VERSION 5.8 ;
BUSBITCHARS "[]" ;
DIVIDERCHAR "/" ;
UNITS
    DATABASE MICRONS 1000 ;
END UNITS

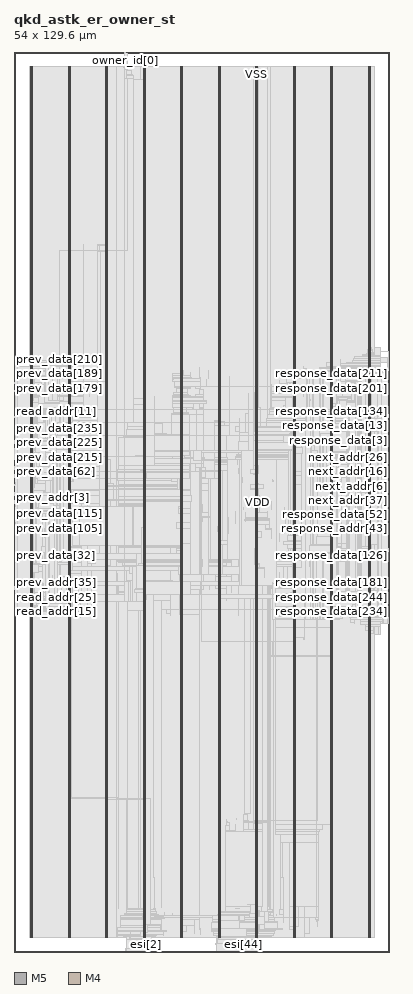
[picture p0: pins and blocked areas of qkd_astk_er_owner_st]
MACRO qkd_astk_er_owner_st
  FOREIGN qkd_astk_er_owner_st 0 0 ;
  CLASS BLOCK ;
  SIZE 54 BY 129.6 ;
  PIN aso[0]
    DIRECTION OUTPUT ;
    USE SIGNAL ;
    PORT
      LAYER M5 ;
        RECT  16.08 0 16.104 0.084 ;
    END
  END aso[0]
  PIN aso[10]
    DIRECTION OUTPUT ;
    USE SIGNAL ;
    PORT
      LAYER M5 ;
        RECT  17.04 0 17.064 0.084 ;
    END
  END aso[10]
  PIN aso[11]
    DIRECTION OUTPUT ;
    USE SIGNAL ;
    PORT
      LAYER M5 ;
        RECT  17.136 0 17.16 0.084 ;
    END
  END aso[11]
  PIN aso[12]
    DIRECTION OUTPUT ;
    USE SIGNAL ;
    PORT
      LAYER M5 ;
        RECT  17.232 0 17.256 0.084 ;
    END
  END aso[12]
  PIN aso[1]
    DIRECTION OUTPUT ;
    USE SIGNAL ;
    PORT
      LAYER M5 ;
        RECT  16.176 0 16.2 0.084 ;
    END
  END aso[1]
  PIN aso[2]
    DIRECTION OUTPUT ;
    USE SIGNAL ;
    PORT
      LAYER M5 ;
        RECT  16.272 0 16.296 0.084 ;
    END
  END aso[2]
  PIN aso[3]
    DIRECTION OUTPUT ;
    USE SIGNAL ;
    PORT
      LAYER M5 ;
        RECT  16.368 0 16.392 0.084 ;
    END
  END aso[3]
  PIN aso[4]
    DIRECTION OUTPUT ;
    USE SIGNAL ;
    PORT
      LAYER M5 ;
        RECT  16.464 0 16.488 0.084 ;
    END
  END aso[4]
  PIN aso[5]
    DIRECTION OUTPUT ;
    USE SIGNAL ;
    PORT
      LAYER M5 ;
        RECT  16.56 0 16.584 0.084 ;
    END
  END aso[5]
  PIN aso[6]
    DIRECTION OUTPUT ;
    USE SIGNAL ;
    PORT
      LAYER M5 ;
        RECT  16.656 0 16.68 0.084 ;
    END
  END aso[6]
  PIN aso[7]
    DIRECTION OUTPUT ;
    USE SIGNAL ;
    PORT
      LAYER M5 ;
        RECT  16.752 0 16.776 0.084 ;
    END
  END aso[7]
  PIN aso[8]
    DIRECTION OUTPUT ;
    USE SIGNAL ;
    PORT
      LAYER M5 ;
        RECT  16.848 0 16.872 0.084 ;
    END
  END aso[8]
  PIN aso[9]
    DIRECTION OUTPUT ;
    USE SIGNAL ;
    PORT
      LAYER M5 ;
        RECT  16.944 0 16.968 0.084 ;
    END
  END aso[9]
  PIN ck
    DIRECTION INPUT ;
    USE SIGNAL ;
    PORT
      LAYER M5 ;
        RECT  15.888 129.516 15.912 129.6 ;
    END
  END ck
  PIN com[0]
    DIRECTION INPUT ;
    USE SIGNAL ;
    PORT
      LAYER M5 ;
        RECT  17.328 0 17.352 0.084 ;
    END
  END com[0]
  PIN com[10]
    DIRECTION INPUT ;
    USE SIGNAL ;
    PORT
      LAYER M5 ;
        RECT  18.288 0 18.312 0.084 ;
    END
  END com[10]
  PIN com[11]
    DIRECTION INPUT ;
    USE SIGNAL ;
    PORT
      LAYER M5 ;
        RECT  18.384 0 18.408 0.084 ;
    END
  END com[11]
  PIN com[12]
    DIRECTION INPUT ;
    USE SIGNAL ;
    PORT
      LAYER M5 ;
        RECT  18.48 0 18.504 0.084 ;
    END
  END com[12]
  PIN com[13]
    DIRECTION INPUT ;
    USE SIGNAL ;
    PORT
      LAYER M5 ;
        RECT  18.576 0 18.6 0.084 ;
    END
  END com[13]
  PIN com[14]
    DIRECTION INPUT ;
    USE SIGNAL ;
    PORT
      LAYER M5 ;
        RECT  18.672 0 18.696 0.084 ;
    END
  END com[14]
  PIN com[15]
    DIRECTION INPUT ;
    USE SIGNAL ;
    PORT
      LAYER M5 ;
        RECT  18.768 0 18.792 0.084 ;
    END
  END com[15]
  PIN com[1]
    DIRECTION INPUT ;
    USE SIGNAL ;
    PORT
      LAYER M5 ;
        RECT  17.424 0 17.448 0.084 ;
    END
  END com[1]
  PIN com[2]
    DIRECTION INPUT ;
    USE SIGNAL ;
    PORT
      LAYER M5 ;
        RECT  17.52 0 17.544 0.084 ;
    END
  END com[2]
  PIN com[3]
    DIRECTION INPUT ;
    USE SIGNAL ;
    PORT
      LAYER M5 ;
        RECT  17.616 0 17.64 0.084 ;
    END
  END com[3]
  PIN com[4]
    DIRECTION INPUT ;
    USE SIGNAL ;
    PORT
      LAYER M5 ;
        RECT  17.712 0 17.736 0.084 ;
    END
  END com[4]
  PIN com[5]
    DIRECTION INPUT ;
    USE SIGNAL ;
    PORT
      LAYER M5 ;
        RECT  17.808 0 17.832 0.084 ;
    END
  END com[5]
  PIN com[6]
    DIRECTION INPUT ;
    USE SIGNAL ;
    PORT
      LAYER M5 ;
        RECT  17.904 0 17.928 0.084 ;
    END
  END com[6]
  PIN com[7]
    DIRECTION INPUT ;
    USE SIGNAL ;
    PORT
      LAYER M5 ;
        RECT  18 0 18.024 0.084 ;
    END
  END com[7]
  PIN com[8]
    DIRECTION INPUT ;
    USE SIGNAL ;
    PORT
      LAYER M5 ;
        RECT  18.096 0 18.12 0.084 ;
    END
  END com[8]
  PIN com[9]
    DIRECTION INPUT ;
    USE SIGNAL ;
    PORT
      LAYER M5 ;
        RECT  18.192 0 18.216 0.084 ;
    END
  END com[9]
  PIN esi[0]
    DIRECTION INPUT ;
    USE SIGNAL ;
    PORT
      LAYER M5 ;
        RECT  18.864 0 18.888 0.084 ;
    END
  END esi[0]
  PIN esi[10]
    DIRECTION INPUT ;
    USE SIGNAL ;
    PORT
      LAYER M5 ;
        RECT  29.808 0 29.832 0.084 ;
    END
  END esi[10]
  PIN esi[11]
    DIRECTION INPUT ;
    USE SIGNAL ;
    PORT
      LAYER M5 ;
        RECT  29.904 0 29.928 0.084 ;
    END
  END esi[11]
  PIN esi[12]
    DIRECTION INPUT ;
    USE SIGNAL ;
    PORT
      LAYER M5 ;
        RECT  30 0 30.024 0.084 ;
    END
  END esi[12]
  PIN esi[13]
    DIRECTION INPUT ;
    USE SIGNAL ;
    PORT
      LAYER M5 ;
        RECT  30.096 0 30.12 0.084 ;
    END
  END esi[13]
  PIN esi[14]
    DIRECTION INPUT ;
    USE SIGNAL ;
    PORT
      LAYER M5 ;
        RECT  30.192 0 30.216 0.084 ;
    END
  END esi[14]
  PIN esi[15]
    DIRECTION INPUT ;
    USE SIGNAL ;
    PORT
      LAYER M5 ;
        RECT  30.288 0 30.312 0.084 ;
    END
  END esi[15]
  PIN esi[16]
    DIRECTION INPUT ;
    USE SIGNAL ;
    PORT
      LAYER M5 ;
        RECT  30.384 0 30.408 0.084 ;
    END
  END esi[16]
  PIN esi[17]
    DIRECTION INPUT ;
    USE SIGNAL ;
    PORT
      LAYER M5 ;
        RECT  30.48 0 30.504 0.084 ;
    END
  END esi[17]
  PIN esi[18]
    DIRECTION INPUT ;
    USE SIGNAL ;
    PORT
      LAYER M5 ;
        RECT  30.576 0 30.6 0.084 ;
    END
  END esi[18]
  PIN esi[19]
    DIRECTION INPUT ;
    USE SIGNAL ;
    PORT
      LAYER M5 ;
        RECT  30.672 0 30.696 0.084 ;
    END
  END esi[19]
  PIN esi[1]
    DIRECTION INPUT ;
    USE SIGNAL ;
    PORT
      LAYER M5 ;
        RECT  18.96 0 18.984 0.084 ;
    END
  END esi[1]
  PIN esi[20]
    DIRECTION INPUT ;
    USE SIGNAL ;
    PORT
      LAYER M5 ;
        RECT  30.768 0 30.792 0.084 ;
    END
  END esi[20]
  PIN esi[21]
    DIRECTION INPUT ;
    USE SIGNAL ;
    PORT
      LAYER M5 ;
        RECT  30.864 0 30.888 0.084 ;
    END
  END esi[21]
  PIN esi[22]
    DIRECTION INPUT ;
    USE SIGNAL ;
    PORT
      LAYER M5 ;
        RECT  30.96 0 30.984 0.084 ;
    END
  END esi[22]
  PIN esi[23]
    DIRECTION INPUT ;
    USE SIGNAL ;
    PORT
      LAYER M5 ;
        RECT  31.056 0 31.08 0.084 ;
    END
  END esi[23]
  PIN esi[24]
    DIRECTION INPUT ;
    USE SIGNAL ;
    PORT
      LAYER M5 ;
        RECT  31.152 0 31.176 0.084 ;
    END
  END esi[24]
  PIN esi[25]
    DIRECTION INPUT ;
    USE SIGNAL ;
    PORT
      LAYER M5 ;
        RECT  31.248 0 31.272 0.084 ;
    END
  END esi[25]
  PIN esi[26]
    DIRECTION INPUT ;
    USE SIGNAL ;
    PORT
      LAYER M5 ;
        RECT  31.344 0 31.368 0.084 ;
    END
  END esi[26]
  PIN esi[27]
    DIRECTION INPUT ;
    USE SIGNAL ;
    PORT
      LAYER M5 ;
        RECT  31.44 0 31.464 0.084 ;
    END
  END esi[27]
  PIN esi[28]
    DIRECTION INPUT ;
    USE SIGNAL ;
    PORT
      LAYER M5 ;
        RECT  31.536 0 31.56 0.084 ;
    END
  END esi[28]
  PIN esi[29]
    DIRECTION INPUT ;
    USE SIGNAL ;
    PORT
      LAYER M5 ;
        RECT  31.632 0 31.656 0.084 ;
    END
  END esi[29]
  PIN esi[2]
    DIRECTION INPUT ;
    USE SIGNAL ;
    PORT
      LAYER M5 ;
        RECT  19.056 0 19.08 0.084 ;
    END
  END esi[2]
  PIN esi[30]
    DIRECTION INPUT ;
    USE SIGNAL ;
    PORT
      LAYER M5 ;
        RECT  31.728 0 31.752 0.084 ;
    END
  END esi[30]
  PIN esi[31]
    DIRECTION INPUT ;
    USE SIGNAL ;
    PORT
      LAYER M5 ;
        RECT  31.824 0 31.848 0.084 ;
    END
  END esi[31]
  PIN esi[32]
    DIRECTION INPUT ;
    USE SIGNAL ;
    PORT
      LAYER M5 ;
        RECT  31.92 0 31.944 0.084 ;
    END
  END esi[32]
  PIN esi[33]
    DIRECTION INPUT ;
    USE SIGNAL ;
    PORT
      LAYER M5 ;
        RECT  32.016 0 32.04 0.084 ;
    END
  END esi[33]
  PIN esi[34]
    DIRECTION INPUT ;
    USE SIGNAL ;
    PORT
      LAYER M5 ;
        RECT  32.112 0 32.136 0.084 ;
    END
  END esi[34]
  PIN esi[35]
    DIRECTION INPUT ;
    USE SIGNAL ;
    PORT
      LAYER M5 ;
        RECT  32.208 0 32.232 0.084 ;
    END
  END esi[35]
  PIN esi[36]
    DIRECTION INPUT ;
    USE SIGNAL ;
    PORT
      LAYER M5 ;
        RECT  32.304 0 32.328 0.084 ;
    END
  END esi[36]
  PIN esi[37]
    DIRECTION INPUT ;
    USE SIGNAL ;
    PORT
      LAYER M5 ;
        RECT  32.4 0 32.424 0.084 ;
    END
  END esi[37]
  PIN esi[38]
    DIRECTION INPUT ;
    USE SIGNAL ;
    PORT
      LAYER M5 ;
        RECT  32.496 0 32.52 0.084 ;
    END
  END esi[38]
  PIN esi[39]
    DIRECTION INPUT ;
    USE SIGNAL ;
    PORT
      LAYER M5 ;
        RECT  32.592 0 32.616 0.084 ;
    END
  END esi[39]
  PIN esi[3]
    DIRECTION INPUT ;
    USE SIGNAL ;
    PORT
      LAYER M5 ;
        RECT  29.136 0 29.16 0.084 ;
    END
  END esi[3]
  PIN esi[40]
    DIRECTION INPUT ;
    USE SIGNAL ;
    PORT
      LAYER M5 ;
        RECT  32.688 0 32.712 0.084 ;
    END
  END esi[40]
  PIN esi[41]
    DIRECTION INPUT ;
    USE SIGNAL ;
    PORT
      LAYER M5 ;
        RECT  32.784 0 32.808 0.084 ;
    END
  END esi[41]
  PIN esi[42]
    DIRECTION INPUT ;
    USE SIGNAL ;
    PORT
      LAYER M5 ;
        RECT  32.88 0 32.904 0.084 ;
    END
  END esi[42]
  PIN esi[43]
    DIRECTION INPUT ;
    USE SIGNAL ;
    PORT
      LAYER M5 ;
        RECT  32.976 0 33 0.084 ;
    END
  END esi[43]
  PIN esi[44]
    DIRECTION INPUT ;
    USE SIGNAL ;
    PORT
      LAYER M5 ;
        RECT  33.072 0 33.096 0.084 ;
    END
  END esi[44]
  PIN esi[45]
    DIRECTION INPUT ;
    USE SIGNAL ;
    PORT
      LAYER M5 ;
        RECT  33.168 0 33.192 0.084 ;
    END
  END esi[45]
  PIN esi[46]
    DIRECTION INPUT ;
    USE SIGNAL ;
    PORT
      LAYER M5 ;
        RECT  33.264 0 33.288 0.084 ;
    END
  END esi[46]
  PIN esi[47]
    DIRECTION INPUT ;
    USE SIGNAL ;
    PORT
      LAYER M5 ;
        RECT  33.36 0 33.384 0.084 ;
    END
  END esi[47]
  PIN esi[48]
    DIRECTION INPUT ;
    USE SIGNAL ;
    PORT
      LAYER M5 ;
        RECT  33.456 0 33.48 0.084 ;
    END
  END esi[48]
  PIN esi[49]
    DIRECTION INPUT ;
    USE SIGNAL ;
    PORT
      LAYER M5 ;
        RECT  33.552 0 33.576 0.084 ;
    END
  END esi[49]
  PIN esi[4]
    DIRECTION INPUT ;
    USE SIGNAL ;
    PORT
      LAYER M5 ;
        RECT  29.232 0 29.256 0.084 ;
    END
  END esi[4]
  PIN esi[50]
    DIRECTION INPUT ;
    USE SIGNAL ;
    PORT
      LAYER M5 ;
        RECT  33.648 0 33.672 0.084 ;
    END
  END esi[50]
  PIN esi[51]
    DIRECTION INPUT ;
    USE SIGNAL ;
    PORT
      LAYER M5 ;
        RECT  33.744 0 33.768 0.084 ;
    END
  END esi[51]
  PIN esi[52]
    DIRECTION INPUT ;
    USE SIGNAL ;
    PORT
      LAYER M5 ;
        RECT  33.84 0 33.864 0.084 ;
    END
  END esi[52]
  PIN esi[53]
    DIRECTION INPUT ;
    USE SIGNAL ;
    PORT
      LAYER M5 ;
        RECT  33.936 0 33.96 0.084 ;
    END
  END esi[53]
  PIN esi[54]
    DIRECTION INPUT ;
    USE SIGNAL ;
    PORT
      LAYER M5 ;
        RECT  34.032 0 34.056 0.084 ;
    END
  END esi[54]
  PIN esi[55]
    DIRECTION INPUT ;
    USE SIGNAL ;
    PORT
      LAYER M5 ;
        RECT  34.128 0 34.152 0.084 ;
    END
  END esi[55]
  PIN esi[56]
    DIRECTION INPUT ;
    USE SIGNAL ;
    PORT
      LAYER M5 ;
        RECT  34.224 0 34.248 0.084 ;
    END
  END esi[56]
  PIN esi[57]
    DIRECTION INPUT ;
    USE SIGNAL ;
    PORT
      LAYER M5 ;
        RECT  34.32 0 34.344 0.084 ;
    END
  END esi[57]
  PIN esi[58]
    DIRECTION INPUT ;
    USE SIGNAL ;
    PORT
      LAYER M5 ;
        RECT  34.416 0 34.44 0.084 ;
    END
  END esi[58]
  PIN esi[59]
    DIRECTION INPUT ;
    USE SIGNAL ;
    PORT
      LAYER M5 ;
        RECT  34.512 0 34.536 0.084 ;
    END
  END esi[59]
  PIN esi[5]
    DIRECTION INPUT ;
    USE SIGNAL ;
    PORT
      LAYER M5 ;
        RECT  29.328 0 29.352 0.084 ;
    END
  END esi[5]
  PIN esi[60]
    DIRECTION INPUT ;
    USE SIGNAL ;
    PORT
      LAYER M5 ;
        RECT  34.608 0 34.632 0.084 ;
    END
  END esi[60]
  PIN esi[61]
    DIRECTION INPUT ;
    USE SIGNAL ;
    PORT
      LAYER M5 ;
        RECT  34.704 0 34.728 0.084 ;
    END
  END esi[61]
  PIN esi[62]
    DIRECTION INPUT ;
    USE SIGNAL ;
    PORT
      LAYER M5 ;
        RECT  34.8 0 34.824 0.084 ;
    END
  END esi[62]
  PIN esi[63]
    DIRECTION INPUT ;
    USE SIGNAL ;
    PORT
      LAYER M5 ;
        RECT  34.896 0 34.92 0.084 ;
    END
  END esi[63]
  PIN esi[6]
    DIRECTION INPUT ;
    USE SIGNAL ;
    PORT
      LAYER M5 ;
        RECT  29.424 0 29.448 0.084 ;
    END
  END esi[6]
  PIN esi[7]
    DIRECTION INPUT ;
    USE SIGNAL ;
    PORT
      LAYER M5 ;
        RECT  29.52 0 29.544 0.084 ;
    END
  END esi[7]
  PIN esi[8]
    DIRECTION INPUT ;
    USE SIGNAL ;
    PORT
      LAYER M5 ;
        RECT  29.616 0 29.64 0.084 ;
    END
  END esi[8]
  PIN esi[9]
    DIRECTION INPUT ;
    USE SIGNAL ;
    PORT
      LAYER M5 ;
        RECT  29.712 0 29.736 0.084 ;
    END
  END esi[9]
  PIN eso_v
    DIRECTION INPUT ;
    USE SIGNAL ;
    PORT
      LAYER M5 ;
        RECT  34.992 0 35.016 0.084 ;
    END
  END eso_v
  PIN fault
    DIRECTION OUTPUT ;
    USE SIGNAL ;
    PORT
      LAYER M4 ;
        RECT  53.916 67.536 54 67.56 ;
    END
  END fault
  PIN next_addr[0]
    DIRECTION OUTPUT ;
    USE SIGNAL ;
    PORT
      LAYER M4 ;
        RECT  53.916 67.632 54 67.656 ;
    END
  END next_addr[0]
  PIN next_addr[10]
    DIRECTION OUTPUT ;
    USE SIGNAL ;
    PORT
      LAYER M4 ;
        RECT  53.916 68.592 54 68.616 ;
    END
  END next_addr[10]
  PIN next_addr[11]
    DIRECTION OUTPUT ;
    USE SIGNAL ;
    PORT
      LAYER M4 ;
        RECT  53.916 68.688 54 68.712 ;
    END
  END next_addr[11]
  PIN next_addr[12]
    DIRECTION OUTPUT ;
    USE SIGNAL ;
    PORT
      LAYER M4 ;
        RECT  53.916 68.784 54 68.808 ;
    END
  END next_addr[12]
  PIN next_addr[13]
    DIRECTION OUTPUT ;
    USE SIGNAL ;
    PORT
      LAYER M4 ;
        RECT  53.916 68.88 54 68.904 ;
    END
  END next_addr[13]
  PIN next_addr[14]
    DIRECTION OUTPUT ;
    USE SIGNAL ;
    PORT
      LAYER M4 ;
        RECT  53.916 68.976 54 69 ;
    END
  END next_addr[14]
  PIN next_addr[15]
    DIRECTION OUTPUT ;
    USE SIGNAL ;
    PORT
      LAYER M4 ;
        RECT  53.916 69.072 54 69.096 ;
    END
  END next_addr[15]
  PIN next_addr[16]
    DIRECTION OUTPUT ;
    USE SIGNAL ;
    PORT
      LAYER M4 ;
        RECT  53.916 69.168 54 69.192 ;
    END
  END next_addr[16]
  PIN next_addr[17]
    DIRECTION OUTPUT ;
    USE SIGNAL ;
    PORT
      LAYER M4 ;
        RECT  53.916 69.264 54 69.288 ;
    END
  END next_addr[17]
  PIN next_addr[18]
    DIRECTION OUTPUT ;
    USE SIGNAL ;
    PORT
      LAYER M4 ;
        RECT  53.916 69.36 54 69.384 ;
    END
  END next_addr[18]
  PIN next_addr[19]
    DIRECTION OUTPUT ;
    USE SIGNAL ;
    PORT
      LAYER M4 ;
        RECT  53.916 69.456 54 69.48 ;
    END
  END next_addr[19]
  PIN next_addr[1]
    DIRECTION OUTPUT ;
    USE SIGNAL ;
    PORT
      LAYER M4 ;
        RECT  53.916 67.728 54 67.752 ;
    END
  END next_addr[1]
  PIN next_addr[20]
    DIRECTION OUTPUT ;
    USE SIGNAL ;
    PORT
      LAYER M4 ;
        RECT  53.916 69.552 54 69.576 ;
    END
  END next_addr[20]
  PIN next_addr[21]
    DIRECTION OUTPUT ;
    USE SIGNAL ;
    PORT
      LAYER M4 ;
        RECT  53.916 69.648 54 69.672 ;
    END
  END next_addr[21]
  PIN next_addr[22]
    DIRECTION OUTPUT ;
    USE SIGNAL ;
    PORT
      LAYER M4 ;
        RECT  53.916 69.744 54 69.768 ;
    END
  END next_addr[22]
  PIN next_addr[23]
    DIRECTION OUTPUT ;
    USE SIGNAL ;
    PORT
      LAYER M4 ;
        RECT  53.916 69.84 54 69.864 ;
    END
  END next_addr[23]
  PIN next_addr[24]
    DIRECTION OUTPUT ;
    USE SIGNAL ;
    PORT
      LAYER M4 ;
        RECT  53.916 69.936 54 69.96 ;
    END
  END next_addr[24]
  PIN next_addr[25]
    DIRECTION OUTPUT ;
    USE SIGNAL ;
    PORT
      LAYER M4 ;
        RECT  53.916 70.032 54 70.056 ;
    END
  END next_addr[25]
  PIN next_addr[26]
    DIRECTION OUTPUT ;
    USE SIGNAL ;
    PORT
      LAYER M4 ;
        RECT  53.916 70.128 54 70.152 ;
    END
  END next_addr[26]
  PIN next_addr[27]
    DIRECTION OUTPUT ;
    USE SIGNAL ;
    PORT
      LAYER M4 ;
        RECT  53.916 70.224 54 70.248 ;
    END
  END next_addr[27]
  PIN next_addr[28]
    DIRECTION OUTPUT ;
    USE SIGNAL ;
    PORT
      LAYER M4 ;
        RECT  53.916 70.32 54 70.344 ;
    END
  END next_addr[28]
  PIN next_addr[29]
    DIRECTION OUTPUT ;
    USE SIGNAL ;
    PORT
      LAYER M4 ;
        RECT  53.916 70.416 54 70.44 ;
    END
  END next_addr[29]
  PIN next_addr[2]
    DIRECTION OUTPUT ;
    USE SIGNAL ;
    PORT
      LAYER M4 ;
        RECT  53.916 67.824 54 67.848 ;
    END
  END next_addr[2]
  PIN next_addr[30]
    DIRECTION OUTPUT ;
    USE SIGNAL ;
    PORT
      LAYER M4 ;
        RECT  53.916 70.512 54 70.536 ;
    END
  END next_addr[30]
  PIN next_addr[31]
    DIRECTION OUTPUT ;
    USE SIGNAL ;
    PORT
      LAYER M4 ;
        RECT  53.916 64.464 54 64.488 ;
    END
  END next_addr[31]
  PIN next_addr[32]
    DIRECTION OUTPUT ;
    USE SIGNAL ;
    PORT
      LAYER M4 ;
        RECT  53.916 64.56 54 64.584 ;
    END
  END next_addr[32]
  PIN next_addr[33]
    DIRECTION OUTPUT ;
    USE SIGNAL ;
    PORT
      LAYER M4 ;
        RECT  53.916 64.656 54 64.68 ;
    END
  END next_addr[33]
  PIN next_addr[34]
    DIRECTION OUTPUT ;
    USE SIGNAL ;
    PORT
      LAYER M4 ;
        RECT  53.916 64.752 54 64.776 ;
    END
  END next_addr[34]
  PIN next_addr[35]
    DIRECTION OUTPUT ;
    USE SIGNAL ;
    PORT
      LAYER M4 ;
        RECT  53.916 64.848 54 64.872 ;
    END
  END next_addr[35]
  PIN next_addr[36]
    DIRECTION OUTPUT ;
    USE SIGNAL ;
    PORT
      LAYER M4 ;
        RECT  53.916 64.944 54 64.968 ;
    END
  END next_addr[36]
  PIN next_addr[37]
    DIRECTION OUTPUT ;
    USE SIGNAL ;
    PORT
      LAYER M4 ;
        RECT  53.916 65.04 54 65.064 ;
    END
  END next_addr[37]
  PIN next_addr[38]
    DIRECTION OUTPUT ;
    USE SIGNAL ;
    PORT
      LAYER M4 ;
        RECT  53.916 65.136 54 65.16 ;
    END
  END next_addr[38]
  PIN next_addr[39]
    DIRECTION OUTPUT ;
    USE SIGNAL ;
    PORT
      LAYER M4 ;
        RECT  53.916 65.232 54 65.256 ;
    END
  END next_addr[39]
  PIN next_addr[3]
    DIRECTION OUTPUT ;
    USE SIGNAL ;
    PORT
      LAYER M4 ;
        RECT  53.916 67.92 54 67.944 ;
    END
  END next_addr[3]
  PIN next_addr[40]
    DIRECTION OUTPUT ;
    USE SIGNAL ;
    PORT
      LAYER M4 ;
        RECT  53.916 65.328 54 65.352 ;
    END
  END next_addr[40]
  PIN next_addr[41]
    DIRECTION OUTPUT ;
    USE SIGNAL ;
    PORT
      LAYER M4 ;
        RECT  53.916 65.424 54 65.448 ;
    END
  END next_addr[41]
  PIN next_addr[42]
    DIRECTION OUTPUT ;
    USE SIGNAL ;
    PORT
      LAYER M4 ;
        RECT  53.916 65.52 54 65.544 ;
    END
  END next_addr[42]
  PIN next_addr[43]
    DIRECTION OUTPUT ;
    USE SIGNAL ;
    PORT
      LAYER M4 ;
        RECT  53.916 65.616 54 65.64 ;
    END
  END next_addr[43]
  PIN next_addr[4]
    DIRECTION OUTPUT ;
    USE SIGNAL ;
    PORT
      LAYER M4 ;
        RECT  53.916 68.016 54 68.04 ;
    END
  END next_addr[4]
  PIN next_addr[5]
    DIRECTION OUTPUT ;
    USE SIGNAL ;
    PORT
      LAYER M4 ;
        RECT  53.916 68.112 54 68.136 ;
    END
  END next_addr[5]
  PIN next_addr[6]
    DIRECTION OUTPUT ;
    USE SIGNAL ;
    PORT
      LAYER M4 ;
        RECT  53.916 68.208 54 68.232 ;
    END
  END next_addr[6]
  PIN next_addr[7]
    DIRECTION OUTPUT ;
    USE SIGNAL ;
    PORT
      LAYER M4 ;
        RECT  53.916 68.304 54 68.328 ;
    END
  END next_addr[7]
  PIN next_addr[8]
    DIRECTION OUTPUT ;
    USE SIGNAL ;
    PORT
      LAYER M4 ;
        RECT  53.916 68.4 54 68.424 ;
    END
  END next_addr[8]
  PIN next_addr[9]
    DIRECTION OUTPUT ;
    USE SIGNAL ;
    PORT
      LAYER M4 ;
        RECT  53.916 68.496 54 68.52 ;
    END
  END next_addr[9]
  PIN next_v[0]
    DIRECTION OUTPUT ;
    USE SIGNAL ;
    PORT
      LAYER M4 ;
        RECT  53.916 65.712 54 65.736 ;
    END
  END next_v[0]
  PIN next_v[1]
    DIRECTION OUTPUT ;
    USE SIGNAL ;
    PORT
      LAYER M4 ;
        RECT  53.916 65.808 54 65.832 ;
    END
  END next_v[1]
  PIN next_v[2]
    DIRECTION OUTPUT ;
    USE SIGNAL ;
    PORT
      LAYER M4 ;
        RECT  53.916 65.904 54 65.928 ;
    END
  END next_v[2]
  PIN next_v[3]
    DIRECTION OUTPUT ;
    USE SIGNAL ;
    PORT
      LAYER M4 ;
        RECT  53.916 66 54 66.024 ;
    END
  END next_v[3]
  PIN owner_id[0]
    DIRECTION INPUT ;
    USE SIGNAL ;
    PORT
      LAYER M5 ;
        RECT  15.984 129.516 16.008 129.6 ;
    END
  END owner_id[0]
  PIN owner_id[1]
    DIRECTION INPUT ;
    USE SIGNAL ;
    PORT
      LAYER M5 ;
        RECT  16.08 129.516 16.104 129.6 ;
    END
  END owner_id[1]
  PIN owner_id[2]
    DIRECTION INPUT ;
    USE SIGNAL ;
    PORT
      LAYER M5 ;
        RECT  16.176 129.516 16.2 129.6 ;
    END
  END owner_id[2]
  PIN prev_addr[0]
    DIRECTION INPUT ;
    USE SIGNAL ;
    PORT
      LAYER M4 ;
        RECT  0 65.136 0.084 65.16 ;
    END
  END prev_addr[0]
  PIN prev_addr[10]
    DIRECTION INPUT ;
    USE SIGNAL ;
    PORT
      LAYER M4 ;
        RECT  0 66.096 0.084 66.12 ;
    END
  END prev_addr[10]
  PIN prev_addr[11]
    DIRECTION INPUT ;
    USE SIGNAL ;
    PORT
      LAYER M4 ;
        RECT  0 66.192 0.084 66.216 ;
    END
  END prev_addr[11]
  PIN prev_addr[12]
    DIRECTION INPUT ;
    USE SIGNAL ;
    PORT
      LAYER M4 ;
        RECT  0 66.288 0.084 66.312 ;
    END
  END prev_addr[12]
  PIN prev_addr[13]
    DIRECTION INPUT ;
    USE SIGNAL ;
    PORT
      LAYER M4 ;
        RECT  0 66.384 0.084 66.408 ;
    END
  END prev_addr[13]
  PIN prev_addr[14]
    DIRECTION INPUT ;
    USE SIGNAL ;
    PORT
      LAYER M4 ;
        RECT  0 66.48 0.084 66.504 ;
    END
  END prev_addr[14]
  PIN prev_addr[15]
    DIRECTION INPUT ;
    USE SIGNAL ;
    PORT
      LAYER M4 ;
        RECT  0 66.576 0.084 66.6 ;
    END
  END prev_addr[15]
  PIN prev_addr[16]
    DIRECTION INPUT ;
    USE SIGNAL ;
    PORT
      LAYER M4 ;
        RECT  0 66.672 0.084 66.696 ;
    END
  END prev_addr[16]
  PIN prev_addr[17]
    DIRECTION INPUT ;
    USE SIGNAL ;
    PORT
      LAYER M4 ;
        RECT  0 66.768 0.084 66.792 ;
    END
  END prev_addr[17]
  PIN prev_addr[18]
    DIRECTION INPUT ;
    USE SIGNAL ;
    PORT
      LAYER M4 ;
        RECT  0 66.864 0.084 66.888 ;
    END
  END prev_addr[18]
  PIN prev_addr[19]
    DIRECTION INPUT ;
    USE SIGNAL ;
    PORT
      LAYER M4 ;
        RECT  0 66.96 0.084 66.984 ;
    END
  END prev_addr[19]
  PIN prev_addr[1]
    DIRECTION INPUT ;
    USE SIGNAL ;
    PORT
      LAYER M4 ;
        RECT  0 65.232 0.084 65.256 ;
    END
  END prev_addr[1]
  PIN prev_addr[20]
    DIRECTION INPUT ;
    USE SIGNAL ;
    PORT
      LAYER M4 ;
        RECT  0 67.056 0.084 67.08 ;
    END
  END prev_addr[20]
  PIN prev_addr[21]
    DIRECTION INPUT ;
    USE SIGNAL ;
    PORT
      LAYER M4 ;
        RECT  0 67.152 0.084 67.176 ;
    END
  END prev_addr[21]
  PIN prev_addr[22]
    DIRECTION INPUT ;
    USE SIGNAL ;
    PORT
      LAYER M4 ;
        RECT  0 67.248 0.084 67.272 ;
    END
  END prev_addr[22]
  PIN prev_addr[23]
    DIRECTION INPUT ;
    USE SIGNAL ;
    PORT
      LAYER M4 ;
        RECT  0 67.344 0.084 67.368 ;
    END
  END prev_addr[23]
  PIN prev_addr[24]
    DIRECTION INPUT ;
    USE SIGNAL ;
    PORT
      LAYER M4 ;
        RECT  0 67.44 0.084 67.464 ;
    END
  END prev_addr[24]
  PIN prev_addr[25]
    DIRECTION INPUT ;
    USE SIGNAL ;
    PORT
      LAYER M4 ;
        RECT  0 67.536 0.084 67.56 ;
    END
  END prev_addr[25]
  PIN prev_addr[26]
    DIRECTION INPUT ;
    USE SIGNAL ;
    PORT
      LAYER M4 ;
        RECT  0 67.632 0.084 67.656 ;
    END
  END prev_addr[26]
  PIN prev_addr[27]
    DIRECTION INPUT ;
    USE SIGNAL ;
    PORT
      LAYER M4 ;
        RECT  0 67.728 0.084 67.752 ;
    END
  END prev_addr[27]
  PIN prev_addr[28]
    DIRECTION INPUT ;
    USE SIGNAL ;
    PORT
      LAYER M4 ;
        RECT  0 67.824 0.084 67.848 ;
    END
  END prev_addr[28]
  PIN prev_addr[29]
    DIRECTION INPUT ;
    USE SIGNAL ;
    PORT
      LAYER M4 ;
        RECT  0 67.92 0.084 67.944 ;
    END
  END prev_addr[29]
  PIN prev_addr[2]
    DIRECTION INPUT ;
    USE SIGNAL ;
    PORT
      LAYER M4 ;
        RECT  0 65.328 0.084 65.352 ;
    END
  END prev_addr[2]
  PIN prev_addr[30]
    DIRECTION INPUT ;
    USE SIGNAL ;
    PORT
      LAYER M4 ;
        RECT  0 68.016 0.084 68.04 ;
    END
  END prev_addr[30]
  PIN prev_addr[31]
    DIRECTION INPUT ;
    USE SIGNAL ;
    PORT
      LAYER M4 ;
        RECT  0 68.112 0.084 68.136 ;
    END
  END prev_addr[31]
  PIN prev_addr[32]
    DIRECTION INPUT ;
    USE SIGNAL ;
    PORT
      LAYER M4 ;
        RECT  0 52.848 0.084 52.872 ;
    END
  END prev_addr[32]
  PIN prev_addr[33]
    DIRECTION INPUT ;
    USE SIGNAL ;
    PORT
      LAYER M4 ;
        RECT  0 52.944 0.084 52.968 ;
    END
  END prev_addr[33]
  PIN prev_addr[34]
    DIRECTION INPUT ;
    USE SIGNAL ;
    PORT
      LAYER M4 ;
        RECT  0 53.04 0.084 53.064 ;
    END
  END prev_addr[34]
  PIN prev_addr[35]
    DIRECTION INPUT ;
    USE SIGNAL ;
    PORT
      LAYER M4 ;
        RECT  0 53.136 0.084 53.16 ;
    END
  END prev_addr[35]
  PIN prev_addr[36]
    DIRECTION INPUT ;
    USE SIGNAL ;
    PORT
      LAYER M4 ;
        RECT  0 53.232 0.084 53.256 ;
    END
  END prev_addr[36]
  PIN prev_addr[37]
    DIRECTION INPUT ;
    USE SIGNAL ;
    PORT
      LAYER M4 ;
        RECT  0 53.328 0.084 53.352 ;
    END
  END prev_addr[37]
  PIN prev_addr[38]
    DIRECTION INPUT ;
    USE SIGNAL ;
    PORT
      LAYER M4 ;
        RECT  0 53.424 0.084 53.448 ;
    END
  END prev_addr[38]
  PIN prev_addr[39]
    DIRECTION INPUT ;
    USE SIGNAL ;
    PORT
      LAYER M4 ;
        RECT  0 53.52 0.084 53.544 ;
    END
  END prev_addr[39]
  PIN prev_addr[3]
    DIRECTION INPUT ;
    USE SIGNAL ;
    PORT
      LAYER M4 ;
        RECT  0 65.424 0.084 65.448 ;
    END
  END prev_addr[3]
  PIN prev_addr[40]
    DIRECTION INPUT ;
    USE SIGNAL ;
    PORT
      LAYER M4 ;
        RECT  0 53.616 0.084 53.64 ;
    END
  END prev_addr[40]
  PIN prev_addr[41]
    DIRECTION INPUT ;
    USE SIGNAL ;
    PORT
      LAYER M4 ;
        RECT  0 53.712 0.084 53.736 ;
    END
  END prev_addr[41]
  PIN prev_addr[42]
    DIRECTION INPUT ;
    USE SIGNAL ;
    PORT
      LAYER M4 ;
        RECT  0 53.808 0.084 53.832 ;
    END
  END prev_addr[42]
  PIN prev_addr[43]
    DIRECTION INPUT ;
    USE SIGNAL ;
    PORT
      LAYER M4 ;
        RECT  0 53.904 0.084 53.928 ;
    END
  END prev_addr[43]
  PIN prev_addr[4]
    DIRECTION INPUT ;
    USE SIGNAL ;
    PORT
      LAYER M4 ;
        RECT  0 65.52 0.084 65.544 ;
    END
  END prev_addr[4]
  PIN prev_addr[5]
    DIRECTION INPUT ;
    USE SIGNAL ;
    PORT
      LAYER M4 ;
        RECT  0 65.616 0.084 65.64 ;
    END
  END prev_addr[5]
  PIN prev_addr[6]
    DIRECTION INPUT ;
    USE SIGNAL ;
    PORT
      LAYER M4 ;
        RECT  0 65.712 0.084 65.736 ;
    END
  END prev_addr[6]
  PIN prev_addr[7]
    DIRECTION INPUT ;
    USE SIGNAL ;
    PORT
      LAYER M4 ;
        RECT  0 65.808 0.084 65.832 ;
    END
  END prev_addr[7]
  PIN prev_addr[8]
    DIRECTION INPUT ;
    USE SIGNAL ;
    PORT
      LAYER M4 ;
        RECT  0 65.904 0.084 65.928 ;
    END
  END prev_addr[8]
  PIN prev_addr[9]
    DIRECTION INPUT ;
    USE SIGNAL ;
    PORT
      LAYER M4 ;
        RECT  0 66 0.084 66.024 ;
    END
  END prev_addr[9]
  PIN prev_data[0]
    DIRECTION INPUT ;
    USE SIGNAL ;
    PORT
      LAYER M4 ;
        RECT  0 54 0.084 54.024 ;
    END
  END prev_data[0]
  PIN prev_data[100]
    DIRECTION INPUT ;
    USE SIGNAL ;
    PORT
      LAYER M4 ;
        RECT  0 60.528 0.084 60.552 ;
    END
  END prev_data[100]
  PIN prev_data[101]
    DIRECTION INPUT ;
    USE SIGNAL ;
    PORT
      LAYER M4 ;
        RECT  0 60.624 0.084 60.648 ;
    END
  END prev_data[101]
  PIN prev_data[102]
    DIRECTION INPUT ;
    USE SIGNAL ;
    PORT
      LAYER M4 ;
        RECT  0 60.72 0.084 60.744 ;
    END
  END prev_data[102]
  PIN prev_data[103]
    DIRECTION INPUT ;
    USE SIGNAL ;
    PORT
      LAYER M4 ;
        RECT  0 60.816 0.084 60.84 ;
    END
  END prev_data[103]
  PIN prev_data[104]
    DIRECTION INPUT ;
    USE SIGNAL ;
    PORT
      LAYER M4 ;
        RECT  0 60.912 0.084 60.936 ;
    END
  END prev_data[104]
  PIN prev_data[105]
    DIRECTION INPUT ;
    USE SIGNAL ;
    PORT
      LAYER M4 ;
        RECT  0 61.008 0.084 61.032 ;
    END
  END prev_data[105]
  PIN prev_data[106]
    DIRECTION INPUT ;
    USE SIGNAL ;
    PORT
      LAYER M4 ;
        RECT  0 61.104 0.084 61.128 ;
    END
  END prev_data[106]
  PIN prev_data[107]
    DIRECTION INPUT ;
    USE SIGNAL ;
    PORT
      LAYER M4 ;
        RECT  0 61.2 0.084 61.224 ;
    END
  END prev_data[107]
  PIN prev_data[108]
    DIRECTION INPUT ;
    USE SIGNAL ;
    PORT
      LAYER M4 ;
        RECT  0 61.296 0.084 61.32 ;
    END
  END prev_data[108]
  PIN prev_data[109]
    DIRECTION INPUT ;
    USE SIGNAL ;
    PORT
      LAYER M4 ;
        RECT  0 61.392 0.084 61.416 ;
    END
  END prev_data[109]
  PIN prev_data[10]
    DIRECTION INPUT ;
    USE SIGNAL ;
    PORT
      LAYER M4 ;
        RECT  0 54.96 0.084 54.984 ;
    END
  END prev_data[10]
  PIN prev_data[110]
    DIRECTION INPUT ;
    USE SIGNAL ;
    PORT
      LAYER M4 ;
        RECT  0 61.488 0.084 61.512 ;
    END
  END prev_data[110]
  PIN prev_data[111]
    DIRECTION INPUT ;
    USE SIGNAL ;
    PORT
      LAYER M4 ;
        RECT  0 61.584 0.084 61.608 ;
    END
  END prev_data[111]
  PIN prev_data[112]
    DIRECTION INPUT ;
    USE SIGNAL ;
    PORT
      LAYER M4 ;
        RECT  0 61.68 0.084 61.704 ;
    END
  END prev_data[112]
  PIN prev_data[113]
    DIRECTION INPUT ;
    USE SIGNAL ;
    PORT
      LAYER M4 ;
        RECT  0 61.776 0.084 61.8 ;
    END
  END prev_data[113]
  PIN prev_data[114]
    DIRECTION INPUT ;
    USE SIGNAL ;
    PORT
      LAYER M4 ;
        RECT  0 61.872 0.084 61.896 ;
    END
  END prev_data[114]
  PIN prev_data[115]
    DIRECTION INPUT ;
    USE SIGNAL ;
    PORT
      LAYER M4 ;
        RECT  0 61.968 0.084 61.992 ;
    END
  END prev_data[115]
  PIN prev_data[116]
    DIRECTION INPUT ;
    USE SIGNAL ;
    PORT
      LAYER M4 ;
        RECT  0 62.064 0.084 62.088 ;
    END
  END prev_data[116]
  PIN prev_data[117]
    DIRECTION INPUT ;
    USE SIGNAL ;
    PORT
      LAYER M4 ;
        RECT  0 62.16 0.084 62.184 ;
    END
  END prev_data[117]
  PIN prev_data[118]
    DIRECTION INPUT ;
    USE SIGNAL ;
    PORT
      LAYER M4 ;
        RECT  0 62.256 0.084 62.28 ;
    END
  END prev_data[118]
  PIN prev_data[119]
    DIRECTION INPUT ;
    USE SIGNAL ;
    PORT
      LAYER M4 ;
        RECT  0 62.352 0.084 62.376 ;
    END
  END prev_data[119]
  PIN prev_data[11]
    DIRECTION INPUT ;
    USE SIGNAL ;
    PORT
      LAYER M4 ;
        RECT  0 55.056 0.084 55.08 ;
    END
  END prev_data[11]
  PIN prev_data[120]
    DIRECTION INPUT ;
    USE SIGNAL ;
    PORT
      LAYER M4 ;
        RECT  0 62.448 0.084 62.472 ;
    END
  END prev_data[120]
  PIN prev_data[121]
    DIRECTION INPUT ;
    USE SIGNAL ;
    PORT
      LAYER M4 ;
        RECT  0 62.544 0.084 62.568 ;
    END
  END prev_data[121]
  PIN prev_data[122]
    DIRECTION INPUT ;
    USE SIGNAL ;
    PORT
      LAYER M4 ;
        RECT  0 62.64 0.084 62.664 ;
    END
  END prev_data[122]
  PIN prev_data[123]
    DIRECTION INPUT ;
    USE SIGNAL ;
    PORT
      LAYER M4 ;
        RECT  0 62.736 0.084 62.76 ;
    END
  END prev_data[123]
  PIN prev_data[124]
    DIRECTION INPUT ;
    USE SIGNAL ;
    PORT
      LAYER M4 ;
        RECT  0 62.832 0.084 62.856 ;
    END
  END prev_data[124]
  PIN prev_data[125]
    DIRECTION INPUT ;
    USE SIGNAL ;
    PORT
      LAYER M4 ;
        RECT  0 62.928 0.084 62.952 ;
    END
  END prev_data[125]
  PIN prev_data[126]
    DIRECTION INPUT ;
    USE SIGNAL ;
    PORT
      LAYER M4 ;
        RECT  0 63.024 0.084 63.048 ;
    END
  END prev_data[126]
  PIN prev_data[127]
    DIRECTION INPUT ;
    USE SIGNAL ;
    PORT
      LAYER M4 ;
        RECT  0 63.12 0.084 63.144 ;
    END
  END prev_data[127]
  PIN prev_data[128]
    DIRECTION INPUT ;
    USE SIGNAL ;
    PORT
      LAYER M4 ;
        RECT  0 63.216 0.084 63.24 ;
    END
  END prev_data[128]
  PIN prev_data[129]
    DIRECTION INPUT ;
    USE SIGNAL ;
    PORT
      LAYER M4 ;
        RECT  0 63.312 0.084 63.336 ;
    END
  END prev_data[129]
  PIN prev_data[12]
    DIRECTION INPUT ;
    USE SIGNAL ;
    PORT
      LAYER M4 ;
        RECT  0 55.152 0.084 55.176 ;
    END
  END prev_data[12]
  PIN prev_data[130]
    DIRECTION INPUT ;
    USE SIGNAL ;
    PORT
      LAYER M4 ;
        RECT  0 63.408 0.084 63.432 ;
    END
  END prev_data[130]
  PIN prev_data[131]
    DIRECTION INPUT ;
    USE SIGNAL ;
    PORT
      LAYER M4 ;
        RECT  0 63.504 0.084 63.528 ;
    END
  END prev_data[131]
  PIN prev_data[132]
    DIRECTION INPUT ;
    USE SIGNAL ;
    PORT
      LAYER M4 ;
        RECT  0 63.6 0.084 63.624 ;
    END
  END prev_data[132]
  PIN prev_data[133]
    DIRECTION INPUT ;
    USE SIGNAL ;
    PORT
      LAYER M4 ;
        RECT  0 63.696 0.084 63.72 ;
    END
  END prev_data[133]
  PIN prev_data[134]
    DIRECTION INPUT ;
    USE SIGNAL ;
    PORT
      LAYER M4 ;
        RECT  0 63.792 0.084 63.816 ;
    END
  END prev_data[134]
  PIN prev_data[135]
    DIRECTION INPUT ;
    USE SIGNAL ;
    PORT
      LAYER M4 ;
        RECT  0 63.888 0.084 63.912 ;
    END
  END prev_data[135]
  PIN prev_data[136]
    DIRECTION INPUT ;
    USE SIGNAL ;
    PORT
      LAYER M4 ;
        RECT  0 63.984 0.084 64.008 ;
    END
  END prev_data[136]
  PIN prev_data[137]
    DIRECTION INPUT ;
    USE SIGNAL ;
    PORT
      LAYER M4 ;
        RECT  0 64.08 0.084 64.104 ;
    END
  END prev_data[137]
  PIN prev_data[138]
    DIRECTION INPUT ;
    USE SIGNAL ;
    PORT
      LAYER M4 ;
        RECT  0 64.176 0.084 64.2 ;
    END
  END prev_data[138]
  PIN prev_data[139]
    DIRECTION INPUT ;
    USE SIGNAL ;
    PORT
      LAYER M4 ;
        RECT  0 64.272 0.084 64.296 ;
    END
  END prev_data[139]
  PIN prev_data[13]
    DIRECTION INPUT ;
    USE SIGNAL ;
    PORT
      LAYER M4 ;
        RECT  0 55.248 0.084 55.272 ;
    END
  END prev_data[13]
  PIN prev_data[140]
    DIRECTION INPUT ;
    USE SIGNAL ;
    PORT
      LAYER M4 ;
        RECT  0 64.368 0.084 64.392 ;
    END
  END prev_data[140]
  PIN prev_data[141]
    DIRECTION INPUT ;
    USE SIGNAL ;
    PORT
      LAYER M4 ;
        RECT  0 64.464 0.084 64.488 ;
    END
  END prev_data[141]
  PIN prev_data[142]
    DIRECTION INPUT ;
    USE SIGNAL ;
    PORT
      LAYER M4 ;
        RECT  0 64.56 0.084 64.584 ;
    END
  END prev_data[142]
  PIN prev_data[143]
    DIRECTION INPUT ;
    USE SIGNAL ;
    PORT
      LAYER M4 ;
        RECT  0 64.656 0.084 64.68 ;
    END
  END prev_data[143]
  PIN prev_data[144]
    DIRECTION INPUT ;
    USE SIGNAL ;
    PORT
      LAYER M4 ;
        RECT  0 64.752 0.084 64.776 ;
    END
  END prev_data[144]
  PIN prev_data[145]
    DIRECTION INPUT ;
    USE SIGNAL ;
    PORT
      LAYER M4 ;
        RECT  0 64.848 0.084 64.872 ;
    END
  END prev_data[145]
  PIN prev_data[146]
    DIRECTION INPUT ;
    USE SIGNAL ;
    PORT
      LAYER M4 ;
        RECT  0 64.944 0.084 64.968 ;
    END
  END prev_data[146]
  PIN prev_data[147]
    DIRECTION INPUT ;
    USE SIGNAL ;
    PORT
      LAYER M4 ;
        RECT  0 65.04 0.084 65.064 ;
    END
  END prev_data[147]
  PIN prev_data[148]
    DIRECTION INPUT ;
    USE SIGNAL ;
    PORT
      LAYER M4 ;
        RECT  0 78.192 0.084 78.216 ;
    END
  END prev_data[148]
  PIN prev_data[149]
    DIRECTION INPUT ;
    USE SIGNAL ;
    PORT
      LAYER M4 ;
        RECT  0 78.288 0.084 78.312 ;
    END
  END prev_data[149]
  PIN prev_data[14]
    DIRECTION INPUT ;
    USE SIGNAL ;
    PORT
      LAYER M4 ;
        RECT  0 55.344 0.084 55.368 ;
    END
  END prev_data[14]
  PIN prev_data[150]
    DIRECTION INPUT ;
    USE SIGNAL ;
    PORT
      LAYER M4 ;
        RECT  0 78.384 0.084 78.408 ;
    END
  END prev_data[150]
  PIN prev_data[151]
    DIRECTION INPUT ;
    USE SIGNAL ;
    PORT
      LAYER M4 ;
        RECT  0 78.48 0.084 78.504 ;
    END
  END prev_data[151]
  PIN prev_data[152]
    DIRECTION INPUT ;
    USE SIGNAL ;
    PORT
      LAYER M4 ;
        RECT  0 78.576 0.084 78.6 ;
    END
  END prev_data[152]
  PIN prev_data[153]
    DIRECTION INPUT ;
    USE SIGNAL ;
    PORT
      LAYER M4 ;
        RECT  0 78.672 0.084 78.696 ;
    END
  END prev_data[153]
  PIN prev_data[154]
    DIRECTION INPUT ;
    USE SIGNAL ;
    PORT
      LAYER M4 ;
        RECT  0 78.768 0.084 78.792 ;
    END
  END prev_data[154]
  PIN prev_data[155]
    DIRECTION INPUT ;
    USE SIGNAL ;
    PORT
      LAYER M4 ;
        RECT  0 78.864 0.084 78.888 ;
    END
  END prev_data[155]
  PIN prev_data[156]
    DIRECTION INPUT ;
    USE SIGNAL ;
    PORT
      LAYER M4 ;
        RECT  0 78.96 0.084 78.984 ;
    END
  END prev_data[156]
  PIN prev_data[157]
    DIRECTION INPUT ;
    USE SIGNAL ;
    PORT
      LAYER M4 ;
        RECT  0 79.056 0.084 79.08 ;
    END
  END prev_data[157]
  PIN prev_data[158]
    DIRECTION INPUT ;
    USE SIGNAL ;
    PORT
      LAYER M4 ;
        RECT  0 79.152 0.084 79.176 ;
    END
  END prev_data[158]
  PIN prev_data[159]
    DIRECTION INPUT ;
    USE SIGNAL ;
    PORT
      LAYER M4 ;
        RECT  0 79.248 0.084 79.272 ;
    END
  END prev_data[159]
  PIN prev_data[15]
    DIRECTION INPUT ;
    USE SIGNAL ;
    PORT
      LAYER M4 ;
        RECT  0 55.44 0.084 55.464 ;
    END
  END prev_data[15]
  PIN prev_data[160]
    DIRECTION INPUT ;
    USE SIGNAL ;
    PORT
      LAYER M4 ;
        RECT  0 79.344 0.084 79.368 ;
    END
  END prev_data[160]
  PIN prev_data[161]
    DIRECTION INPUT ;
    USE SIGNAL ;
    PORT
      LAYER M4 ;
        RECT  0 79.44 0.084 79.464 ;
    END
  END prev_data[161]
  PIN prev_data[162]
    DIRECTION INPUT ;
    USE SIGNAL ;
    PORT
      LAYER M4 ;
        RECT  0 79.536 0.084 79.56 ;
    END
  END prev_data[162]
  PIN prev_data[163]
    DIRECTION INPUT ;
    USE SIGNAL ;
    PORT
      LAYER M4 ;
        RECT  0 79.632 0.084 79.656 ;
    END
  END prev_data[163]
  PIN prev_data[164]
    DIRECTION INPUT ;
    USE SIGNAL ;
    PORT
      LAYER M4 ;
        RECT  0 79.728 0.084 79.752 ;
    END
  END prev_data[164]
  PIN prev_data[165]
    DIRECTION INPUT ;
    USE SIGNAL ;
    PORT
      LAYER M4 ;
        RECT  0 79.824 0.084 79.848 ;
    END
  END prev_data[165]
  PIN prev_data[166]
    DIRECTION INPUT ;
    USE SIGNAL ;
    PORT
      LAYER M4 ;
        RECT  0 79.92 0.084 79.944 ;
    END
  END prev_data[166]
  PIN prev_data[167]
    DIRECTION INPUT ;
    USE SIGNAL ;
    PORT
      LAYER M4 ;
        RECT  0 80.016 0.084 80.04 ;
    END
  END prev_data[167]
  PIN prev_data[168]
    DIRECTION INPUT ;
    USE SIGNAL ;
    PORT
      LAYER M4 ;
        RECT  0 80.112 0.084 80.136 ;
    END
  END prev_data[168]
  PIN prev_data[169]
    DIRECTION INPUT ;
    USE SIGNAL ;
    PORT
      LAYER M4 ;
        RECT  0 80.208 0.084 80.232 ;
    END
  END prev_data[169]
  PIN prev_data[16]
    DIRECTION INPUT ;
    USE SIGNAL ;
    PORT
      LAYER M4 ;
        RECT  0 55.536 0.084 55.56 ;
    END
  END prev_data[16]
  PIN prev_data[170]
    DIRECTION INPUT ;
    USE SIGNAL ;
    PORT
      LAYER M4 ;
        RECT  0 80.304 0.084 80.328 ;
    END
  END prev_data[170]
  PIN prev_data[171]
    DIRECTION INPUT ;
    USE SIGNAL ;
    PORT
      LAYER M4 ;
        RECT  0 80.4 0.084 80.424 ;
    END
  END prev_data[171]
  PIN prev_data[172]
    DIRECTION INPUT ;
    USE SIGNAL ;
    PORT
      LAYER M4 ;
        RECT  0 80.496 0.084 80.52 ;
    END
  END prev_data[172]
  PIN prev_data[173]
    DIRECTION INPUT ;
    USE SIGNAL ;
    PORT
      LAYER M4 ;
        RECT  0 80.592 0.084 80.616 ;
    END
  END prev_data[173]
  PIN prev_data[174]
    DIRECTION INPUT ;
    USE SIGNAL ;
    PORT
      LAYER M4 ;
        RECT  0 80.688 0.084 80.712 ;
    END
  END prev_data[174]
  PIN prev_data[175]
    DIRECTION INPUT ;
    USE SIGNAL ;
    PORT
      LAYER M4 ;
        RECT  0 80.784 0.084 80.808 ;
    END
  END prev_data[175]
  PIN prev_data[176]
    DIRECTION INPUT ;
    USE SIGNAL ;
    PORT
      LAYER M4 ;
        RECT  0 80.88 0.084 80.904 ;
    END
  END prev_data[176]
  PIN prev_data[177]
    DIRECTION INPUT ;
    USE SIGNAL ;
    PORT
      LAYER M4 ;
        RECT  0 80.976 0.084 81 ;
    END
  END prev_data[177]
  PIN prev_data[178]
    DIRECTION INPUT ;
    USE SIGNAL ;
    PORT
      LAYER M4 ;
        RECT  0 81.072 0.084 81.096 ;
    END
  END prev_data[178]
  PIN prev_data[179]
    DIRECTION INPUT ;
    USE SIGNAL ;
    PORT
      LAYER M4 ;
        RECT  0 81.168 0.084 81.192 ;
    END
  END prev_data[179]
  PIN prev_data[17]
    DIRECTION INPUT ;
    USE SIGNAL ;
    PORT
      LAYER M4 ;
        RECT  0 55.632 0.084 55.656 ;
    END
  END prev_data[17]
  PIN prev_data[180]
    DIRECTION INPUT ;
    USE SIGNAL ;
    PORT
      LAYER M4 ;
        RECT  0 81.264 0.084 81.288 ;
    END
  END prev_data[180]
  PIN prev_data[181]
    DIRECTION INPUT ;
    USE SIGNAL ;
    PORT
      LAYER M4 ;
        RECT  0 81.36 0.084 81.384 ;
    END
  END prev_data[181]
  PIN prev_data[182]
    DIRECTION INPUT ;
    USE SIGNAL ;
    PORT
      LAYER M4 ;
        RECT  0 81.456 0.084 81.48 ;
    END
  END prev_data[182]
  PIN prev_data[183]
    DIRECTION INPUT ;
    USE SIGNAL ;
    PORT
      LAYER M4 ;
        RECT  0 81.552 0.084 81.576 ;
    END
  END prev_data[183]
  PIN prev_data[184]
    DIRECTION INPUT ;
    USE SIGNAL ;
    PORT
      LAYER M4 ;
        RECT  0 81.648 0.084 81.672 ;
    END
  END prev_data[184]
  PIN prev_data[185]
    DIRECTION INPUT ;
    USE SIGNAL ;
    PORT
      LAYER M4 ;
        RECT  0 81.744 0.084 81.768 ;
    END
  END prev_data[185]
  PIN prev_data[186]
    DIRECTION INPUT ;
    USE SIGNAL ;
    PORT
      LAYER M4 ;
        RECT  0 81.84 0.084 81.864 ;
    END
  END prev_data[186]
  PIN prev_data[187]
    DIRECTION INPUT ;
    USE SIGNAL ;
    PORT
      LAYER M4 ;
        RECT  0 81.936 0.084 81.96 ;
    END
  END prev_data[187]
  PIN prev_data[188]
    DIRECTION INPUT ;
    USE SIGNAL ;
    PORT
      LAYER M4 ;
        RECT  0 82.032 0.084 82.056 ;
    END
  END prev_data[188]
  PIN prev_data[189]
    DIRECTION INPUT ;
    USE SIGNAL ;
    PORT
      LAYER M4 ;
        RECT  0 82.128 0.084 82.152 ;
    END
  END prev_data[189]
  PIN prev_data[18]
    DIRECTION INPUT ;
    USE SIGNAL ;
    PORT
      LAYER M4 ;
        RECT  0 55.728 0.084 55.752 ;
    END
  END prev_data[18]
  PIN prev_data[190]
    DIRECTION INPUT ;
    USE SIGNAL ;
    PORT
      LAYER M4 ;
        RECT  0 82.224 0.084 82.248 ;
    END
  END prev_data[190]
  PIN prev_data[191]
    DIRECTION INPUT ;
    USE SIGNAL ;
    PORT
      LAYER M4 ;
        RECT  0 82.32 0.084 82.344 ;
    END
  END prev_data[191]
  PIN prev_data[192]
    DIRECTION INPUT ;
    USE SIGNAL ;
    PORT
      LAYER M4 ;
        RECT  0 82.416 0.084 82.44 ;
    END
  END prev_data[192]
  PIN prev_data[193]
    DIRECTION INPUT ;
    USE SIGNAL ;
    PORT
      LAYER M4 ;
        RECT  0 82.512 0.084 82.536 ;
    END
  END prev_data[193]
  PIN prev_data[194]
    DIRECTION INPUT ;
    USE SIGNAL ;
    PORT
      LAYER M4 ;
        RECT  0 82.608 0.084 82.632 ;
    END
  END prev_data[194]
  PIN prev_data[195]
    DIRECTION INPUT ;
    USE SIGNAL ;
    PORT
      LAYER M4 ;
        RECT  0 82.704 0.084 82.728 ;
    END
  END prev_data[195]
  PIN prev_data[196]
    DIRECTION INPUT ;
    USE SIGNAL ;
    PORT
      LAYER M4 ;
        RECT  0 82.8 0.084 82.824 ;
    END
  END prev_data[196]
  PIN prev_data[197]
    DIRECTION INPUT ;
    USE SIGNAL ;
    PORT
      LAYER M4 ;
        RECT  0 82.896 0.084 82.92 ;
    END
  END prev_data[197]
  PIN prev_data[198]
    DIRECTION INPUT ;
    USE SIGNAL ;
    PORT
      LAYER M4 ;
        RECT  0 82.992 0.084 83.016 ;
    END
  END prev_data[198]
  PIN prev_data[199]
    DIRECTION INPUT ;
    USE SIGNAL ;
    PORT
      LAYER M4 ;
        RECT  0 83.088 0.084 83.112 ;
    END
  END prev_data[199]
  PIN prev_data[19]
    DIRECTION INPUT ;
    USE SIGNAL ;
    PORT
      LAYER M4 ;
        RECT  0 55.824 0.084 55.848 ;
    END
  END prev_data[19]
  PIN prev_data[1]
    DIRECTION INPUT ;
    USE SIGNAL ;
    PORT
      LAYER M4 ;
        RECT  0 54.096 0.084 54.12 ;
    END
  END prev_data[1]
  PIN prev_data[200]
    DIRECTION INPUT ;
    USE SIGNAL ;
    PORT
      LAYER M4 ;
        RECT  0 83.184 0.084 83.208 ;
    END
  END prev_data[200]
  PIN prev_data[201]
    DIRECTION INPUT ;
    USE SIGNAL ;
    PORT
      LAYER M4 ;
        RECT  0 83.28 0.084 83.304 ;
    END
  END prev_data[201]
  PIN prev_data[202]
    DIRECTION INPUT ;
    USE SIGNAL ;
    PORT
      LAYER M4 ;
        RECT  0 83.376 0.084 83.4 ;
    END
  END prev_data[202]
  PIN prev_data[203]
    DIRECTION INPUT ;
    USE SIGNAL ;
    PORT
      LAYER M4 ;
        RECT  0 83.472 0.084 83.496 ;
    END
  END prev_data[203]
  PIN prev_data[204]
    DIRECTION INPUT ;
    USE SIGNAL ;
    PORT
      LAYER M4 ;
        RECT  0 83.568 0.084 83.592 ;
    END
  END prev_data[204]
  PIN prev_data[205]
    DIRECTION INPUT ;
    USE SIGNAL ;
    PORT
      LAYER M4 ;
        RECT  0 83.664 0.084 83.688 ;
    END
  END prev_data[205]
  PIN prev_data[206]
    DIRECTION INPUT ;
    USE SIGNAL ;
    PORT
      LAYER M4 ;
        RECT  0 83.76 0.084 83.784 ;
    END
  END prev_data[206]
  PIN prev_data[207]
    DIRECTION INPUT ;
    USE SIGNAL ;
    PORT
      LAYER M4 ;
        RECT  0 83.856 0.084 83.88 ;
    END
  END prev_data[207]
  PIN prev_data[208]
    DIRECTION INPUT ;
    USE SIGNAL ;
    PORT
      LAYER M4 ;
        RECT  0 83.952 0.084 83.976 ;
    END
  END prev_data[208]
  PIN prev_data[209]
    DIRECTION INPUT ;
    USE SIGNAL ;
    PORT
      LAYER M4 ;
        RECT  0 84.048 0.084 84.072 ;
    END
  END prev_data[209]
  PIN prev_data[20]
    DIRECTION INPUT ;
    USE SIGNAL ;
    PORT
      LAYER M4 ;
        RECT  0 55.92 0.084 55.944 ;
    END
  END prev_data[20]
  PIN prev_data[210]
    DIRECTION INPUT ;
    USE SIGNAL ;
    PORT
      LAYER M4 ;
        RECT  0 84.144 0.084 84.168 ;
    END
  END prev_data[210]
  PIN prev_data[211]
    DIRECTION INPUT ;
    USE SIGNAL ;
    PORT
      LAYER M4 ;
        RECT  0 84.24 0.084 84.264 ;
    END
  END prev_data[211]
  PIN prev_data[212]
    DIRECTION INPUT ;
    USE SIGNAL ;
    PORT
      LAYER M4 ;
        RECT  0 72.048 0.084 72.072 ;
    END
  END prev_data[212]
  PIN prev_data[213]
    DIRECTION INPUT ;
    USE SIGNAL ;
    PORT
      LAYER M4 ;
        RECT  0 72.144 0.084 72.168 ;
    END
  END prev_data[213]
  PIN prev_data[214]
    DIRECTION INPUT ;
    USE SIGNAL ;
    PORT
      LAYER M4 ;
        RECT  0 72.24 0.084 72.264 ;
    END
  END prev_data[214]
  PIN prev_data[215]
    DIRECTION INPUT ;
    USE SIGNAL ;
    PORT
      LAYER M4 ;
        RECT  0 72.336 0.084 72.36 ;
    END
  END prev_data[215]
  PIN prev_data[216]
    DIRECTION INPUT ;
    USE SIGNAL ;
    PORT
      LAYER M4 ;
        RECT  0 72.432 0.084 72.456 ;
    END
  END prev_data[216]
  PIN prev_data[217]
    DIRECTION INPUT ;
    USE SIGNAL ;
    PORT
      LAYER M4 ;
        RECT  0 72.528 0.084 72.552 ;
    END
  END prev_data[217]
  PIN prev_data[218]
    DIRECTION INPUT ;
    USE SIGNAL ;
    PORT
      LAYER M4 ;
        RECT  0 72.624 0.084 72.648 ;
    END
  END prev_data[218]
  PIN prev_data[219]
    DIRECTION INPUT ;
    USE SIGNAL ;
    PORT
      LAYER M4 ;
        RECT  0 72.72 0.084 72.744 ;
    END
  END prev_data[219]
  PIN prev_data[21]
    DIRECTION INPUT ;
    USE SIGNAL ;
    PORT
      LAYER M4 ;
        RECT  0 56.016 0.084 56.04 ;
    END
  END prev_data[21]
  PIN prev_data[220]
    DIRECTION INPUT ;
    USE SIGNAL ;
    PORT
      LAYER M4 ;
        RECT  0 72.816 0.084 72.84 ;
    END
  END prev_data[220]
  PIN prev_data[221]
    DIRECTION INPUT ;
    USE SIGNAL ;
    PORT
      LAYER M4 ;
        RECT  0 72.912 0.084 72.936 ;
    END
  END prev_data[221]
  PIN prev_data[222]
    DIRECTION INPUT ;
    USE SIGNAL ;
    PORT
      LAYER M4 ;
        RECT  0 73.008 0.084 73.032 ;
    END
  END prev_data[222]
  PIN prev_data[223]
    DIRECTION INPUT ;
    USE SIGNAL ;
    PORT
      LAYER M4 ;
        RECT  0 73.104 0.084 73.128 ;
    END
  END prev_data[223]
  PIN prev_data[224]
    DIRECTION INPUT ;
    USE SIGNAL ;
    PORT
      LAYER M4 ;
        RECT  0 73.2 0.084 73.224 ;
    END
  END prev_data[224]
  PIN prev_data[225]
    DIRECTION INPUT ;
    USE SIGNAL ;
    PORT
      LAYER M4 ;
        RECT  0 73.296 0.084 73.32 ;
    END
  END prev_data[225]
  PIN prev_data[226]
    DIRECTION INPUT ;
    USE SIGNAL ;
    PORT
      LAYER M4 ;
        RECT  0 73.392 0.084 73.416 ;
    END
  END prev_data[226]
  PIN prev_data[227]
    DIRECTION INPUT ;
    USE SIGNAL ;
    PORT
      LAYER M4 ;
        RECT  0 73.488 0.084 73.512 ;
    END
  END prev_data[227]
  PIN prev_data[228]
    DIRECTION INPUT ;
    USE SIGNAL ;
    PORT
      LAYER M4 ;
        RECT  0 73.584 0.084 73.608 ;
    END
  END prev_data[228]
  PIN prev_data[229]
    DIRECTION INPUT ;
    USE SIGNAL ;
    PORT
      LAYER M4 ;
        RECT  0 73.68 0.084 73.704 ;
    END
  END prev_data[229]
  PIN prev_data[22]
    DIRECTION INPUT ;
    USE SIGNAL ;
    PORT
      LAYER M4 ;
        RECT  0 56.112 0.084 56.136 ;
    END
  END prev_data[22]
  PIN prev_data[230]
    DIRECTION INPUT ;
    USE SIGNAL ;
    PORT
      LAYER M4 ;
        RECT  0 73.776 0.084 73.8 ;
    END
  END prev_data[230]
  PIN prev_data[231]
    DIRECTION INPUT ;
    USE SIGNAL ;
    PORT
      LAYER M4 ;
        RECT  0 73.872 0.084 73.896 ;
    END
  END prev_data[231]
  PIN prev_data[232]
    DIRECTION INPUT ;
    USE SIGNAL ;
    PORT
      LAYER M4 ;
        RECT  0 73.968 0.084 73.992 ;
    END
  END prev_data[232]
  PIN prev_data[233]
    DIRECTION INPUT ;
    USE SIGNAL ;
    PORT
      LAYER M4 ;
        RECT  0 74.064 0.084 74.088 ;
    END
  END prev_data[233]
  PIN prev_data[234]
    DIRECTION INPUT ;
    USE SIGNAL ;
    PORT
      LAYER M4 ;
        RECT  0 74.16 0.084 74.184 ;
    END
  END prev_data[234]
  PIN prev_data[235]
    DIRECTION INPUT ;
    USE SIGNAL ;
    PORT
      LAYER M4 ;
        RECT  0 74.256 0.084 74.28 ;
    END
  END prev_data[235]
  PIN prev_data[236]
    DIRECTION INPUT ;
    USE SIGNAL ;
    PORT
      LAYER M4 ;
        RECT  0 74.352 0.084 74.376 ;
    END
  END prev_data[236]
  PIN prev_data[237]
    DIRECTION INPUT ;
    USE SIGNAL ;
    PORT
      LAYER M4 ;
        RECT  0 74.448 0.084 74.472 ;
    END
  END prev_data[237]
  PIN prev_data[238]
    DIRECTION INPUT ;
    USE SIGNAL ;
    PORT
      LAYER M4 ;
        RECT  0 74.544 0.084 74.568 ;
    END
  END prev_data[238]
  PIN prev_data[239]
    DIRECTION INPUT ;
    USE SIGNAL ;
    PORT
      LAYER M4 ;
        RECT  0 74.64 0.084 74.664 ;
    END
  END prev_data[239]
  PIN prev_data[23]
    DIRECTION INPUT ;
    USE SIGNAL ;
    PORT
      LAYER M4 ;
        RECT  0 56.208 0.084 56.232 ;
    END
  END prev_data[23]
  PIN prev_data[240]
    DIRECTION INPUT ;
    USE SIGNAL ;
    PORT
      LAYER M4 ;
        RECT  0 74.736 0.084 74.76 ;
    END
  END prev_data[240]
  PIN prev_data[241]
    DIRECTION INPUT ;
    USE SIGNAL ;
    PORT
      LAYER M4 ;
        RECT  0 74.832 0.084 74.856 ;
    END
  END prev_data[241]
  PIN prev_data[242]
    DIRECTION INPUT ;
    USE SIGNAL ;
    PORT
      LAYER M4 ;
        RECT  0 74.928 0.084 74.952 ;
    END
  END prev_data[242]
  PIN prev_data[243]
    DIRECTION INPUT ;
    USE SIGNAL ;
    PORT
      LAYER M4 ;
        RECT  0 75.024 0.084 75.048 ;
    END
  END prev_data[243]
  PIN prev_data[244]
    DIRECTION INPUT ;
    USE SIGNAL ;
    PORT
      LAYER M4 ;
        RECT  0 75.12 0.084 75.144 ;
    END
  END prev_data[244]
  PIN prev_data[245]
    DIRECTION INPUT ;
    USE SIGNAL ;
    PORT
      LAYER M4 ;
        RECT  0 75.216 0.084 75.24 ;
    END
  END prev_data[245]
  PIN prev_data[246]
    DIRECTION INPUT ;
    USE SIGNAL ;
    PORT
      LAYER M4 ;
        RECT  0 75.312 0.084 75.336 ;
    END
  END prev_data[246]
  PIN prev_data[247]
    DIRECTION INPUT ;
    USE SIGNAL ;
    PORT
      LAYER M4 ;
        RECT  0 75.408 0.084 75.432 ;
    END
  END prev_data[247]
  PIN prev_data[248]
    DIRECTION INPUT ;
    USE SIGNAL ;
    PORT
      LAYER M4 ;
        RECT  0 75.504 0.084 75.528 ;
    END
  END prev_data[248]
  PIN prev_data[249]
    DIRECTION INPUT ;
    USE SIGNAL ;
    PORT
      LAYER M4 ;
        RECT  0 75.6 0.084 75.624 ;
    END
  END prev_data[249]
  PIN prev_data[24]
    DIRECTION INPUT ;
    USE SIGNAL ;
    PORT
      LAYER M4 ;
        RECT  0 56.304 0.084 56.328 ;
    END
  END prev_data[24]
  PIN prev_data[250]
    DIRECTION INPUT ;
    USE SIGNAL ;
    PORT
      LAYER M4 ;
        RECT  0 75.696 0.084 75.72 ;
    END
  END prev_data[250]
  PIN prev_data[251]
    DIRECTION INPUT ;
    USE SIGNAL ;
    PORT
      LAYER M4 ;
        RECT  0 75.792 0.084 75.816 ;
    END
  END prev_data[251]
  PIN prev_data[252]
    DIRECTION INPUT ;
    USE SIGNAL ;
    PORT
      LAYER M4 ;
        RECT  0 75.888 0.084 75.912 ;
    END
  END prev_data[252]
  PIN prev_data[253]
    DIRECTION INPUT ;
    USE SIGNAL ;
    PORT
      LAYER M4 ;
        RECT  0 75.984 0.084 76.008 ;
    END
  END prev_data[253]
  PIN prev_data[254]
    DIRECTION INPUT ;
    USE SIGNAL ;
    PORT
      LAYER M4 ;
        RECT  0 76.08 0.084 76.104 ;
    END
  END prev_data[254]
  PIN prev_data[255]
    DIRECTION INPUT ;
    USE SIGNAL ;
    PORT
      LAYER M4 ;
        RECT  0 76.176 0.084 76.2 ;
    END
  END prev_data[255]
  PIN prev_data[25]
    DIRECTION INPUT ;
    USE SIGNAL ;
    PORT
      LAYER M4 ;
        RECT  0 56.4 0.084 56.424 ;
    END
  END prev_data[25]
  PIN prev_data[26]
    DIRECTION INPUT ;
    USE SIGNAL ;
    PORT
      LAYER M4 ;
        RECT  0 56.496 0.084 56.52 ;
    END
  END prev_data[26]
  PIN prev_data[27]
    DIRECTION INPUT ;
    USE SIGNAL ;
    PORT
      LAYER M4 ;
        RECT  0 56.592 0.084 56.616 ;
    END
  END prev_data[27]
  PIN prev_data[28]
    DIRECTION INPUT ;
    USE SIGNAL ;
    PORT
      LAYER M4 ;
        RECT  0 56.688 0.084 56.712 ;
    END
  END prev_data[28]
  PIN prev_data[29]
    DIRECTION INPUT ;
    USE SIGNAL ;
    PORT
      LAYER M4 ;
        RECT  0 56.784 0.084 56.808 ;
    END
  END prev_data[29]
  PIN prev_data[2]
    DIRECTION INPUT ;
    USE SIGNAL ;
    PORT
      LAYER M4 ;
        RECT  0 54.192 0.084 54.216 ;
    END
  END prev_data[2]
  PIN prev_data[30]
    DIRECTION INPUT ;
    USE SIGNAL ;
    PORT
      LAYER M4 ;
        RECT  0 56.88 0.084 56.904 ;
    END
  END prev_data[30]
  PIN prev_data[31]
    DIRECTION INPUT ;
    USE SIGNAL ;
    PORT
      LAYER M4 ;
        RECT  0 56.976 0.084 57 ;
    END
  END prev_data[31]
  PIN prev_data[32]
    DIRECTION INPUT ;
    USE SIGNAL ;
    PORT
      LAYER M4 ;
        RECT  0 57.072 0.084 57.096 ;
    END
  END prev_data[32]
  PIN prev_data[33]
    DIRECTION INPUT ;
    USE SIGNAL ;
    PORT
      LAYER M4 ;
        RECT  0 57.168 0.084 57.192 ;
    END
  END prev_data[33]
  PIN prev_data[34]
    DIRECTION INPUT ;
    USE SIGNAL ;
    PORT
      LAYER M4 ;
        RECT  0 57.264 0.084 57.288 ;
    END
  END prev_data[34]
  PIN prev_data[35]
    DIRECTION INPUT ;
    USE SIGNAL ;
    PORT
      LAYER M4 ;
        RECT  0 57.36 0.084 57.384 ;
    END
  END prev_data[35]
  PIN prev_data[36]
    DIRECTION INPUT ;
    USE SIGNAL ;
    PORT
      LAYER M4 ;
        RECT  0 57.456 0.084 57.48 ;
    END
  END prev_data[36]
  PIN prev_data[37]
    DIRECTION INPUT ;
    USE SIGNAL ;
    PORT
      LAYER M4 ;
        RECT  0 57.552 0.084 57.576 ;
    END
  END prev_data[37]
  PIN prev_data[38]
    DIRECTION INPUT ;
    USE SIGNAL ;
    PORT
      LAYER M4 ;
        RECT  0 57.648 0.084 57.672 ;
    END
  END prev_data[38]
  PIN prev_data[39]
    DIRECTION INPUT ;
    USE SIGNAL ;
    PORT
      LAYER M4 ;
        RECT  0 57.744 0.084 57.768 ;
    END
  END prev_data[39]
  PIN prev_data[3]
    DIRECTION INPUT ;
    USE SIGNAL ;
    PORT
      LAYER M4 ;
        RECT  0 54.288 0.084 54.312 ;
    END
  END prev_data[3]
  PIN prev_data[40]
    DIRECTION INPUT ;
    USE SIGNAL ;
    PORT
      LAYER M4 ;
        RECT  0 57.84 0.084 57.864 ;
    END
  END prev_data[40]
  PIN prev_data[41]
    DIRECTION INPUT ;
    USE SIGNAL ;
    PORT
      LAYER M4 ;
        RECT  0 57.936 0.084 57.96 ;
    END
  END prev_data[41]
  PIN prev_data[42]
    DIRECTION INPUT ;
    USE SIGNAL ;
    PORT
      LAYER M4 ;
        RECT  0 58.032 0.084 58.056 ;
    END
  END prev_data[42]
  PIN prev_data[43]
    DIRECTION INPUT ;
    USE SIGNAL ;
    PORT
      LAYER M4 ;
        RECT  0 58.128 0.084 58.152 ;
    END
  END prev_data[43]
  PIN prev_data[44]
    DIRECTION INPUT ;
    USE SIGNAL ;
    PORT
      LAYER M4 ;
        RECT  0 58.224 0.084 58.248 ;
    END
  END prev_data[44]
  PIN prev_data[45]
    DIRECTION INPUT ;
    USE SIGNAL ;
    PORT
      LAYER M4 ;
        RECT  0 58.32 0.084 58.344 ;
    END
  END prev_data[45]
  PIN prev_data[46]
    DIRECTION INPUT ;
    USE SIGNAL ;
    PORT
      LAYER M4 ;
        RECT  0 58.416 0.084 58.44 ;
    END
  END prev_data[46]
  PIN prev_data[47]
    DIRECTION INPUT ;
    USE SIGNAL ;
    PORT
      LAYER M4 ;
        RECT  0 58.512 0.084 58.536 ;
    END
  END prev_data[47]
  PIN prev_data[48]
    DIRECTION INPUT ;
    USE SIGNAL ;
    PORT
      LAYER M4 ;
        RECT  0 58.608 0.084 58.632 ;
    END
  END prev_data[48]
  PIN prev_data[49]
    DIRECTION INPUT ;
    USE SIGNAL ;
    PORT
      LAYER M4 ;
        RECT  0 58.704 0.084 58.728 ;
    END
  END prev_data[49]
  PIN prev_data[4]
    DIRECTION INPUT ;
    USE SIGNAL ;
    PORT
      LAYER M4 ;
        RECT  0 54.384 0.084 54.408 ;
    END
  END prev_data[4]
  PIN prev_data[50]
    DIRECTION INPUT ;
    USE SIGNAL ;
    PORT
      LAYER M4 ;
        RECT  0 58.8 0.084 58.824 ;
    END
  END prev_data[50]
  PIN prev_data[51]
    DIRECTION INPUT ;
    USE SIGNAL ;
    PORT
      LAYER M4 ;
        RECT  0 58.896 0.084 58.92 ;
    END
  END prev_data[51]
  PIN prev_data[52]
    DIRECTION INPUT ;
    USE SIGNAL ;
    PORT
      LAYER M4 ;
        RECT  0 68.208 0.084 68.232 ;
    END
  END prev_data[52]
  PIN prev_data[53]
    DIRECTION INPUT ;
    USE SIGNAL ;
    PORT
      LAYER M4 ;
        RECT  0 68.304 0.084 68.328 ;
    END
  END prev_data[53]
  PIN prev_data[54]
    DIRECTION INPUT ;
    USE SIGNAL ;
    PORT
      LAYER M4 ;
        RECT  0 68.4 0.084 68.424 ;
    END
  END prev_data[54]
  PIN prev_data[55]
    DIRECTION INPUT ;
    USE SIGNAL ;
    PORT
      LAYER M4 ;
        RECT  0 68.496 0.084 68.52 ;
    END
  END prev_data[55]
  PIN prev_data[56]
    DIRECTION INPUT ;
    USE SIGNAL ;
    PORT
      LAYER M4 ;
        RECT  0 68.592 0.084 68.616 ;
    END
  END prev_data[56]
  PIN prev_data[57]
    DIRECTION INPUT ;
    USE SIGNAL ;
    PORT
      LAYER M4 ;
        RECT  0 68.688 0.084 68.712 ;
    END
  END prev_data[57]
  PIN prev_data[58]
    DIRECTION INPUT ;
    USE SIGNAL ;
    PORT
      LAYER M4 ;
        RECT  0 68.784 0.084 68.808 ;
    END
  END prev_data[58]
  PIN prev_data[59]
    DIRECTION INPUT ;
    USE SIGNAL ;
    PORT
      LAYER M4 ;
        RECT  0 68.88 0.084 68.904 ;
    END
  END prev_data[59]
  PIN prev_data[5]
    DIRECTION INPUT ;
    USE SIGNAL ;
    PORT
      LAYER M4 ;
        RECT  0 54.48 0.084 54.504 ;
    END
  END prev_data[5]
  PIN prev_data[60]
    DIRECTION INPUT ;
    USE SIGNAL ;
    PORT
      LAYER M4 ;
        RECT  0 68.976 0.084 69 ;
    END
  END prev_data[60]
  PIN prev_data[61]
    DIRECTION INPUT ;
    USE SIGNAL ;
    PORT
      LAYER M4 ;
        RECT  0 69.072 0.084 69.096 ;
    END
  END prev_data[61]
  PIN prev_data[62]
    DIRECTION INPUT ;
    USE SIGNAL ;
    PORT
      LAYER M4 ;
        RECT  0 69.168 0.084 69.192 ;
    END
  END prev_data[62]
  PIN prev_data[63]
    DIRECTION INPUT ;
    USE SIGNAL ;
    PORT
      LAYER M4 ;
        RECT  0 69.264 0.084 69.288 ;
    END
  END prev_data[63]
  PIN prev_data[64]
    DIRECTION INPUT ;
    USE SIGNAL ;
    PORT
      LAYER M4 ;
        RECT  0 69.36 0.084 69.384 ;
    END
  END prev_data[64]
  PIN prev_data[65]
    DIRECTION INPUT ;
    USE SIGNAL ;
    PORT
      LAYER M4 ;
        RECT  0 69.456 0.084 69.48 ;
    END
  END prev_data[65]
  PIN prev_data[66]
    DIRECTION INPUT ;
    USE SIGNAL ;
    PORT
      LAYER M4 ;
        RECT  0 69.552 0.084 69.576 ;
    END
  END prev_data[66]
  PIN prev_data[67]
    DIRECTION INPUT ;
    USE SIGNAL ;
    PORT
      LAYER M4 ;
        RECT  0 69.648 0.084 69.672 ;
    END
  END prev_data[67]
  PIN prev_data[68]
    DIRECTION INPUT ;
    USE SIGNAL ;
    PORT
      LAYER M4 ;
        RECT  0 69.744 0.084 69.768 ;
    END
  END prev_data[68]
  PIN prev_data[69]
    DIRECTION INPUT ;
    USE SIGNAL ;
    PORT
      LAYER M4 ;
        RECT  0 69.84 0.084 69.864 ;
    END
  END prev_data[69]
  PIN prev_data[6]
    DIRECTION INPUT ;
    USE SIGNAL ;
    PORT
      LAYER M4 ;
        RECT  0 54.576 0.084 54.6 ;
    END
  END prev_data[6]
  PIN prev_data[70]
    DIRECTION INPUT ;
    USE SIGNAL ;
    PORT
      LAYER M4 ;
        RECT  0 69.936 0.084 69.96 ;
    END
  END prev_data[70]
  PIN prev_data[71]
    DIRECTION INPUT ;
    USE SIGNAL ;
    PORT
      LAYER M4 ;
        RECT  0 70.032 0.084 70.056 ;
    END
  END prev_data[71]
  PIN prev_data[72]
    DIRECTION INPUT ;
    USE SIGNAL ;
    PORT
      LAYER M4 ;
        RECT  0 70.128 0.084 70.152 ;
    END
  END prev_data[72]
  PIN prev_data[73]
    DIRECTION INPUT ;
    USE SIGNAL ;
    PORT
      LAYER M4 ;
        RECT  0 70.224 0.084 70.248 ;
    END
  END prev_data[73]
  PIN prev_data[74]
    DIRECTION INPUT ;
    USE SIGNAL ;
    PORT
      LAYER M4 ;
        RECT  0 70.32 0.084 70.344 ;
    END
  END prev_data[74]
  PIN prev_data[75]
    DIRECTION INPUT ;
    USE SIGNAL ;
    PORT
      LAYER M4 ;
        RECT  0 70.416 0.084 70.44 ;
    END
  END prev_data[75]
  PIN prev_data[76]
    DIRECTION INPUT ;
    USE SIGNAL ;
    PORT
      LAYER M4 ;
        RECT  0 70.512 0.084 70.536 ;
    END
  END prev_data[76]
  PIN prev_data[77]
    DIRECTION INPUT ;
    USE SIGNAL ;
    PORT
      LAYER M4 ;
        RECT  0 70.608 0.084 70.632 ;
    END
  END prev_data[77]
  PIN prev_data[78]
    DIRECTION INPUT ;
    USE SIGNAL ;
    PORT
      LAYER M4 ;
        RECT  0 70.704 0.084 70.728 ;
    END
  END prev_data[78]
  PIN prev_data[79]
    DIRECTION INPUT ;
    USE SIGNAL ;
    PORT
      LAYER M4 ;
        RECT  0 70.8 0.084 70.824 ;
    END
  END prev_data[79]
  PIN prev_data[7]
    DIRECTION INPUT ;
    USE SIGNAL ;
    PORT
      LAYER M4 ;
        RECT  0 54.672 0.084 54.696 ;
    END
  END prev_data[7]
  PIN prev_data[80]
    DIRECTION INPUT ;
    USE SIGNAL ;
    PORT
      LAYER M4 ;
        RECT  0 70.896 0.084 70.92 ;
    END
  END prev_data[80]
  PIN prev_data[81]
    DIRECTION INPUT ;
    USE SIGNAL ;
    PORT
      LAYER M4 ;
        RECT  0 70.992 0.084 71.016 ;
    END
  END prev_data[81]
  PIN prev_data[82]
    DIRECTION INPUT ;
    USE SIGNAL ;
    PORT
      LAYER M4 ;
        RECT  0 71.088 0.084 71.112 ;
    END
  END prev_data[82]
  PIN prev_data[83]
    DIRECTION INPUT ;
    USE SIGNAL ;
    PORT
      LAYER M4 ;
        RECT  0 71.184 0.084 71.208 ;
    END
  END prev_data[83]
  PIN prev_data[84]
    DIRECTION INPUT ;
    USE SIGNAL ;
    PORT
      LAYER M4 ;
        RECT  0 58.992 0.084 59.016 ;
    END
  END prev_data[84]
  PIN prev_data[85]
    DIRECTION INPUT ;
    USE SIGNAL ;
    PORT
      LAYER M4 ;
        RECT  0 59.088 0.084 59.112 ;
    END
  END prev_data[85]
  PIN prev_data[86]
    DIRECTION INPUT ;
    USE SIGNAL ;
    PORT
      LAYER M4 ;
        RECT  0 59.184 0.084 59.208 ;
    END
  END prev_data[86]
  PIN prev_data[87]
    DIRECTION INPUT ;
    USE SIGNAL ;
    PORT
      LAYER M4 ;
        RECT  0 59.28 0.084 59.304 ;
    END
  END prev_data[87]
  PIN prev_data[88]
    DIRECTION INPUT ;
    USE SIGNAL ;
    PORT
      LAYER M4 ;
        RECT  0 59.376 0.084 59.4 ;
    END
  END prev_data[88]
  PIN prev_data[89]
    DIRECTION INPUT ;
    USE SIGNAL ;
    PORT
      LAYER M4 ;
        RECT  0 59.472 0.084 59.496 ;
    END
  END prev_data[89]
  PIN prev_data[8]
    DIRECTION INPUT ;
    USE SIGNAL ;
    PORT
      LAYER M4 ;
        RECT  0 54.768 0.084 54.792 ;
    END
  END prev_data[8]
  PIN prev_data[90]
    DIRECTION INPUT ;
    USE SIGNAL ;
    PORT
      LAYER M4 ;
        RECT  0 59.568 0.084 59.592 ;
    END
  END prev_data[90]
  PIN prev_data[91]
    DIRECTION INPUT ;
    USE SIGNAL ;
    PORT
      LAYER M4 ;
        RECT  0 59.664 0.084 59.688 ;
    END
  END prev_data[91]
  PIN prev_data[92]
    DIRECTION INPUT ;
    USE SIGNAL ;
    PORT
      LAYER M4 ;
        RECT  0 59.76 0.084 59.784 ;
    END
  END prev_data[92]
  PIN prev_data[93]
    DIRECTION INPUT ;
    USE SIGNAL ;
    PORT
      LAYER M4 ;
        RECT  0 59.856 0.084 59.88 ;
    END
  END prev_data[93]
  PIN prev_data[94]
    DIRECTION INPUT ;
    USE SIGNAL ;
    PORT
      LAYER M4 ;
        RECT  0 59.952 0.084 59.976 ;
    END
  END prev_data[94]
  PIN prev_data[95]
    DIRECTION INPUT ;
    USE SIGNAL ;
    PORT
      LAYER M4 ;
        RECT  0 60.048 0.084 60.072 ;
    END
  END prev_data[95]
  PIN prev_data[96]
    DIRECTION INPUT ;
    USE SIGNAL ;
    PORT
      LAYER M4 ;
        RECT  0 60.144 0.084 60.168 ;
    END
  END prev_data[96]
  PIN prev_data[97]
    DIRECTION INPUT ;
    USE SIGNAL ;
    PORT
      LAYER M4 ;
        RECT  0 60.24 0.084 60.264 ;
    END
  END prev_data[97]
  PIN prev_data[98]
    DIRECTION INPUT ;
    USE SIGNAL ;
    PORT
      LAYER M4 ;
        RECT  0 60.336 0.084 60.36 ;
    END
  END prev_data[98]
  PIN prev_data[99]
    DIRECTION INPUT ;
    USE SIGNAL ;
    PORT
      LAYER M4 ;
        RECT  0 60.432 0.084 60.456 ;
    END
  END prev_data[99]
  PIN prev_data[9]
    DIRECTION INPUT ;
    USE SIGNAL ;
    PORT
      LAYER M4 ;
        RECT  0 54.864 0.084 54.888 ;
    END
  END prev_data[9]
  PIN prev_fault
    DIRECTION INPUT ;
    USE SIGNAL ;
    PORT
      LAYER M4 ;
        RECT  0 76.272 0.084 76.296 ;
    END
  END prev_fault
  PIN prev_v[0]
    DIRECTION INPUT ;
    USE SIGNAL ;
    PORT
      LAYER M4 ;
        RECT  0 76.368 0.084 76.392 ;
    END
  END prev_v[0]
  PIN prev_v[1]
    DIRECTION INPUT ;
    USE SIGNAL ;
    PORT
      LAYER M4 ;
        RECT  0 76.464 0.084 76.488 ;
    END
  END prev_v[1]
  PIN prev_v[2]
    DIRECTION INPUT ;
    USE SIGNAL ;
    PORT
      LAYER M4 ;
        RECT  0 76.56 0.084 76.584 ;
    END
  END prev_v[2]
  PIN prev_v[3]
    DIRECTION INPUT ;
    USE SIGNAL ;
    PORT
      LAYER M4 ;
        RECT  0 76.656 0.084 76.68 ;
    END
  END prev_v[3]
  PIN read_addr[0]
    DIRECTION INPUT ;
    USE SIGNAL ;
    PORT
      LAYER M4 ;
        RECT  0 76.752 0.084 76.776 ;
    END
  END read_addr[0]
  PIN read_addr[10]
    DIRECTION INPUT ;
    USE SIGNAL ;
    PORT
      LAYER M4 ;
        RECT  0 77.712 0.084 77.736 ;
    END
  END read_addr[10]
  PIN read_addr[11]
    DIRECTION INPUT ;
    USE SIGNAL ;
    PORT
      LAYER M4 ;
        RECT  0 77.808 0.084 77.832 ;
    END
  END read_addr[11]
  PIN read_addr[12]
    DIRECTION INPUT ;
    USE SIGNAL ;
    PORT
      LAYER M4 ;
        RECT  0 77.904 0.084 77.928 ;
    END
  END read_addr[12]
  PIN read_addr[13]
    DIRECTION INPUT ;
    USE SIGNAL ;
    PORT
      LAYER M4 ;
        RECT  0 78 0.084 78.024 ;
    END
  END read_addr[13]
  PIN read_addr[14]
    DIRECTION INPUT ;
    USE SIGNAL ;
    PORT
      LAYER M4 ;
        RECT  0 78.096 0.084 78.12 ;
    END
  END read_addr[14]
  PIN read_addr[15]
    DIRECTION INPUT ;
    USE SIGNAL ;
    PORT
      LAYER M4 ;
        RECT  0 49.008 0.084 49.032 ;
    END
  END read_addr[15]
  PIN read_addr[16]
    DIRECTION INPUT ;
    USE SIGNAL ;
    PORT
      LAYER M4 ;
        RECT  0 49.104 0.084 49.128 ;
    END
  END read_addr[16]
  PIN read_addr[17]
    DIRECTION INPUT ;
    USE SIGNAL ;
    PORT
      LAYER M4 ;
        RECT  0 49.2 0.084 49.224 ;
    END
  END read_addr[17]
  PIN read_addr[18]
    DIRECTION INPUT ;
    USE SIGNAL ;
    PORT
      LAYER M4 ;
        RECT  0 49.296 0.084 49.32 ;
    END
  END read_addr[18]
  PIN read_addr[19]
    DIRECTION INPUT ;
    USE SIGNAL ;
    PORT
      LAYER M4 ;
        RECT  0 49.392 0.084 49.416 ;
    END
  END read_addr[19]
  PIN read_addr[1]
    DIRECTION INPUT ;
    USE SIGNAL ;
    PORT
      LAYER M4 ;
        RECT  0 76.848 0.084 76.872 ;
    END
  END read_addr[1]
  PIN read_addr[20]
    DIRECTION INPUT ;
    USE SIGNAL ;
    PORT
      LAYER M4 ;
        RECT  0 49.488 0.084 49.512 ;
    END
  END read_addr[20]
  PIN read_addr[21]
    DIRECTION INPUT ;
    USE SIGNAL ;
    PORT
      LAYER M4 ;
        RECT  0 49.584 0.084 49.608 ;
    END
  END read_addr[21]
  PIN read_addr[22]
    DIRECTION INPUT ;
    USE SIGNAL ;
    PORT
      LAYER M4 ;
        RECT  0 49.68 0.084 49.704 ;
    END
  END read_addr[22]
  PIN read_addr[23]
    DIRECTION INPUT ;
    USE SIGNAL ;
    PORT
      LAYER M4 ;
        RECT  0 49.776 0.084 49.8 ;
    END
  END read_addr[23]
  PIN read_addr[24]
    DIRECTION INPUT ;
    USE SIGNAL ;
    PORT
      LAYER M4 ;
        RECT  0 49.872 0.084 49.896 ;
    END
  END read_addr[24]
  PIN read_addr[25]
    DIRECTION INPUT ;
    USE SIGNAL ;
    PORT
      LAYER M4 ;
        RECT  0 49.968 0.084 49.992 ;
    END
  END read_addr[25]
  PIN read_addr[26]
    DIRECTION INPUT ;
    USE SIGNAL ;
    PORT
      LAYER M4 ;
        RECT  0 50.064 0.084 50.088 ;
    END
  END read_addr[26]
  PIN read_addr[27]
    DIRECTION INPUT ;
    USE SIGNAL ;
    PORT
      LAYER M4 ;
        RECT  0 50.16 0.084 50.184 ;
    END
  END read_addr[27]
  PIN read_addr[28]
    DIRECTION INPUT ;
    USE SIGNAL ;
    PORT
      LAYER M4 ;
        RECT  0 50.256 0.084 50.28 ;
    END
  END read_addr[28]
  PIN read_addr[29]
    DIRECTION INPUT ;
    USE SIGNAL ;
    PORT
      LAYER M4 ;
        RECT  0 50.352 0.084 50.376 ;
    END
  END read_addr[29]
  PIN read_addr[2]
    DIRECTION INPUT ;
    USE SIGNAL ;
    PORT
      LAYER M4 ;
        RECT  0 76.944 0.084 76.968 ;
    END
  END read_addr[2]
  PIN read_addr[30]
    DIRECTION INPUT ;
    USE SIGNAL ;
    PORT
      LAYER M4 ;
        RECT  0 50.448 0.084 50.472 ;
    END
  END read_addr[30]
  PIN read_addr[31]
    DIRECTION INPUT ;
    USE SIGNAL ;
    PORT
      LAYER M4 ;
        RECT  0 50.544 0.084 50.568 ;
    END
  END read_addr[31]
  PIN read_addr[32]
    DIRECTION INPUT ;
    USE SIGNAL ;
    PORT
      LAYER M4 ;
        RECT  0 50.64 0.084 50.664 ;
    END
  END read_addr[32]
  PIN read_addr[33]
    DIRECTION INPUT ;
    USE SIGNAL ;
    PORT
      LAYER M4 ;
        RECT  0 50.736 0.084 50.76 ;
    END
  END read_addr[33]
  PIN read_addr[34]
    DIRECTION INPUT ;
    USE SIGNAL ;
    PORT
      LAYER M4 ;
        RECT  0 50.832 0.084 50.856 ;
    END
  END read_addr[34]
  PIN read_addr[35]
    DIRECTION INPUT ;
    USE SIGNAL ;
    PORT
      LAYER M4 ;
        RECT  0 50.928 0.084 50.952 ;
    END
  END read_addr[35]
  PIN read_addr[36]
    DIRECTION INPUT ;
    USE SIGNAL ;
    PORT
      LAYER M4 ;
        RECT  0 51.024 0.084 51.048 ;
    END
  END read_addr[36]
  PIN read_addr[37]
    DIRECTION INPUT ;
    USE SIGNAL ;
    PORT
      LAYER M4 ;
        RECT  0 51.12 0.084 51.144 ;
    END
  END read_addr[37]
  PIN read_addr[38]
    DIRECTION INPUT ;
    USE SIGNAL ;
    PORT
      LAYER M4 ;
        RECT  0 51.216 0.084 51.24 ;
    END
  END read_addr[38]
  PIN read_addr[39]
    DIRECTION INPUT ;
    USE SIGNAL ;
    PORT
      LAYER M4 ;
        RECT  0 51.312 0.084 51.336 ;
    END
  END read_addr[39]
  PIN read_addr[3]
    DIRECTION INPUT ;
    USE SIGNAL ;
    PORT
      LAYER M4 ;
        RECT  0 77.04 0.084 77.064 ;
    END
  END read_addr[3]
  PIN read_addr[40]
    DIRECTION INPUT ;
    USE SIGNAL ;
    PORT
      LAYER M4 ;
        RECT  0 51.408 0.084 51.432 ;
    END
  END read_addr[40]
  PIN read_addr[41]
    DIRECTION INPUT ;
    USE SIGNAL ;
    PORT
      LAYER M4 ;
        RECT  0 51.504 0.084 51.528 ;
    END
  END read_addr[41]
  PIN read_addr[42]
    DIRECTION INPUT ;
    USE SIGNAL ;
    PORT
      LAYER M4 ;
        RECT  0 51.6 0.084 51.624 ;
    END
  END read_addr[42]
  PIN read_addr[43]
    DIRECTION INPUT ;
    USE SIGNAL ;
    PORT
      LAYER M4 ;
        RECT  0 51.696 0.084 51.72 ;
    END
  END read_addr[43]
  PIN read_addr[4]
    DIRECTION INPUT ;
    USE SIGNAL ;
    PORT
      LAYER M4 ;
        RECT  0 77.136 0.084 77.16 ;
    END
  END read_addr[4]
  PIN read_addr[5]
    DIRECTION INPUT ;
    USE SIGNAL ;
    PORT
      LAYER M4 ;
        RECT  0 77.232 0.084 77.256 ;
    END
  END read_addr[5]
  PIN read_addr[6]
    DIRECTION INPUT ;
    USE SIGNAL ;
    PORT
      LAYER M4 ;
        RECT  0 77.328 0.084 77.352 ;
    END
  END read_addr[6]
  PIN read_addr[7]
    DIRECTION INPUT ;
    USE SIGNAL ;
    PORT
      LAYER M4 ;
        RECT  0 77.424 0.084 77.448 ;
    END
  END read_addr[7]
  PIN read_addr[8]
    DIRECTION INPUT ;
    USE SIGNAL ;
    PORT
      LAYER M4 ;
        RECT  0 77.52 0.084 77.544 ;
    END
  END read_addr[8]
  PIN read_addr[9]
    DIRECTION INPUT ;
    USE SIGNAL ;
    PORT
      LAYER M4 ;
        RECT  0 77.616 0.084 77.64 ;
    END
  END read_addr[9]
  PIN read_v[0]
    DIRECTION INPUT ;
    USE SIGNAL ;
    PORT
      LAYER M4 ;
        RECT  0 51.792 0.084 51.816 ;
    END
  END read_v[0]
  PIN read_v[1]
    DIRECTION INPUT ;
    USE SIGNAL ;
    PORT
      LAYER M4 ;
        RECT  0 51.888 0.084 51.912 ;
    END
  END read_v[1]
  PIN read_v[2]
    DIRECTION INPUT ;
    USE SIGNAL ;
    PORT
      LAYER M4 ;
        RECT  0 51.984 0.084 52.008 ;
    END
  END read_v[2]
  PIN read_v[3]
    DIRECTION INPUT ;
    USE SIGNAL ;
    PORT
      LAYER M4 ;
        RECT  0 52.752 0.084 52.776 ;
    END
  END read_v[3]
  PIN response_addr[0]
    DIRECTION OUTPUT ;
    USE SIGNAL ;
    PORT
      LAYER M4 ;
        RECT  53.916 66.096 54 66.12 ;
    END
  END response_addr[0]
  PIN response_addr[10]
    DIRECTION OUTPUT ;
    USE SIGNAL ;
    PORT
      LAYER M4 ;
        RECT  53.916 67.056 54 67.08 ;
    END
  END response_addr[10]
  PIN response_addr[11]
    DIRECTION OUTPUT ;
    USE SIGNAL ;
    PORT
      LAYER M4 ;
        RECT  53.916 67.152 54 67.176 ;
    END
  END response_addr[11]
  PIN response_addr[12]
    DIRECTION OUTPUT ;
    USE SIGNAL ;
    PORT
      LAYER M4 ;
        RECT  53.916 67.248 54 67.272 ;
    END
  END response_addr[12]
  PIN response_addr[13]
    DIRECTION OUTPUT ;
    USE SIGNAL ;
    PORT
      LAYER M4 ;
        RECT  53.916 67.344 54 67.368 ;
    END
  END response_addr[13]
  PIN response_addr[14]
    DIRECTION OUTPUT ;
    USE SIGNAL ;
    PORT
      LAYER M4 ;
        RECT  53.916 67.44 54 67.464 ;
    END
  END response_addr[14]
  PIN response_addr[15]
    DIRECTION OUTPUT ;
    USE SIGNAL ;
    PORT
      LAYER M4 ;
        RECT  53.916 58.32 54 58.344 ;
    END
  END response_addr[15]
  PIN response_addr[16]
    DIRECTION OUTPUT ;
    USE SIGNAL ;
    PORT
      LAYER M4 ;
        RECT  53.916 58.416 54 58.44 ;
    END
  END response_addr[16]
  PIN response_addr[17]
    DIRECTION OUTPUT ;
    USE SIGNAL ;
    PORT
      LAYER M4 ;
        RECT  53.916 58.512 54 58.536 ;
    END
  END response_addr[17]
  PIN response_addr[18]
    DIRECTION OUTPUT ;
    USE SIGNAL ;
    PORT
      LAYER M4 ;
        RECT  53.916 58.608 54 58.632 ;
    END
  END response_addr[18]
  PIN response_addr[19]
    DIRECTION OUTPUT ;
    USE SIGNAL ;
    PORT
      LAYER M4 ;
        RECT  53.916 58.704 54 58.728 ;
    END
  END response_addr[19]
  PIN response_addr[1]
    DIRECTION OUTPUT ;
    USE SIGNAL ;
    PORT
      LAYER M4 ;
        RECT  53.916 66.192 54 66.216 ;
    END
  END response_addr[1]
  PIN response_addr[20]
    DIRECTION OUTPUT ;
    USE SIGNAL ;
    PORT
      LAYER M4 ;
        RECT  53.916 58.8 54 58.824 ;
    END
  END response_addr[20]
  PIN response_addr[21]
    DIRECTION OUTPUT ;
    USE SIGNAL ;
    PORT
      LAYER M4 ;
        RECT  53.916 58.896 54 58.92 ;
    END
  END response_addr[21]
  PIN response_addr[22]
    DIRECTION OUTPUT ;
    USE SIGNAL ;
    PORT
      LAYER M4 ;
        RECT  53.916 58.992 54 59.016 ;
    END
  END response_addr[22]
  PIN response_addr[23]
    DIRECTION OUTPUT ;
    USE SIGNAL ;
    PORT
      LAYER M4 ;
        RECT  53.916 59.088 54 59.112 ;
    END
  END response_addr[23]
  PIN response_addr[24]
    DIRECTION OUTPUT ;
    USE SIGNAL ;
    PORT
      LAYER M4 ;
        RECT  53.916 59.184 54 59.208 ;
    END
  END response_addr[24]
  PIN response_addr[25]
    DIRECTION OUTPUT ;
    USE SIGNAL ;
    PORT
      LAYER M4 ;
        RECT  53.916 59.28 54 59.304 ;
    END
  END response_addr[25]
  PIN response_addr[26]
    DIRECTION OUTPUT ;
    USE SIGNAL ;
    PORT
      LAYER M4 ;
        RECT  53.916 59.376 54 59.4 ;
    END
  END response_addr[26]
  PIN response_addr[27]
    DIRECTION OUTPUT ;
    USE SIGNAL ;
    PORT
      LAYER M4 ;
        RECT  53.916 59.472 54 59.496 ;
    END
  END response_addr[27]
  PIN response_addr[28]
    DIRECTION OUTPUT ;
    USE SIGNAL ;
    PORT
      LAYER M4 ;
        RECT  53.916 59.568 54 59.592 ;
    END
  END response_addr[28]
  PIN response_addr[29]
    DIRECTION OUTPUT ;
    USE SIGNAL ;
    PORT
      LAYER M4 ;
        RECT  53.916 59.664 54 59.688 ;
    END
  END response_addr[29]
  PIN response_addr[2]
    DIRECTION OUTPUT ;
    USE SIGNAL ;
    PORT
      LAYER M4 ;
        RECT  53.916 66.288 54 66.312 ;
    END
  END response_addr[2]
  PIN response_addr[30]
    DIRECTION OUTPUT ;
    USE SIGNAL ;
    PORT
      LAYER M4 ;
        RECT  53.916 59.76 54 59.784 ;
    END
  END response_addr[30]
  PIN response_addr[31]
    DIRECTION OUTPUT ;
    USE SIGNAL ;
    PORT
      LAYER M4 ;
        RECT  53.916 59.856 54 59.88 ;
    END
  END response_addr[31]
  PIN response_addr[32]
    DIRECTION OUTPUT ;
    USE SIGNAL ;
    PORT
      LAYER M4 ;
        RECT  53.916 59.952 54 59.976 ;
    END
  END response_addr[32]
  PIN response_addr[33]
    DIRECTION OUTPUT ;
    USE SIGNAL ;
    PORT
      LAYER M4 ;
        RECT  53.916 60.048 54 60.072 ;
    END
  END response_addr[33]
  PIN response_addr[34]
    DIRECTION OUTPUT ;
    USE SIGNAL ;
    PORT
      LAYER M4 ;
        RECT  53.916 60.144 54 60.168 ;
    END
  END response_addr[34]
  PIN response_addr[35]
    DIRECTION OUTPUT ;
    USE SIGNAL ;
    PORT
      LAYER M4 ;
        RECT  53.916 60.24 54 60.264 ;
    END
  END response_addr[35]
  PIN response_addr[36]
    DIRECTION OUTPUT ;
    USE SIGNAL ;
    PORT
      LAYER M4 ;
        RECT  53.916 60.336 54 60.36 ;
    END
  END response_addr[36]
  PIN response_addr[37]
    DIRECTION OUTPUT ;
    USE SIGNAL ;
    PORT
      LAYER M4 ;
        RECT  53.916 60.432 54 60.456 ;
    END
  END response_addr[37]
  PIN response_addr[38]
    DIRECTION OUTPUT ;
    USE SIGNAL ;
    PORT
      LAYER M4 ;
        RECT  53.916 60.528 54 60.552 ;
    END
  END response_addr[38]
  PIN response_addr[39]
    DIRECTION OUTPUT ;
    USE SIGNAL ;
    PORT
      LAYER M4 ;
        RECT  53.916 60.624 54 60.648 ;
    END
  END response_addr[39]
  PIN response_addr[3]
    DIRECTION OUTPUT ;
    USE SIGNAL ;
    PORT
      LAYER M4 ;
        RECT  53.916 66.384 54 66.408 ;
    END
  END response_addr[3]
  PIN response_addr[40]
    DIRECTION OUTPUT ;
    USE SIGNAL ;
    PORT
      LAYER M4 ;
        RECT  53.916 60.72 54 60.744 ;
    END
  END response_addr[40]
  PIN response_addr[41]
    DIRECTION OUTPUT ;
    USE SIGNAL ;
    PORT
      LAYER M4 ;
        RECT  53.916 60.816 54 60.84 ;
    END
  END response_addr[41]
  PIN response_addr[42]
    DIRECTION OUTPUT ;
    USE SIGNAL ;
    PORT
      LAYER M4 ;
        RECT  53.916 60.912 54 60.936 ;
    END
  END response_addr[42]
  PIN response_addr[43]
    DIRECTION OUTPUT ;
    USE SIGNAL ;
    PORT
      LAYER M4 ;
        RECT  53.916 61.008 54 61.032 ;
    END
  END response_addr[43]
  PIN response_addr[4]
    DIRECTION OUTPUT ;
    USE SIGNAL ;
    PORT
      LAYER M4 ;
        RECT  53.916 66.48 54 66.504 ;
    END
  END response_addr[4]
  PIN response_addr[5]
    DIRECTION OUTPUT ;
    USE SIGNAL ;
    PORT
      LAYER M4 ;
        RECT  53.916 66.576 54 66.6 ;
    END
  END response_addr[5]
  PIN response_addr[6]
    DIRECTION OUTPUT ;
    USE SIGNAL ;
    PORT
      LAYER M4 ;
        RECT  53.916 66.672 54 66.696 ;
    END
  END response_addr[6]
  PIN response_addr[7]
    DIRECTION OUTPUT ;
    USE SIGNAL ;
    PORT
      LAYER M4 ;
        RECT  53.916 66.768 54 66.792 ;
    END
  END response_addr[7]
  PIN response_addr[8]
    DIRECTION OUTPUT ;
    USE SIGNAL ;
    PORT
      LAYER M4 ;
        RECT  53.916 66.864 54 66.888 ;
    END
  END response_addr[8]
  PIN response_addr[9]
    DIRECTION OUTPUT ;
    USE SIGNAL ;
    PORT
      LAYER M4 ;
        RECT  53.916 66.96 54 66.984 ;
    END
  END response_addr[9]
  PIN response_data[0]
    DIRECTION OUTPUT ;
    USE SIGNAL ;
    PORT
      LAYER M4 ;
        RECT  53.916 61.104 54 61.128 ;
    END
  END response_data[0]
  PIN response_data[100]
    DIRECTION OUTPUT ;
    USE SIGNAL ;
    PORT
      LAYER M4 ;
        RECT  53.916 54.576 54 54.6 ;
    END
  END response_data[100]
  PIN response_data[101]
    DIRECTION OUTPUT ;
    USE SIGNAL ;
    PORT
      LAYER M4 ;
        RECT  53.916 54.672 54 54.696 ;
    END
  END response_data[101]
  PIN response_data[102]
    DIRECTION OUTPUT ;
    USE SIGNAL ;
    PORT
      LAYER M4 ;
        RECT  53.916 54.768 54 54.792 ;
    END
  END response_data[102]
  PIN response_data[103]
    DIRECTION OUTPUT ;
    USE SIGNAL ;
    PORT
      LAYER M4 ;
        RECT  53.916 54.864 54 54.888 ;
    END
  END response_data[103]
  PIN response_data[104]
    DIRECTION OUTPUT ;
    USE SIGNAL ;
    PORT
      LAYER M4 ;
        RECT  53.916 54.96 54 54.984 ;
    END
  END response_data[104]
  PIN response_data[105]
    DIRECTION OUTPUT ;
    USE SIGNAL ;
    PORT
      LAYER M4 ;
        RECT  53.916 55.056 54 55.08 ;
    END
  END response_data[105]
  PIN response_data[106]
    DIRECTION OUTPUT ;
    USE SIGNAL ;
    PORT
      LAYER M4 ;
        RECT  53.916 55.152 54 55.176 ;
    END
  END response_data[106]
  PIN response_data[107]
    DIRECTION OUTPUT ;
    USE SIGNAL ;
    PORT
      LAYER M4 ;
        RECT  53.916 55.248 54 55.272 ;
    END
  END response_data[107]
  PIN response_data[108]
    DIRECTION OUTPUT ;
    USE SIGNAL ;
    PORT
      LAYER M4 ;
        RECT  53.916 55.344 54 55.368 ;
    END
  END response_data[108]
  PIN response_data[109]
    DIRECTION OUTPUT ;
    USE SIGNAL ;
    PORT
      LAYER M4 ;
        RECT  53.916 55.44 54 55.464 ;
    END
  END response_data[109]
  PIN response_data[10]
    DIRECTION OUTPUT ;
    USE SIGNAL ;
    PORT
      LAYER M4 ;
        RECT  53.916 74.352 54 74.376 ;
    END
  END response_data[10]
  PIN response_data[110]
    DIRECTION OUTPUT ;
    USE SIGNAL ;
    PORT
      LAYER M4 ;
        RECT  53.916 55.536 54 55.56 ;
    END
  END response_data[110]
  PIN response_data[111]
    DIRECTION OUTPUT ;
    USE SIGNAL ;
    PORT
      LAYER M4 ;
        RECT  53.916 55.632 54 55.656 ;
    END
  END response_data[111]
  PIN response_data[112]
    DIRECTION OUTPUT ;
    USE SIGNAL ;
    PORT
      LAYER M4 ;
        RECT  53.916 55.728 54 55.752 ;
    END
  END response_data[112]
  PIN response_data[113]
    DIRECTION OUTPUT ;
    USE SIGNAL ;
    PORT
      LAYER M4 ;
        RECT  53.916 55.824 54 55.848 ;
    END
  END response_data[113]
  PIN response_data[114]
    DIRECTION OUTPUT ;
    USE SIGNAL ;
    PORT
      LAYER M4 ;
        RECT  53.916 55.92 54 55.944 ;
    END
  END response_data[114]
  PIN response_data[115]
    DIRECTION OUTPUT ;
    USE SIGNAL ;
    PORT
      LAYER M4 ;
        RECT  53.916 56.016 54 56.04 ;
    END
  END response_data[115]
  PIN response_data[116]
    DIRECTION OUTPUT ;
    USE SIGNAL ;
    PORT
      LAYER M4 ;
        RECT  53.916 56.112 54 56.136 ;
    END
  END response_data[116]
  PIN response_data[117]
    DIRECTION OUTPUT ;
    USE SIGNAL ;
    PORT
      LAYER M4 ;
        RECT  53.916 56.208 54 56.232 ;
    END
  END response_data[117]
  PIN response_data[118]
    DIRECTION OUTPUT ;
    USE SIGNAL ;
    PORT
      LAYER M4 ;
        RECT  53.916 56.304 54 56.328 ;
    END
  END response_data[118]
  PIN response_data[119]
    DIRECTION OUTPUT ;
    USE SIGNAL ;
    PORT
      LAYER M4 ;
        RECT  53.916 56.4 54 56.424 ;
    END
  END response_data[119]
  PIN response_data[11]
    DIRECTION OUTPUT ;
    USE SIGNAL ;
    PORT
      LAYER M4 ;
        RECT  53.916 74.448 54 74.472 ;
    END
  END response_data[11]
  PIN response_data[120]
    DIRECTION OUTPUT ;
    USE SIGNAL ;
    PORT
      LAYER M4 ;
        RECT  53.916 56.496 54 56.52 ;
    END
  END response_data[120]
  PIN response_data[121]
    DIRECTION OUTPUT ;
    USE SIGNAL ;
    PORT
      LAYER M4 ;
        RECT  53.916 56.592 54 56.616 ;
    END
  END response_data[121]
  PIN response_data[122]
    DIRECTION OUTPUT ;
    USE SIGNAL ;
    PORT
      LAYER M4 ;
        RECT  53.916 56.688 54 56.712 ;
    END
  END response_data[122]
  PIN response_data[123]
    DIRECTION OUTPUT ;
    USE SIGNAL ;
    PORT
      LAYER M4 ;
        RECT  53.916 56.784 54 56.808 ;
    END
  END response_data[123]
  PIN response_data[124]
    DIRECTION OUTPUT ;
    USE SIGNAL ;
    PORT
      LAYER M4 ;
        RECT  53.916 56.88 54 56.904 ;
    END
  END response_data[124]
  PIN response_data[125]
    DIRECTION OUTPUT ;
    USE SIGNAL ;
    PORT
      LAYER M4 ;
        RECT  53.916 56.976 54 57 ;
    END
  END response_data[125]
  PIN response_data[126]
    DIRECTION OUTPUT ;
    USE SIGNAL ;
    PORT
      LAYER M4 ;
        RECT  53.916 57.072 54 57.096 ;
    END
  END response_data[126]
  PIN response_data[127]
    DIRECTION OUTPUT ;
    USE SIGNAL ;
    PORT
      LAYER M4 ;
        RECT  53.916 57.168 54 57.192 ;
    END
  END response_data[127]
  PIN response_data[128]
    DIRECTION OUTPUT ;
    USE SIGNAL ;
    PORT
      LAYER M4 ;
        RECT  53.916 57.264 54 57.288 ;
    END
  END response_data[128]
  PIN response_data[129]
    DIRECTION OUTPUT ;
    USE SIGNAL ;
    PORT
      LAYER M4 ;
        RECT  53.916 57.36 54 57.384 ;
    END
  END response_data[129]
  PIN response_data[12]
    DIRECTION OUTPUT ;
    USE SIGNAL ;
    PORT
      LAYER M4 ;
        RECT  53.916 74.544 54 74.568 ;
    END
  END response_data[12]
  PIN response_data[130]
    DIRECTION OUTPUT ;
    USE SIGNAL ;
    PORT
      LAYER M4 ;
        RECT  53.916 57.456 54 57.48 ;
    END
  END response_data[130]
  PIN response_data[131]
    DIRECTION OUTPUT ;
    USE SIGNAL ;
    PORT
      LAYER M4 ;
        RECT  53.916 77.52 54 77.544 ;
    END
  END response_data[131]
  PIN response_data[132]
    DIRECTION OUTPUT ;
    USE SIGNAL ;
    PORT
      LAYER M4 ;
        RECT  53.916 77.616 54 77.64 ;
    END
  END response_data[132]
  PIN response_data[133]
    DIRECTION OUTPUT ;
    USE SIGNAL ;
    PORT
      LAYER M4 ;
        RECT  53.916 77.712 54 77.736 ;
    END
  END response_data[133]
  PIN response_data[134]
    DIRECTION OUTPUT ;
    USE SIGNAL ;
    PORT
      LAYER M4 ;
        RECT  53.916 77.808 54 77.832 ;
    END
  END response_data[134]
  PIN response_data[135]
    DIRECTION OUTPUT ;
    USE SIGNAL ;
    PORT
      LAYER M4 ;
        RECT  53.916 77.904 54 77.928 ;
    END
  END response_data[135]
  PIN response_data[136]
    DIRECTION OUTPUT ;
    USE SIGNAL ;
    PORT
      LAYER M4 ;
        RECT  53.916 78 54 78.024 ;
    END
  END response_data[136]
  PIN response_data[137]
    DIRECTION OUTPUT ;
    USE SIGNAL ;
    PORT
      LAYER M4 ;
        RECT  53.916 78.096 54 78.12 ;
    END
  END response_data[137]
  PIN response_data[138]
    DIRECTION OUTPUT ;
    USE SIGNAL ;
    PORT
      LAYER M4 ;
        RECT  53.916 78.192 54 78.216 ;
    END
  END response_data[138]
  PIN response_data[139]
    DIRECTION OUTPUT ;
    USE SIGNAL ;
    PORT
      LAYER M4 ;
        RECT  53.916 78.288 54 78.312 ;
    END
  END response_data[139]
  PIN response_data[13]
    DIRECTION OUTPUT ;
    USE SIGNAL ;
    PORT
      LAYER M4 ;
        RECT  53.916 74.64 54 74.664 ;
    END
  END response_data[13]
  PIN response_data[140]
    DIRECTION OUTPUT ;
    USE SIGNAL ;
    PORT
      LAYER M4 ;
        RECT  53.916 78.384 54 78.408 ;
    END
  END response_data[140]
  PIN response_data[141]
    DIRECTION OUTPUT ;
    USE SIGNAL ;
    PORT
      LAYER M4 ;
        RECT  53.916 78.48 54 78.504 ;
    END
  END response_data[141]
  PIN response_data[142]
    DIRECTION OUTPUT ;
    USE SIGNAL ;
    PORT
      LAYER M4 ;
        RECT  53.916 78.576 54 78.6 ;
    END
  END response_data[142]
  PIN response_data[143]
    DIRECTION OUTPUT ;
    USE SIGNAL ;
    PORT
      LAYER M4 ;
        RECT  53.916 78.672 54 78.696 ;
    END
  END response_data[143]
  PIN response_data[144]
    DIRECTION OUTPUT ;
    USE SIGNAL ;
    PORT
      LAYER M4 ;
        RECT  53.916 78.768 54 78.792 ;
    END
  END response_data[144]
  PIN response_data[145]
    DIRECTION OUTPUT ;
    USE SIGNAL ;
    PORT
      LAYER M4 ;
        RECT  53.916 78.864 54 78.888 ;
    END
  END response_data[145]
  PIN response_data[146]
    DIRECTION OUTPUT ;
    USE SIGNAL ;
    PORT
      LAYER M4 ;
        RECT  53.916 78.96 54 78.984 ;
    END
  END response_data[146]
  PIN response_data[147]
    DIRECTION OUTPUT ;
    USE SIGNAL ;
    PORT
      LAYER M4 ;
        RECT  53.916 79.056 54 79.08 ;
    END
  END response_data[147]
  PIN response_data[148]
    DIRECTION OUTPUT ;
    USE SIGNAL ;
    PORT
      LAYER M4 ;
        RECT  53.916 79.152 54 79.176 ;
    END
  END response_data[148]
  PIN response_data[149]
    DIRECTION OUTPUT ;
    USE SIGNAL ;
    PORT
      LAYER M4 ;
        RECT  53.916 79.248 54 79.272 ;
    END
  END response_data[149]
  PIN response_data[14]
    DIRECTION OUTPUT ;
    USE SIGNAL ;
    PORT
      LAYER M4 ;
        RECT  53.916 74.736 54 74.76 ;
    END
  END response_data[14]
  PIN response_data[150]
    DIRECTION OUTPUT ;
    USE SIGNAL ;
    PORT
      LAYER M4 ;
        RECT  53.916 79.344 54 79.368 ;
    END
  END response_data[150]
  PIN response_data[151]
    DIRECTION OUTPUT ;
    USE SIGNAL ;
    PORT
      LAYER M4 ;
        RECT  53.916 79.44 54 79.464 ;
    END
  END response_data[151]
  PIN response_data[152]
    DIRECTION OUTPUT ;
    USE SIGNAL ;
    PORT
      LAYER M4 ;
        RECT  53.916 79.536 54 79.56 ;
    END
  END response_data[152]
  PIN response_data[153]
    DIRECTION OUTPUT ;
    USE SIGNAL ;
    PORT
      LAYER M4 ;
        RECT  53.916 79.632 54 79.656 ;
    END
  END response_data[153]
  PIN response_data[154]
    DIRECTION OUTPUT ;
    USE SIGNAL ;
    PORT
      LAYER M4 ;
        RECT  53.916 79.728 54 79.752 ;
    END
  END response_data[154]
  PIN response_data[155]
    DIRECTION OUTPUT ;
    USE SIGNAL ;
    PORT
      LAYER M4 ;
        RECT  53.916 79.824 54 79.848 ;
    END
  END response_data[155]
  PIN response_data[156]
    DIRECTION OUTPUT ;
    USE SIGNAL ;
    PORT
      LAYER M4 ;
        RECT  53.916 79.92 54 79.944 ;
    END
  END response_data[156]
  PIN response_data[157]
    DIRECTION OUTPUT ;
    USE SIGNAL ;
    PORT
      LAYER M4 ;
        RECT  53.916 80.016 54 80.04 ;
    END
  END response_data[157]
  PIN response_data[158]
    DIRECTION OUTPUT ;
    USE SIGNAL ;
    PORT
      LAYER M4 ;
        RECT  53.916 80.112 54 80.136 ;
    END
  END response_data[158]
  PIN response_data[159]
    DIRECTION OUTPUT ;
    USE SIGNAL ;
    PORT
      LAYER M4 ;
        RECT  53.916 80.208 54 80.232 ;
    END
  END response_data[159]
  PIN response_data[15]
    DIRECTION OUTPUT ;
    USE SIGNAL ;
    PORT
      LAYER M4 ;
        RECT  53.916 74.832 54 74.856 ;
    END
  END response_data[15]
  PIN response_data[160]
    DIRECTION OUTPUT ;
    USE SIGNAL ;
    PORT
      LAYER M4 ;
        RECT  53.916 80.304 54 80.328 ;
    END
  END response_data[160]
  PIN response_data[161]
    DIRECTION OUTPUT ;
    USE SIGNAL ;
    PORT
      LAYER M4 ;
        RECT  53.916 80.4 54 80.424 ;
    END
  END response_data[161]
  PIN response_data[162]
    DIRECTION OUTPUT ;
    USE SIGNAL ;
    PORT
      LAYER M4 ;
        RECT  53.916 80.496 54 80.52 ;
    END
  END response_data[162]
  PIN response_data[163]
    DIRECTION OUTPUT ;
    USE SIGNAL ;
    PORT
      LAYER M4 ;
        RECT  53.916 51.408 54 51.432 ;
    END
  END response_data[163]
  PIN response_data[164]
    DIRECTION OUTPUT ;
    USE SIGNAL ;
    PORT
      LAYER M4 ;
        RECT  53.916 51.504 54 51.528 ;
    END
  END response_data[164]
  PIN response_data[165]
    DIRECTION OUTPUT ;
    USE SIGNAL ;
    PORT
      LAYER M4 ;
        RECT  53.916 51.6 54 51.624 ;
    END
  END response_data[165]
  PIN response_data[166]
    DIRECTION OUTPUT ;
    USE SIGNAL ;
    PORT
      LAYER M4 ;
        RECT  53.916 51.696 54 51.72 ;
    END
  END response_data[166]
  PIN response_data[167]
    DIRECTION OUTPUT ;
    USE SIGNAL ;
    PORT
      LAYER M4 ;
        RECT  53.916 51.792 54 51.816 ;
    END
  END response_data[167]
  PIN response_data[168]
    DIRECTION OUTPUT ;
    USE SIGNAL ;
    PORT
      LAYER M4 ;
        RECT  53.916 51.888 54 51.912 ;
    END
  END response_data[168]
  PIN response_data[169]
    DIRECTION OUTPUT ;
    USE SIGNAL ;
    PORT
      LAYER M4 ;
        RECT  53.916 51.984 54 52.008 ;
    END
  END response_data[169]
  PIN response_data[16]
    DIRECTION OUTPUT ;
    USE SIGNAL ;
    PORT
      LAYER M4 ;
        RECT  53.916 74.928 54 74.952 ;
    END
  END response_data[16]
  PIN response_data[170]
    DIRECTION OUTPUT ;
    USE SIGNAL ;
    PORT
      LAYER M4 ;
        RECT  53.916 52.08 54 52.104 ;
    END
  END response_data[170]
  PIN response_data[171]
    DIRECTION OUTPUT ;
    USE SIGNAL ;
    PORT
      LAYER M4 ;
        RECT  53.916 52.176 54 52.2 ;
    END
  END response_data[171]
  PIN response_data[172]
    DIRECTION OUTPUT ;
    USE SIGNAL ;
    PORT
      LAYER M4 ;
        RECT  53.916 52.272 54 52.296 ;
    END
  END response_data[172]
  PIN response_data[173]
    DIRECTION OUTPUT ;
    USE SIGNAL ;
    PORT
      LAYER M4 ;
        RECT  53.916 52.368 54 52.392 ;
    END
  END response_data[173]
  PIN response_data[174]
    DIRECTION OUTPUT ;
    USE SIGNAL ;
    PORT
      LAYER M4 ;
        RECT  53.916 52.464 54 52.488 ;
    END
  END response_data[174]
  PIN response_data[175]
    DIRECTION OUTPUT ;
    USE SIGNAL ;
    PORT
      LAYER M4 ;
        RECT  53.916 52.56 54 52.584 ;
    END
  END response_data[175]
  PIN response_data[176]
    DIRECTION OUTPUT ;
    USE SIGNAL ;
    PORT
      LAYER M4 ;
        RECT  53.916 52.656 54 52.68 ;
    END
  END response_data[176]
  PIN response_data[177]
    DIRECTION OUTPUT ;
    USE SIGNAL ;
    PORT
      LAYER M4 ;
        RECT  53.916 52.752 54 52.776 ;
    END
  END response_data[177]
  PIN response_data[178]
    DIRECTION OUTPUT ;
    USE SIGNAL ;
    PORT
      LAYER M4 ;
        RECT  53.916 52.848 54 52.872 ;
    END
  END response_data[178]
  PIN response_data[179]
    DIRECTION OUTPUT ;
    USE SIGNAL ;
    PORT
      LAYER M4 ;
        RECT  53.916 52.944 54 52.968 ;
    END
  END response_data[179]
  PIN response_data[17]
    DIRECTION OUTPUT ;
    USE SIGNAL ;
    PORT
      LAYER M4 ;
        RECT  53.916 75.024 54 75.048 ;
    END
  END response_data[17]
  PIN response_data[180]
    DIRECTION OUTPUT ;
    USE SIGNAL ;
    PORT
      LAYER M4 ;
        RECT  53.916 53.04 54 53.064 ;
    END
  END response_data[180]
  PIN response_data[181]
    DIRECTION OUTPUT ;
    USE SIGNAL ;
    PORT
      LAYER M4 ;
        RECT  53.916 53.136 54 53.16 ;
    END
  END response_data[181]
  PIN response_data[182]
    DIRECTION OUTPUT ;
    USE SIGNAL ;
    PORT
      LAYER M4 ;
        RECT  53.916 53.232 54 53.256 ;
    END
  END response_data[182]
  PIN response_data[183]
    DIRECTION OUTPUT ;
    USE SIGNAL ;
    PORT
      LAYER M4 ;
        RECT  53.916 53.328 54 53.352 ;
    END
  END response_data[183]
  PIN response_data[184]
    DIRECTION OUTPUT ;
    USE SIGNAL ;
    PORT
      LAYER M4 ;
        RECT  53.916 53.424 54 53.448 ;
    END
  END response_data[184]
  PIN response_data[185]
    DIRECTION OUTPUT ;
    USE SIGNAL ;
    PORT
      LAYER M4 ;
        RECT  53.916 53.52 54 53.544 ;
    END
  END response_data[185]
  PIN response_data[186]
    DIRECTION OUTPUT ;
    USE SIGNAL ;
    PORT
      LAYER M4 ;
        RECT  53.916 53.616 54 53.64 ;
    END
  END response_data[186]
  PIN response_data[187]
    DIRECTION OUTPUT ;
    USE SIGNAL ;
    PORT
      LAYER M4 ;
        RECT  53.916 53.712 54 53.736 ;
    END
  END response_data[187]
  PIN response_data[188]
    DIRECTION OUTPUT ;
    USE SIGNAL ;
    PORT
      LAYER M4 ;
        RECT  53.916 53.808 54 53.832 ;
    END
  END response_data[188]
  PIN response_data[189]
    DIRECTION OUTPUT ;
    USE SIGNAL ;
    PORT
      LAYER M4 ;
        RECT  53.916 53.904 54 53.928 ;
    END
  END response_data[189]
  PIN response_data[18]
    DIRECTION OUTPUT ;
    USE SIGNAL ;
    PORT
      LAYER M4 ;
        RECT  53.916 75.12 54 75.144 ;
    END
  END response_data[18]
  PIN response_data[190]
    DIRECTION OUTPUT ;
    USE SIGNAL ;
    PORT
      LAYER M4 ;
        RECT  53.916 54 54 54.024 ;
    END
  END response_data[190]
  PIN response_data[191]
    DIRECTION OUTPUT ;
    USE SIGNAL ;
    PORT
      LAYER M4 ;
        RECT  53.916 54.096 54 54.12 ;
    END
  END response_data[191]
  PIN response_data[192]
    DIRECTION OUTPUT ;
    USE SIGNAL ;
    PORT
      LAYER M4 ;
        RECT  53.916 54.192 54 54.216 ;
    END
  END response_data[192]
  PIN response_data[193]
    DIRECTION OUTPUT ;
    USE SIGNAL ;
    PORT
      LAYER M4 ;
        RECT  53.916 54.288 54 54.312 ;
    END
  END response_data[193]
  PIN response_data[194]
    DIRECTION OUTPUT ;
    USE SIGNAL ;
    PORT
      LAYER M4 ;
        RECT  53.916 54.384 54 54.408 ;
    END
  END response_data[194]
  PIN response_data[195]
    DIRECTION OUTPUT ;
    USE SIGNAL ;
    PORT
      LAYER M4 ;
        RECT  53.916 80.592 54 80.616 ;
    END
  END response_data[195]
  PIN response_data[196]
    DIRECTION OUTPUT ;
    USE SIGNAL ;
    PORT
      LAYER M4 ;
        RECT  53.916 80.688 54 80.712 ;
    END
  END response_data[196]
  PIN response_data[197]
    DIRECTION OUTPUT ;
    USE SIGNAL ;
    PORT
      LAYER M4 ;
        RECT  53.916 80.784 54 80.808 ;
    END
  END response_data[197]
  PIN response_data[198]
    DIRECTION OUTPUT ;
    USE SIGNAL ;
    PORT
      LAYER M4 ;
        RECT  53.916 80.88 54 80.904 ;
    END
  END response_data[198]
  PIN response_data[199]
    DIRECTION OUTPUT ;
    USE SIGNAL ;
    PORT
      LAYER M4 ;
        RECT  53.916 80.976 54 81 ;
    END
  END response_data[199]
  PIN response_data[19]
    DIRECTION OUTPUT ;
    USE SIGNAL ;
    PORT
      LAYER M4 ;
        RECT  53.916 75.216 54 75.24 ;
    END
  END response_data[19]
  PIN response_data[1]
    DIRECTION OUTPUT ;
    USE SIGNAL ;
    PORT
      LAYER M4 ;
        RECT  53.916 61.2 54 61.224 ;
    END
  END response_data[1]
  PIN response_data[200]
    DIRECTION OUTPUT ;
    USE SIGNAL ;
    PORT
      LAYER M4 ;
        RECT  53.916 81.072 54 81.096 ;
    END
  END response_data[200]
  PIN response_data[201]
    DIRECTION OUTPUT ;
    USE SIGNAL ;
    PORT
      LAYER M4 ;
        RECT  53.916 81.168 54 81.192 ;
    END
  END response_data[201]
  PIN response_data[202]
    DIRECTION OUTPUT ;
    USE SIGNAL ;
    PORT
      LAYER M4 ;
        RECT  53.916 81.264 54 81.288 ;
    END
  END response_data[202]
  PIN response_data[203]
    DIRECTION OUTPUT ;
    USE SIGNAL ;
    PORT
      LAYER M4 ;
        RECT  53.916 81.36 54 81.384 ;
    END
  END response_data[203]
  PIN response_data[204]
    DIRECTION OUTPUT ;
    USE SIGNAL ;
    PORT
      LAYER M4 ;
        RECT  53.916 81.456 54 81.48 ;
    END
  END response_data[204]
  PIN response_data[205]
    DIRECTION OUTPUT ;
    USE SIGNAL ;
    PORT
      LAYER M4 ;
        RECT  53.916 81.552 54 81.576 ;
    END
  END response_data[205]
  PIN response_data[206]
    DIRECTION OUTPUT ;
    USE SIGNAL ;
    PORT
      LAYER M4 ;
        RECT  53.916 81.648 54 81.672 ;
    END
  END response_data[206]
  PIN response_data[207]
    DIRECTION OUTPUT ;
    USE SIGNAL ;
    PORT
      LAYER M4 ;
        RECT  53.916 81.744 54 81.768 ;
    END
  END response_data[207]
  PIN response_data[208]
    DIRECTION OUTPUT ;
    USE SIGNAL ;
    PORT
      LAYER M4 ;
        RECT  53.916 81.84 54 81.864 ;
    END
  END response_data[208]
  PIN response_data[209]
    DIRECTION OUTPUT ;
    USE SIGNAL ;
    PORT
      LAYER M4 ;
        RECT  53.916 81.936 54 81.96 ;
    END
  END response_data[209]
  PIN response_data[20]
    DIRECTION OUTPUT ;
    USE SIGNAL ;
    PORT
      LAYER M4 ;
        RECT  53.916 75.312 54 75.336 ;
    END
  END response_data[20]
  PIN response_data[210]
    DIRECTION OUTPUT ;
    USE SIGNAL ;
    PORT
      LAYER M4 ;
        RECT  53.916 82.032 54 82.056 ;
    END
  END response_data[210]
  PIN response_data[211]
    DIRECTION OUTPUT ;
    USE SIGNAL ;
    PORT
      LAYER M4 ;
        RECT  53.916 82.128 54 82.152 ;
    END
  END response_data[211]
  PIN response_data[212]
    DIRECTION OUTPUT ;
    USE SIGNAL ;
    PORT
      LAYER M4 ;
        RECT  53.916 82.224 54 82.248 ;
    END
  END response_data[212]
  PIN response_data[213]
    DIRECTION OUTPUT ;
    USE SIGNAL ;
    PORT
      LAYER M4 ;
        RECT  53.916 82.32 54 82.344 ;
    END
  END response_data[213]
  PIN response_data[214]
    DIRECTION OUTPUT ;
    USE SIGNAL ;
    PORT
      LAYER M4 ;
        RECT  53.916 82.416 54 82.44 ;
    END
  END response_data[214]
  PIN response_data[215]
    DIRECTION OUTPUT ;
    USE SIGNAL ;
    PORT
      LAYER M4 ;
        RECT  53.916 82.512 54 82.536 ;
    END
  END response_data[215]
  PIN response_data[216]
    DIRECTION OUTPUT ;
    USE SIGNAL ;
    PORT
      LAYER M4 ;
        RECT  53.916 82.608 54 82.632 ;
    END
  END response_data[216]
  PIN response_data[217]
    DIRECTION OUTPUT ;
    USE SIGNAL ;
    PORT
      LAYER M4 ;
        RECT  53.916 82.704 54 82.728 ;
    END
  END response_data[217]
  PIN response_data[218]
    DIRECTION OUTPUT ;
    USE SIGNAL ;
    PORT
      LAYER M4 ;
        RECT  53.916 82.8 54 82.824 ;
    END
  END response_data[218]
  PIN response_data[219]
    DIRECTION OUTPUT ;
    USE SIGNAL ;
    PORT
      LAYER M4 ;
        RECT  53.916 82.896 54 82.92 ;
    END
  END response_data[219]
  PIN response_data[21]
    DIRECTION OUTPUT ;
    USE SIGNAL ;
    PORT
      LAYER M4 ;
        RECT  53.916 75.408 54 75.432 ;
    END
  END response_data[21]
  PIN response_data[220]
    DIRECTION OUTPUT ;
    USE SIGNAL ;
    PORT
      LAYER M4 ;
        RECT  53.916 82.992 54 83.016 ;
    END
  END response_data[220]
  PIN response_data[221]
    DIRECTION OUTPUT ;
    USE SIGNAL ;
    PORT
      LAYER M4 ;
        RECT  53.916 83.088 54 83.112 ;
    END
  END response_data[221]
  PIN response_data[222]
    DIRECTION OUTPUT ;
    USE SIGNAL ;
    PORT
      LAYER M4 ;
        RECT  53.916 83.184 54 83.208 ;
    END
  END response_data[222]
  PIN response_data[223]
    DIRECTION OUTPUT ;
    USE SIGNAL ;
    PORT
      LAYER M4 ;
        RECT  53.916 83.28 54 83.304 ;
    END
  END response_data[223]
  PIN response_data[224]
    DIRECTION OUTPUT ;
    USE SIGNAL ;
    PORT
      LAYER M4 ;
        RECT  53.916 83.376 54 83.4 ;
    END
  END response_data[224]
  PIN response_data[225]
    DIRECTION OUTPUT ;
    USE SIGNAL ;
    PORT
      LAYER M4 ;
        RECT  53.916 83.472 54 83.496 ;
    END
  END response_data[225]
  PIN response_data[226]
    DIRECTION OUTPUT ;
    USE SIGNAL ;
    PORT
      LAYER M4 ;
        RECT  53.916 83.568 54 83.592 ;
    END
  END response_data[226]
  PIN response_data[227]
    DIRECTION OUTPUT ;
    USE SIGNAL ;
    PORT
      LAYER M4 ;
        RECT  53.916 48.336 54 48.36 ;
    END
  END response_data[227]
  PIN response_data[228]
    DIRECTION OUTPUT ;
    USE SIGNAL ;
    PORT
      LAYER M4 ;
        RECT  53.916 48.432 54 48.456 ;
    END
  END response_data[228]
  PIN response_data[229]
    DIRECTION OUTPUT ;
    USE SIGNAL ;
    PORT
      LAYER M4 ;
        RECT  53.916 48.528 54 48.552 ;
    END
  END response_data[229]
  PIN response_data[22]
    DIRECTION OUTPUT ;
    USE SIGNAL ;
    PORT
      LAYER M4 ;
        RECT  53.916 75.504 54 75.528 ;
    END
  END response_data[22]
  PIN response_data[230]
    DIRECTION OUTPUT ;
    USE SIGNAL ;
    PORT
      LAYER M4 ;
        RECT  53.916 48.624 54 48.648 ;
    END
  END response_data[230]
  PIN response_data[231]
    DIRECTION OUTPUT ;
    USE SIGNAL ;
    PORT
      LAYER M4 ;
        RECT  53.916 48.72 54 48.744 ;
    END
  END response_data[231]
  PIN response_data[232]
    DIRECTION OUTPUT ;
    USE SIGNAL ;
    PORT
      LAYER M4 ;
        RECT  53.916 48.816 54 48.84 ;
    END
  END response_data[232]
  PIN response_data[233]
    DIRECTION OUTPUT ;
    USE SIGNAL ;
    PORT
      LAYER M4 ;
        RECT  53.916 48.912 54 48.936 ;
    END
  END response_data[233]
  PIN response_data[234]
    DIRECTION OUTPUT ;
    USE SIGNAL ;
    PORT
      LAYER M4 ;
        RECT  53.916 49.008 54 49.032 ;
    END
  END response_data[234]
  PIN response_data[235]
    DIRECTION OUTPUT ;
    USE SIGNAL ;
    PORT
      LAYER M4 ;
        RECT  53.916 49.104 54 49.128 ;
    END
  END response_data[235]
  PIN response_data[236]
    DIRECTION OUTPUT ;
    USE SIGNAL ;
    PORT
      LAYER M4 ;
        RECT  53.916 49.2 54 49.224 ;
    END
  END response_data[236]
  PIN response_data[237]
    DIRECTION OUTPUT ;
    USE SIGNAL ;
    PORT
      LAYER M4 ;
        RECT  53.916 49.296 54 49.32 ;
    END
  END response_data[237]
  PIN response_data[238]
    DIRECTION OUTPUT ;
    USE SIGNAL ;
    PORT
      LAYER M4 ;
        RECT  53.916 49.392 54 49.416 ;
    END
  END response_data[238]
  PIN response_data[239]
    DIRECTION OUTPUT ;
    USE SIGNAL ;
    PORT
      LAYER M4 ;
        RECT  53.916 49.488 54 49.512 ;
    END
  END response_data[239]
  PIN response_data[23]
    DIRECTION OUTPUT ;
    USE SIGNAL ;
    PORT
      LAYER M4 ;
        RECT  53.916 75.6 54 75.624 ;
    END
  END response_data[23]
  PIN response_data[240]
    DIRECTION OUTPUT ;
    USE SIGNAL ;
    PORT
      LAYER M4 ;
        RECT  53.916 49.584 54 49.608 ;
    END
  END response_data[240]
  PIN response_data[241]
    DIRECTION OUTPUT ;
    USE SIGNAL ;
    PORT
      LAYER M4 ;
        RECT  53.916 49.68 54 49.704 ;
    END
  END response_data[241]
  PIN response_data[242]
    DIRECTION OUTPUT ;
    USE SIGNAL ;
    PORT
      LAYER M4 ;
        RECT  53.916 49.776 54 49.8 ;
    END
  END response_data[242]
  PIN response_data[243]
    DIRECTION OUTPUT ;
    USE SIGNAL ;
    PORT
      LAYER M4 ;
        RECT  53.916 49.872 54 49.896 ;
    END
  END response_data[243]
  PIN response_data[244]
    DIRECTION OUTPUT ;
    USE SIGNAL ;
    PORT
      LAYER M4 ;
        RECT  53.916 49.968 54 49.992 ;
    END
  END response_data[244]
  PIN response_data[245]
    DIRECTION OUTPUT ;
    USE SIGNAL ;
    PORT
      LAYER M4 ;
        RECT  53.916 50.064 54 50.088 ;
    END
  END response_data[245]
  PIN response_data[246]
    DIRECTION OUTPUT ;
    USE SIGNAL ;
    PORT
      LAYER M4 ;
        RECT  53.916 50.16 54 50.184 ;
    END
  END response_data[246]
  PIN response_data[247]
    DIRECTION OUTPUT ;
    USE SIGNAL ;
    PORT
      LAYER M4 ;
        RECT  53.916 50.256 54 50.28 ;
    END
  END response_data[247]
  PIN response_data[248]
    DIRECTION OUTPUT ;
    USE SIGNAL ;
    PORT
      LAYER M4 ;
        RECT  53.916 50.352 54 50.376 ;
    END
  END response_data[248]
  PIN response_data[249]
    DIRECTION OUTPUT ;
    USE SIGNAL ;
    PORT
      LAYER M4 ;
        RECT  53.916 50.448 54 50.472 ;
    END
  END response_data[249]
  PIN response_data[24]
    DIRECTION OUTPUT ;
    USE SIGNAL ;
    PORT
      LAYER M4 ;
        RECT  53.916 75.696 54 75.72 ;
    END
  END response_data[24]
  PIN response_data[250]
    DIRECTION OUTPUT ;
    USE SIGNAL ;
    PORT
      LAYER M4 ;
        RECT  53.916 50.544 54 50.568 ;
    END
  END response_data[250]
  PIN response_data[251]
    DIRECTION OUTPUT ;
    USE SIGNAL ;
    PORT
      LAYER M4 ;
        RECT  53.916 50.64 54 50.664 ;
    END
  END response_data[251]
  PIN response_data[252]
    DIRECTION OUTPUT ;
    USE SIGNAL ;
    PORT
      LAYER M4 ;
        RECT  53.916 50.736 54 50.76 ;
    END
  END response_data[252]
  PIN response_data[253]
    DIRECTION OUTPUT ;
    USE SIGNAL ;
    PORT
      LAYER M4 ;
        RECT  53.916 50.832 54 50.856 ;
    END
  END response_data[253]
  PIN response_data[254]
    DIRECTION OUTPUT ;
    USE SIGNAL ;
    PORT
      LAYER M4 ;
        RECT  53.916 50.928 54 50.952 ;
    END
  END response_data[254]
  PIN response_data[255]
    DIRECTION OUTPUT ;
    USE SIGNAL ;
    PORT
      LAYER M4 ;
        RECT  53.916 51.024 54 51.048 ;
    END
  END response_data[255]
  PIN response_data[25]
    DIRECTION OUTPUT ;
    USE SIGNAL ;
    PORT
      LAYER M4 ;
        RECT  53.916 75.792 54 75.816 ;
    END
  END response_data[25]
  PIN response_data[26]
    DIRECTION OUTPUT ;
    USE SIGNAL ;
    PORT
      LAYER M4 ;
        RECT  53.916 75.888 54 75.912 ;
    END
  END response_data[26]
  PIN response_data[27]
    DIRECTION OUTPUT ;
    USE SIGNAL ;
    PORT
      LAYER M4 ;
        RECT  53.916 75.984 54 76.008 ;
    END
  END response_data[27]
  PIN response_data[28]
    DIRECTION OUTPUT ;
    USE SIGNAL ;
    PORT
      LAYER M4 ;
        RECT  53.916 76.08 54 76.104 ;
    END
  END response_data[28]
  PIN response_data[29]
    DIRECTION OUTPUT ;
    USE SIGNAL ;
    PORT
      LAYER M4 ;
        RECT  53.916 76.176 54 76.2 ;
    END
  END response_data[29]
  PIN response_data[2]
    DIRECTION OUTPUT ;
    USE SIGNAL ;
    PORT
      LAYER M4 ;
        RECT  53.916 61.296 54 61.32 ;
    END
  END response_data[2]
  PIN response_data[30]
    DIRECTION OUTPUT ;
    USE SIGNAL ;
    PORT
      LAYER M4 ;
        RECT  53.916 76.272 54 76.296 ;
    END
  END response_data[30]
  PIN response_data[31]
    DIRECTION OUTPUT ;
    USE SIGNAL ;
    PORT
      LAYER M4 ;
        RECT  53.916 76.368 54 76.392 ;
    END
  END response_data[31]
  PIN response_data[32]
    DIRECTION OUTPUT ;
    USE SIGNAL ;
    PORT
      LAYER M4 ;
        RECT  53.916 76.464 54 76.488 ;
    END
  END response_data[32]
  PIN response_data[33]
    DIRECTION OUTPUT ;
    USE SIGNAL ;
    PORT
      LAYER M4 ;
        RECT  53.916 76.56 54 76.584 ;
    END
  END response_data[33]
  PIN response_data[34]
    DIRECTION OUTPUT ;
    USE SIGNAL ;
    PORT
      LAYER M4 ;
        RECT  53.916 76.656 54 76.68 ;
    END
  END response_data[34]
  PIN response_data[35]
    DIRECTION OUTPUT ;
    USE SIGNAL ;
    PORT
      LAYER M4 ;
        RECT  53.916 61.392 54 61.416 ;
    END
  END response_data[35]
  PIN response_data[36]
    DIRECTION OUTPUT ;
    USE SIGNAL ;
    PORT
      LAYER M4 ;
        RECT  53.916 61.488 54 61.512 ;
    END
  END response_data[36]
  PIN response_data[37]
    DIRECTION OUTPUT ;
    USE SIGNAL ;
    PORT
      LAYER M4 ;
        RECT  53.916 61.584 54 61.608 ;
    END
  END response_data[37]
  PIN response_data[38]
    DIRECTION OUTPUT ;
    USE SIGNAL ;
    PORT
      LAYER M4 ;
        RECT  53.916 61.68 54 61.704 ;
    END
  END response_data[38]
  PIN response_data[39]
    DIRECTION OUTPUT ;
    USE SIGNAL ;
    PORT
      LAYER M4 ;
        RECT  53.916 61.776 54 61.8 ;
    END
  END response_data[39]
  PIN response_data[3]
    DIRECTION OUTPUT ;
    USE SIGNAL ;
    PORT
      LAYER M4 ;
        RECT  53.916 73.68 54 73.704 ;
    END
  END response_data[3]
  PIN response_data[40]
    DIRECTION OUTPUT ;
    USE SIGNAL ;
    PORT
      LAYER M4 ;
        RECT  53.916 61.872 54 61.896 ;
    END
  END response_data[40]
  PIN response_data[41]
    DIRECTION OUTPUT ;
    USE SIGNAL ;
    PORT
      LAYER M4 ;
        RECT  53.916 61.968 54 61.992 ;
    END
  END response_data[41]
  PIN response_data[42]
    DIRECTION OUTPUT ;
    USE SIGNAL ;
    PORT
      LAYER M4 ;
        RECT  53.916 62.064 54 62.088 ;
    END
  END response_data[42]
  PIN response_data[43]
    DIRECTION OUTPUT ;
    USE SIGNAL ;
    PORT
      LAYER M4 ;
        RECT  53.916 62.16 54 62.184 ;
    END
  END response_data[43]
  PIN response_data[44]
    DIRECTION OUTPUT ;
    USE SIGNAL ;
    PORT
      LAYER M4 ;
        RECT  53.916 62.256 54 62.28 ;
    END
  END response_data[44]
  PIN response_data[45]
    DIRECTION OUTPUT ;
    USE SIGNAL ;
    PORT
      LAYER M4 ;
        RECT  53.916 62.352 54 62.376 ;
    END
  END response_data[45]
  PIN response_data[46]
    DIRECTION OUTPUT ;
    USE SIGNAL ;
    PORT
      LAYER M4 ;
        RECT  53.916 62.448 54 62.472 ;
    END
  END response_data[46]
  PIN response_data[47]
    DIRECTION OUTPUT ;
    USE SIGNAL ;
    PORT
      LAYER M4 ;
        RECT  53.916 62.544 54 62.568 ;
    END
  END response_data[47]
  PIN response_data[48]
    DIRECTION OUTPUT ;
    USE SIGNAL ;
    PORT
      LAYER M4 ;
        RECT  53.916 62.64 54 62.664 ;
    END
  END response_data[48]
  PIN response_data[49]
    DIRECTION OUTPUT ;
    USE SIGNAL ;
    PORT
      LAYER M4 ;
        RECT  53.916 62.736 54 62.76 ;
    END
  END response_data[49]
  PIN response_data[4]
    DIRECTION OUTPUT ;
    USE SIGNAL ;
    PORT
      LAYER M4 ;
        RECT  53.916 73.776 54 73.8 ;
    END
  END response_data[4]
  PIN response_data[50]
    DIRECTION OUTPUT ;
    USE SIGNAL ;
    PORT
      LAYER M4 ;
        RECT  53.916 62.832 54 62.856 ;
    END
  END response_data[50]
  PIN response_data[51]
    DIRECTION OUTPUT ;
    USE SIGNAL ;
    PORT
      LAYER M4 ;
        RECT  53.916 62.928 54 62.952 ;
    END
  END response_data[51]
  PIN response_data[52]
    DIRECTION OUTPUT ;
    USE SIGNAL ;
    PORT
      LAYER M4 ;
        RECT  53.916 63.024 54 63.048 ;
    END
  END response_data[52]
  PIN response_data[53]
    DIRECTION OUTPUT ;
    USE SIGNAL ;
    PORT
      LAYER M4 ;
        RECT  53.916 63.12 54 63.144 ;
    END
  END response_data[53]
  PIN response_data[54]
    DIRECTION OUTPUT ;
    USE SIGNAL ;
    PORT
      LAYER M4 ;
        RECT  53.916 63.216 54 63.24 ;
    END
  END response_data[54]
  PIN response_data[55]
    DIRECTION OUTPUT ;
    USE SIGNAL ;
    PORT
      LAYER M4 ;
        RECT  53.916 63.312 54 63.336 ;
    END
  END response_data[55]
  PIN response_data[56]
    DIRECTION OUTPUT ;
    USE SIGNAL ;
    PORT
      LAYER M4 ;
        RECT  53.916 63.408 54 63.432 ;
    END
  END response_data[56]
  PIN response_data[57]
    DIRECTION OUTPUT ;
    USE SIGNAL ;
    PORT
      LAYER M4 ;
        RECT  53.916 63.504 54 63.528 ;
    END
  END response_data[57]
  PIN response_data[58]
    DIRECTION OUTPUT ;
    USE SIGNAL ;
    PORT
      LAYER M4 ;
        RECT  53.916 63.6 54 63.624 ;
    END
  END response_data[58]
  PIN response_data[59]
    DIRECTION OUTPUT ;
    USE SIGNAL ;
    PORT
      LAYER M4 ;
        RECT  53.916 63.696 54 63.72 ;
    END
  END response_data[59]
  PIN response_data[5]
    DIRECTION OUTPUT ;
    USE SIGNAL ;
    PORT
      LAYER M4 ;
        RECT  53.916 73.872 54 73.896 ;
    END
  END response_data[5]
  PIN response_data[60]
    DIRECTION OUTPUT ;
    USE SIGNAL ;
    PORT
      LAYER M4 ;
        RECT  53.916 63.792 54 63.816 ;
    END
  END response_data[60]
  PIN response_data[61]
    DIRECTION OUTPUT ;
    USE SIGNAL ;
    PORT
      LAYER M4 ;
        RECT  53.916 63.888 54 63.912 ;
    END
  END response_data[61]
  PIN response_data[62]
    DIRECTION OUTPUT ;
    USE SIGNAL ;
    PORT
      LAYER M4 ;
        RECT  53.916 63.984 54 64.008 ;
    END
  END response_data[62]
  PIN response_data[63]
    DIRECTION OUTPUT ;
    USE SIGNAL ;
    PORT
      LAYER M4 ;
        RECT  53.916 64.08 54 64.104 ;
    END
  END response_data[63]
  PIN response_data[64]
    DIRECTION OUTPUT ;
    USE SIGNAL ;
    PORT
      LAYER M4 ;
        RECT  53.916 64.176 54 64.2 ;
    END
  END response_data[64]
  PIN response_data[65]
    DIRECTION OUTPUT ;
    USE SIGNAL ;
    PORT
      LAYER M4 ;
        RECT  53.916 64.272 54 64.296 ;
    END
  END response_data[65]
  PIN response_data[66]
    DIRECTION OUTPUT ;
    USE SIGNAL ;
    PORT
      LAYER M4 ;
        RECT  53.916 64.368 54 64.392 ;
    END
  END response_data[66]
  PIN response_data[67]
    DIRECTION OUTPUT ;
    USE SIGNAL ;
    PORT
      LAYER M4 ;
        RECT  53.916 70.608 54 70.632 ;
    END
  END response_data[67]
  PIN response_data[68]
    DIRECTION OUTPUT ;
    USE SIGNAL ;
    PORT
      LAYER M4 ;
        RECT  53.916 70.704 54 70.728 ;
    END
  END response_data[68]
  PIN response_data[69]
    DIRECTION OUTPUT ;
    USE SIGNAL ;
    PORT
      LAYER M4 ;
        RECT  53.916 70.8 54 70.824 ;
    END
  END response_data[69]
  PIN response_data[6]
    DIRECTION OUTPUT ;
    USE SIGNAL ;
    PORT
      LAYER M4 ;
        RECT  53.916 73.968 54 73.992 ;
    END
  END response_data[6]
  PIN response_data[70]
    DIRECTION OUTPUT ;
    USE SIGNAL ;
    PORT
      LAYER M4 ;
        RECT  53.916 70.896 54 70.92 ;
    END
  END response_data[70]
  PIN response_data[71]
    DIRECTION OUTPUT ;
    USE SIGNAL ;
    PORT
      LAYER M4 ;
        RECT  53.916 70.992 54 71.016 ;
    END
  END response_data[71]
  PIN response_data[72]
    DIRECTION OUTPUT ;
    USE SIGNAL ;
    PORT
      LAYER M4 ;
        RECT  53.916 71.088 54 71.112 ;
    END
  END response_data[72]
  PIN response_data[73]
    DIRECTION OUTPUT ;
    USE SIGNAL ;
    PORT
      LAYER M4 ;
        RECT  53.916 71.184 54 71.208 ;
    END
  END response_data[73]
  PIN response_data[74]
    DIRECTION OUTPUT ;
    USE SIGNAL ;
    PORT
      LAYER M4 ;
        RECT  53.916 71.28 54 71.304 ;
    END
  END response_data[74]
  PIN response_data[75]
    DIRECTION OUTPUT ;
    USE SIGNAL ;
    PORT
      LAYER M4 ;
        RECT  53.916 71.376 54 71.4 ;
    END
  END response_data[75]
  PIN response_data[76]
    DIRECTION OUTPUT ;
    USE SIGNAL ;
    PORT
      LAYER M4 ;
        RECT  53.916 71.472 54 71.496 ;
    END
  END response_data[76]
  PIN response_data[77]
    DIRECTION OUTPUT ;
    USE SIGNAL ;
    PORT
      LAYER M4 ;
        RECT  53.916 71.568 54 71.592 ;
    END
  END response_data[77]
  PIN response_data[78]
    DIRECTION OUTPUT ;
    USE SIGNAL ;
    PORT
      LAYER M4 ;
        RECT  53.916 71.664 54 71.688 ;
    END
  END response_data[78]
  PIN response_data[79]
    DIRECTION OUTPUT ;
    USE SIGNAL ;
    PORT
      LAYER M4 ;
        RECT  53.916 71.76 54 71.784 ;
    END
  END response_data[79]
  PIN response_data[7]
    DIRECTION OUTPUT ;
    USE SIGNAL ;
    PORT
      LAYER M4 ;
        RECT  53.916 74.064 54 74.088 ;
    END
  END response_data[7]
  PIN response_data[80]
    DIRECTION OUTPUT ;
    USE SIGNAL ;
    PORT
      LAYER M4 ;
        RECT  53.916 71.856 54 71.88 ;
    END
  END response_data[80]
  PIN response_data[81]
    DIRECTION OUTPUT ;
    USE SIGNAL ;
    PORT
      LAYER M4 ;
        RECT  53.916 71.952 54 71.976 ;
    END
  END response_data[81]
  PIN response_data[82]
    DIRECTION OUTPUT ;
    USE SIGNAL ;
    PORT
      LAYER M4 ;
        RECT  53.916 72.048 54 72.072 ;
    END
  END response_data[82]
  PIN response_data[83]
    DIRECTION OUTPUT ;
    USE SIGNAL ;
    PORT
      LAYER M4 ;
        RECT  53.916 72.144 54 72.168 ;
    END
  END response_data[83]
  PIN response_data[84]
    DIRECTION OUTPUT ;
    USE SIGNAL ;
    PORT
      LAYER M4 ;
        RECT  53.916 72.24 54 72.264 ;
    END
  END response_data[84]
  PIN response_data[85]
    DIRECTION OUTPUT ;
    USE SIGNAL ;
    PORT
      LAYER M4 ;
        RECT  53.916 72.336 54 72.36 ;
    END
  END response_data[85]
  PIN response_data[86]
    DIRECTION OUTPUT ;
    USE SIGNAL ;
    PORT
      LAYER M4 ;
        RECT  53.916 72.432 54 72.456 ;
    END
  END response_data[86]
  PIN response_data[87]
    DIRECTION OUTPUT ;
    USE SIGNAL ;
    PORT
      LAYER M4 ;
        RECT  53.916 72.528 54 72.552 ;
    END
  END response_data[87]
  PIN response_data[88]
    DIRECTION OUTPUT ;
    USE SIGNAL ;
    PORT
      LAYER M4 ;
        RECT  53.916 72.624 54 72.648 ;
    END
  END response_data[88]
  PIN response_data[89]
    DIRECTION OUTPUT ;
    USE SIGNAL ;
    PORT
      LAYER M4 ;
        RECT  53.916 72.72 54 72.744 ;
    END
  END response_data[89]
  PIN response_data[8]
    DIRECTION OUTPUT ;
    USE SIGNAL ;
    PORT
      LAYER M4 ;
        RECT  53.916 74.16 54 74.184 ;
    END
  END response_data[8]
  PIN response_data[90]
    DIRECTION OUTPUT ;
    USE SIGNAL ;
    PORT
      LAYER M4 ;
        RECT  53.916 72.816 54 72.84 ;
    END
  END response_data[90]
  PIN response_data[91]
    DIRECTION OUTPUT ;
    USE SIGNAL ;
    PORT
      LAYER M4 ;
        RECT  53.916 72.912 54 72.936 ;
    END
  END response_data[91]
  PIN response_data[92]
    DIRECTION OUTPUT ;
    USE SIGNAL ;
    PORT
      LAYER M4 ;
        RECT  53.916 73.008 54 73.032 ;
    END
  END response_data[92]
  PIN response_data[93]
    DIRECTION OUTPUT ;
    USE SIGNAL ;
    PORT
      LAYER M4 ;
        RECT  53.916 73.104 54 73.128 ;
    END
  END response_data[93]
  PIN response_data[94]
    DIRECTION OUTPUT ;
    USE SIGNAL ;
    PORT
      LAYER M4 ;
        RECT  53.916 73.2 54 73.224 ;
    END
  END response_data[94]
  PIN response_data[95]
    DIRECTION OUTPUT ;
    USE SIGNAL ;
    PORT
      LAYER M4 ;
        RECT  53.916 73.296 54 73.32 ;
    END
  END response_data[95]
  PIN response_data[96]
    DIRECTION OUTPUT ;
    USE SIGNAL ;
    PORT
      LAYER M4 ;
        RECT  53.916 73.392 54 73.416 ;
    END
  END response_data[96]
  PIN response_data[97]
    DIRECTION OUTPUT ;
    USE SIGNAL ;
    PORT
      LAYER M4 ;
        RECT  53.916 73.488 54 73.512 ;
    END
  END response_data[97]
  PIN response_data[98]
    DIRECTION OUTPUT ;
    USE SIGNAL ;
    PORT
      LAYER M4 ;
        RECT  53.916 73.584 54 73.608 ;
    END
  END response_data[98]
  PIN response_data[99]
    DIRECTION OUTPUT ;
    USE SIGNAL ;
    PORT
      LAYER M4 ;
        RECT  53.916 54.48 54 54.504 ;
    END
  END response_data[99]
  PIN response_data[9]
    DIRECTION OUTPUT ;
    USE SIGNAL ;
    PORT
      LAYER M4 ;
        RECT  53.916 74.256 54 74.28 ;
    END
  END response_data[9]
  PIN response_v[0]
    DIRECTION OUTPUT ;
    USE SIGNAL ;
    PORT
      LAYER M4 ;
        RECT  53.916 51.12 54 51.144 ;
    END
  END response_v[0]
  PIN response_v[1]
    DIRECTION OUTPUT ;
    USE SIGNAL ;
    PORT
      LAYER M4 ;
        RECT  53.916 51.216 54 51.24 ;
    END
  END response_v[1]
  PIN response_v[2]
    DIRECTION OUTPUT ;
    USE SIGNAL ;
    PORT
      LAYER M4 ;
        RECT  53.916 51.312 54 51.336 ;
    END
  END response_v[2]
  PIN response_v[3]
    DIRECTION OUTPUT ;
    USE SIGNAL ;
    PORT
      LAYER M4 ;
        RECT  53.916 76.752 54 76.776 ;
    END
  END response_v[3]
  PIN rst_n
    DIRECTION INPUT ;
    USE SIGNAL ;
    PORT
      LAYER M5 ;
        RECT  16.272 129.516 16.296 129.6 ;
    END
  END rst_n
  PIN VDD
    DIRECTION INOUT ;
    USE POWER ;
    PORT
      LAYER M5 ;
        RECT  51.192 2.151 51.312 127.449 ;
        RECT  45.792 2.151 45.912 127.449 ;
        RECT  40.392 2.151 40.512 127.449 ;
        RECT  34.992 2.151 35.112 127.449 ;
        RECT  29.592 2.151 29.712 127.449 ;
        RECT  24.192 2.151 24.312 127.449 ;
        RECT  18.792 2.151 18.912 127.449 ;
        RECT  13.392 2.151 13.512 127.449 ;
        RECT  7.992 2.151 8.112 127.449 ;
        RECT  2.592 2.151 2.712 127.449 ;
    END
  END VDD
  PIN VSS
    DIRECTION INOUT ;
    USE GROUND ;
    PORT
      LAYER M5 ;
        RECT  51 2.137 51.12 127.463 ;
        RECT  45.6 2.137 45.72 127.463 ;
        RECT  40.2 2.137 40.32 127.463 ;
        RECT  34.8 2.137 34.92 127.463 ;
        RECT  29.4 2.137 29.52 127.463 ;
        RECT  24 2.137 24.12 127.463 ;
        RECT  18.6 2.137 18.72 127.463 ;
        RECT  13.2 2.137 13.32 127.463 ;
        RECT  7.8 2.137 7.92 127.463 ;
        RECT  2.4 2.137 2.52 127.463 ;
    END
  END VSS
  OBS
    LAYER RVTN ;
     RECT  2.16 2.16 51.84 2.295 ;
     RECT  2.16 2.565 51.84 2.835 ;
     RECT  2.16 3.105 51.84 3.375 ;
     RECT  2.16 3.645 51.84 3.915 ;
     RECT  2.16 4.185 51.84 4.455 ;
     RECT  2.16 4.725 51.84 4.995 ;
     RECT  2.16 5.265 51.84 5.535 ;
     RECT  2.16 5.805 51.84 6.075 ;
     RECT  2.16 6.345 51.84 6.615 ;
     RECT  2.16 6.885 51.84 7.155 ;
     RECT  2.16 7.425 51.84 7.695 ;
     RECT  2.16 7.965 51.84 8.235 ;
     RECT  2.16 8.505 51.84 8.775 ;
     RECT  2.16 9.045 51.84 9.315 ;
     RECT  2.16 9.585 51.84 9.855 ;
     RECT  2.16 10.125 51.84 10.395 ;
     RECT  2.16 10.665 51.84 10.935 ;
     RECT  2.16 11.205 51.84 11.475 ;
     RECT  2.16 11.745 51.84 12.015 ;
     RECT  2.16 12.285 51.84 12.555 ;
     RECT  2.16 12.825 51.84 13.095 ;
     RECT  2.16 13.365 51.84 13.635 ;
     RECT  2.16 13.905 51.84 14.175 ;
     RECT  2.16 14.445 51.84 14.715 ;
     RECT  2.16 14.985 51.84 15.255 ;
     RECT  2.16 15.525 51.84 15.795 ;
     RECT  2.16 16.065 51.84 16.335 ;
     RECT  2.16 16.605 51.84 16.875 ;
     RECT  2.16 17.145 51.84 17.415 ;
     RECT  2.16 17.685 51.84 17.955 ;
     RECT  2.16 18.225 51.84 18.495 ;
     RECT  2.16 18.765 51.84 19.035 ;
     RECT  2.16 19.305 51.84 19.575 ;
     RECT  2.16 19.845 51.84 20.115 ;
     RECT  2.16 20.385 51.84 20.655 ;
     RECT  2.16 20.925 51.84 21.195 ;
     RECT  2.16 21.465 51.84 21.735 ;
     RECT  2.16 22.005 51.84 22.275 ;
     RECT  2.16 22.545 51.84 22.815 ;
     RECT  2.16 23.085 51.84 23.355 ;
     RECT  2.16 23.625 51.84 23.895 ;
     RECT  2.16 24.165 51.84 24.435 ;
     RECT  2.16 24.705 51.84 24.975 ;
     RECT  2.16 25.245 51.84 25.515 ;
     RECT  2.16 25.785 51.84 26.055 ;
     RECT  2.16 26.325 51.84 26.595 ;
     RECT  2.16 26.865 51.84 27.135 ;
     RECT  2.16 27.405 51.84 27.675 ;
     RECT  2.16 27.945 51.84 28.215 ;
     RECT  2.16 28.485 51.84 28.755 ;
     RECT  2.16 29.025 51.84 29.295 ;
     RECT  2.16 29.565 51.84 29.835 ;
     RECT  2.16 30.105 51.84 30.375 ;
     RECT  2.16 30.645 51.84 30.915 ;
     RECT  2.16 31.185 51.84 31.455 ;
     RECT  2.16 31.725 51.84 31.995 ;
     RECT  2.16 32.265 51.84 32.535 ;
     RECT  2.16 32.805 51.84 33.075 ;
     RECT  2.16 33.345 51.84 33.615 ;
     RECT  2.16 33.885 51.84 34.155 ;
     RECT  2.16 34.425 51.84 34.695 ;
     RECT  2.16 34.965 51.84 35.235 ;
     RECT  2.16 35.505 51.84 35.775 ;
     RECT  2.16 36.045 51.84 36.315 ;
     RECT  2.16 36.585 51.84 36.855 ;
     RECT  2.16 37.125 51.84 37.395 ;
     RECT  2.16 37.665 51.84 37.935 ;
     RECT  2.16 38.205 51.84 38.475 ;
     RECT  2.16 38.745 51.84 39.015 ;
     RECT  2.16 39.285 51.84 39.555 ;
     RECT  2.16 39.825 51.84 40.095 ;
     RECT  2.16 40.365 51.84 40.635 ;
     RECT  2.16 40.905 51.84 41.175 ;
     RECT  2.16 41.445 51.84 41.715 ;
     RECT  2.16 41.985 51.84 42.255 ;
     RECT  2.16 42.525 51.84 42.795 ;
     RECT  2.16 43.065 51.84 43.335 ;
     RECT  2.16 43.605 51.84 43.875 ;
     RECT  2.16 44.145 51.84 44.415 ;
     RECT  2.16 44.685 51.84 44.955 ;
     RECT  2.16 45.225 51.84 45.495 ;
     RECT  2.16 45.765 51.84 46.035 ;
     RECT  2.16 46.305 51.84 46.575 ;
     RECT  2.16 46.845 51.84 47.115 ;
     RECT  2.16 47.385 51.84 47.655 ;
     RECT  2.16 47.925 51.84 48.195 ;
     RECT  2.16 48.465 51.84 48.735 ;
     RECT  2.16 49.005 51.84 49.275 ;
     RECT  2.16 49.545 51.84 49.815 ;
     RECT  2.16 50.085 51.84 50.355 ;
     RECT  2.16 50.625 51.84 50.895 ;
     RECT  2.16 51.165 51.84 51.435 ;
     RECT  2.16 51.705 51.84 51.975 ;
     RECT  2.16 52.245 51.84 52.515 ;
     RECT  2.16 52.785 51.84 53.055 ;
     RECT  2.16 53.325 51.84 53.595 ;
     RECT  2.16 53.865 51.84 54.135 ;
     RECT  2.16 54.405 51.84 54.675 ;
     RECT  2.16 54.945 51.84 55.215 ;
     RECT  2.16 55.485 51.84 55.755 ;
     RECT  2.16 56.025 51.84 56.295 ;
     RECT  2.16 56.565 51.84 56.835 ;
     RECT  2.16 57.105 51.84 57.375 ;
     RECT  2.16 57.645 51.84 57.915 ;
     RECT  2.16 58.185 51.84 58.455 ;
     RECT  2.16 58.725 51.84 58.995 ;
     RECT  2.16 59.265 51.84 59.535 ;
     RECT  2.16 59.805 51.84 60.075 ;
     RECT  2.16 60.345 51.84 60.615 ;
     RECT  2.16 60.885 51.84 61.155 ;
     RECT  2.16 61.425 51.84 61.695 ;
     RECT  2.16 61.965 51.84 62.235 ;
     RECT  2.16 62.505 51.84 62.775 ;
     RECT  2.16 63.045 51.84 63.315 ;
     RECT  2.16 63.585 51.84 63.855 ;
     RECT  2.16 64.125 51.84 64.395 ;
     RECT  2.16 64.665 51.84 64.935 ;
     RECT  2.16 65.205 51.84 65.475 ;
     RECT  2.16 65.745 51.84 66.015 ;
     RECT  2.16 66.285 51.84 66.555 ;
     RECT  2.16 66.825 51.84 67.095 ;
     RECT  2.16 67.365 51.84 67.635 ;
     RECT  2.16 67.905 51.84 68.175 ;
     RECT  2.16 68.445 51.84 68.715 ;
     RECT  2.16 68.985 51.84 69.255 ;
     RECT  2.16 69.525 51.84 69.795 ;
     RECT  2.16 70.065 51.84 70.335 ;
     RECT  2.16 70.605 51.84 70.875 ;
     RECT  2.16 71.145 51.84 71.415 ;
     RECT  2.16 71.685 51.84 71.955 ;
     RECT  2.16 72.225 51.84 72.495 ;
     RECT  2.16 72.765 51.84 73.035 ;
     RECT  2.16 73.305 51.84 73.575 ;
     RECT  2.16 73.845 51.84 74.115 ;
     RECT  2.16 74.385 51.84 74.655 ;
     RECT  2.16 74.925 51.84 75.195 ;
     RECT  2.16 75.465 51.84 75.735 ;
     RECT  2.16 76.005 51.84 76.275 ;
     RECT  2.16 76.545 51.84 76.815 ;
     RECT  2.16 77.085 51.84 77.355 ;
     RECT  2.16 77.625 51.84 77.895 ;
     RECT  2.16 78.165 51.84 78.435 ;
     RECT  2.16 78.705 51.84 78.975 ;
     RECT  2.16 79.245 51.84 79.515 ;
     RECT  2.16 79.785 51.84 80.055 ;
     RECT  2.16 80.325 51.84 80.595 ;
     RECT  2.16 80.865 51.84 81.135 ;
     RECT  2.16 81.405 51.84 81.675 ;
     RECT  2.16 81.945 51.84 82.215 ;
     RECT  2.16 82.485 51.84 82.755 ;
     RECT  2.16 83.025 51.84 83.295 ;
     RECT  2.16 83.565 51.84 83.835 ;
     RECT  2.16 84.105 51.84 84.375 ;
     RECT  2.16 84.645 51.84 84.915 ;
     RECT  2.16 85.185 51.84 85.455 ;
     RECT  2.16 85.725 51.84 85.995 ;
     RECT  2.16 86.265 51.84 86.535 ;
     RECT  2.16 86.805 51.84 87.075 ;
     RECT  2.16 87.345 51.84 87.615 ;
     RECT  2.16 87.885 51.84 88.155 ;
     RECT  2.16 88.425 51.84 88.695 ;
     RECT  2.16 88.965 51.84 89.235 ;
     RECT  2.16 89.505 51.84 89.775 ;
     RECT  2.16 90.045 51.84 90.315 ;
     RECT  2.16 90.585 51.84 90.855 ;
     RECT  2.16 91.125 51.84 91.395 ;
     RECT  2.16 91.665 51.84 91.935 ;
     RECT  2.16 92.205 51.84 92.475 ;
     RECT  2.16 92.745 51.84 93.015 ;
     RECT  2.16 93.285 51.84 93.555 ;
     RECT  2.16 93.825 51.84 94.095 ;
     RECT  2.16 94.365 51.84 94.635 ;
     RECT  2.16 94.905 51.84 95.175 ;
     RECT  2.16 95.445 51.84 95.715 ;
     RECT  2.16 95.985 51.84 96.255 ;
     RECT  2.16 96.525 51.84 96.795 ;
     RECT  2.16 97.065 51.84 97.335 ;
     RECT  2.16 97.605 51.84 97.875 ;
     RECT  2.16 98.145 51.84 98.415 ;
     RECT  2.16 98.685 51.84 98.955 ;
     RECT  2.16 99.225 51.84 99.495 ;
     RECT  2.16 99.765 51.84 100.035 ;
     RECT  2.16 100.305 51.84 100.575 ;
     RECT  2.16 100.845 51.84 101.115 ;
     RECT  2.16 101.385 51.84 101.655 ;
     RECT  2.16 101.925 51.84 102.195 ;
     RECT  2.16 102.465 51.84 102.735 ;
     RECT  2.16 103.005 51.84 103.275 ;
     RECT  2.16 103.545 51.84 103.815 ;
     RECT  2.16 104.085 51.84 104.355 ;
     RECT  2.16 104.625 51.84 104.895 ;
     RECT  2.16 105.165 51.84 105.435 ;
     RECT  2.16 105.705 51.84 105.975 ;
     RECT  2.16 106.245 51.84 106.515 ;
     RECT  2.16 106.785 51.84 107.055 ;
     RECT  2.16 107.325 51.84 107.595 ;
     RECT  2.16 107.865 51.84 108.135 ;
     RECT  2.16 108.405 51.84 108.675 ;
     RECT  2.16 108.945 51.84 109.215 ;
     RECT  2.16 109.485 51.84 109.755 ;
     RECT  2.16 110.025 51.84 110.295 ;
     RECT  2.16 110.565 51.84 110.835 ;
     RECT  2.16 111.105 51.84 111.375 ;
     RECT  2.16 111.645 51.84 111.915 ;
     RECT  2.16 112.185 51.84 112.455 ;
     RECT  2.16 112.725 51.84 112.995 ;
     RECT  2.16 113.265 51.84 113.535 ;
     RECT  2.16 113.805 51.84 114.075 ;
     RECT  2.16 114.345 51.84 114.615 ;
     RECT  2.16 114.885 51.84 115.155 ;
     RECT  2.16 115.425 51.84 115.695 ;
     RECT  2.16 115.965 51.84 116.235 ;
     RECT  2.16 116.505 51.84 116.775 ;
     RECT  2.16 117.045 51.84 117.315 ;
     RECT  2.16 117.585 51.84 117.855 ;
     RECT  2.16 118.125 51.84 118.395 ;
     RECT  2.16 118.665 51.84 118.935 ;
     RECT  2.16 119.205 51.84 119.475 ;
     RECT  2.16 119.745 51.84 120.015 ;
     RECT  2.16 120.285 51.84 120.555 ;
     RECT  2.16 120.825 51.84 121.095 ;
     RECT  2.16 121.365 51.84 121.635 ;
     RECT  2.16 121.905 51.84 122.175 ;
     RECT  2.16 122.445 51.84 122.715 ;
     RECT  2.16 122.985 51.84 123.255 ;
     RECT  2.16 123.525 51.84 123.795 ;
     RECT  2.16 124.065 51.84 124.335 ;
     RECT  2.16 124.605 51.84 124.875 ;
     RECT  2.16 125.145 51.84 125.415 ;
     RECT  2.16 125.685 51.84 125.955 ;
     RECT  2.16 126.225 51.84 126.495 ;
     RECT  2.16 126.765 51.84 127.035 ;
     RECT  2.16 127.305 51.84 127.44 ;
    LAYER RVTP ;
     RECT  2.16 2.295 51.84 2.565 ;
     RECT  2.16 2.835 51.84 3.105 ;
     RECT  2.16 3.375 51.84 3.645 ;
     RECT  2.16 3.915 51.84 4.185 ;
     RECT  2.16 4.455 51.84 4.725 ;
     RECT  2.16 4.995 51.84 5.265 ;
     RECT  2.16 5.535 51.84 5.805 ;
     RECT  2.16 6.075 51.84 6.345 ;
     RECT  2.16 6.615 51.84 6.885 ;
     RECT  2.16 7.155 51.84 7.425 ;
     RECT  2.16 7.695 51.84 7.965 ;
     RECT  2.16 8.235 51.84 8.505 ;
     RECT  2.16 8.775 51.84 9.045 ;
     RECT  2.16 9.315 51.84 9.585 ;
     RECT  2.16 9.855 51.84 10.125 ;
     RECT  2.16 10.395 51.84 10.665 ;
     RECT  2.16 10.935 51.84 11.205 ;
     RECT  2.16 11.475 51.84 11.745 ;
     RECT  2.16 12.015 51.84 12.285 ;
     RECT  2.16 12.555 51.84 12.825 ;
     RECT  2.16 13.095 51.84 13.365 ;
     RECT  2.16 13.635 51.84 13.905 ;
     RECT  2.16 14.175 51.84 14.445 ;
     RECT  2.16 14.715 51.84 14.985 ;
     RECT  2.16 15.255 51.84 15.525 ;
     RECT  2.16 15.795 51.84 16.065 ;
     RECT  2.16 16.335 51.84 16.605 ;
     RECT  2.16 16.875 51.84 17.145 ;
     RECT  2.16 17.415 51.84 17.685 ;
     RECT  2.16 17.955 51.84 18.225 ;
     RECT  2.16 18.495 51.84 18.765 ;
     RECT  2.16 19.035 51.84 19.305 ;
     RECT  2.16 19.575 51.84 19.845 ;
     RECT  2.16 20.115 51.84 20.385 ;
     RECT  2.16 20.655 51.84 20.925 ;
     RECT  2.16 21.195 51.84 21.465 ;
     RECT  2.16 21.735 51.84 22.005 ;
     RECT  2.16 22.275 51.84 22.545 ;
     RECT  2.16 22.815 51.84 23.085 ;
     RECT  2.16 23.355 51.84 23.625 ;
     RECT  2.16 23.895 51.84 24.165 ;
     RECT  2.16 24.435 51.84 24.705 ;
     RECT  2.16 24.975 51.84 25.245 ;
     RECT  2.16 25.515 51.84 25.785 ;
     RECT  2.16 26.055 51.84 26.325 ;
     RECT  2.16 26.595 51.84 26.865 ;
     RECT  2.16 27.135 51.84 27.405 ;
     RECT  2.16 27.675 51.84 27.945 ;
     RECT  2.16 28.215 51.84 28.485 ;
     RECT  2.16 28.755 51.84 29.025 ;
     RECT  2.16 29.295 51.84 29.565 ;
     RECT  2.16 29.835 51.84 30.105 ;
     RECT  2.16 30.375 51.84 30.645 ;
     RECT  2.16 30.915 51.84 31.185 ;
     RECT  2.16 31.455 51.84 31.725 ;
     RECT  2.16 31.995 51.84 32.265 ;
     RECT  2.16 32.535 51.84 32.805 ;
     RECT  2.16 33.075 51.84 33.345 ;
     RECT  2.16 33.615 51.84 33.885 ;
     RECT  2.16 34.155 51.84 34.425 ;
     RECT  2.16 34.695 51.84 34.965 ;
     RECT  2.16 35.235 51.84 35.505 ;
     RECT  2.16 35.775 51.84 36.045 ;
     RECT  2.16 36.315 51.84 36.585 ;
     RECT  2.16 36.855 51.84 37.125 ;
     RECT  2.16 37.395 51.84 37.665 ;
     RECT  2.16 37.935 51.84 38.205 ;
     RECT  2.16 38.475 51.84 38.745 ;
     RECT  2.16 39.015 51.84 39.285 ;
     RECT  2.16 39.555 51.84 39.825 ;
     RECT  2.16 40.095 51.84 40.365 ;
     RECT  2.16 40.635 51.84 40.905 ;
     RECT  2.16 41.175 51.84 41.445 ;
     RECT  2.16 41.715 51.84 41.985 ;
     RECT  2.16 42.255 51.84 42.525 ;
     RECT  2.16 42.795 51.84 43.065 ;
     RECT  2.16 43.335 51.84 43.605 ;
     RECT  2.16 43.875 51.84 44.145 ;
     RECT  2.16 44.415 51.84 44.685 ;
     RECT  2.16 44.955 51.84 45.225 ;
     RECT  2.16 45.495 51.84 45.765 ;
     RECT  2.16 46.035 51.84 46.305 ;
     RECT  2.16 46.575 51.84 46.845 ;
     RECT  2.16 47.115 51.84 47.385 ;
     RECT  2.16 47.655 51.84 47.925 ;
     RECT  2.16 48.195 51.84 48.465 ;
     RECT  2.16 48.735 51.84 49.005 ;
     RECT  2.16 49.275 51.84 49.545 ;
     RECT  2.16 49.815 51.84 50.085 ;
     RECT  2.16 50.355 51.84 50.625 ;
     RECT  2.16 50.895 51.84 51.165 ;
     RECT  2.16 51.435 51.84 51.705 ;
     RECT  2.16 51.975 51.84 52.245 ;
     RECT  2.16 52.515 51.84 52.785 ;
     RECT  2.16 53.055 51.84 53.325 ;
     RECT  2.16 53.595 51.84 53.865 ;
     RECT  2.16 54.135 51.84 54.405 ;
     RECT  2.16 54.675 51.84 54.945 ;
     RECT  2.16 55.215 51.84 55.485 ;
     RECT  2.16 55.755 51.84 56.025 ;
     RECT  2.16 56.295 51.84 56.565 ;
     RECT  2.16 56.835 51.84 57.105 ;
     RECT  2.16 57.375 51.84 57.645 ;
     RECT  2.16 57.915 51.84 58.185 ;
     RECT  2.16 58.455 51.84 58.725 ;
     RECT  2.16 58.995 51.84 59.265 ;
     RECT  2.16 59.535 51.84 59.805 ;
     RECT  2.16 60.075 51.84 60.345 ;
     RECT  2.16 60.615 51.84 60.885 ;
     RECT  2.16 61.155 51.84 61.425 ;
     RECT  2.16 61.695 51.84 61.965 ;
     RECT  2.16 62.235 51.84 62.505 ;
     RECT  2.16 62.775 51.84 63.045 ;
     RECT  2.16 63.315 51.84 63.585 ;
     RECT  2.16 63.855 51.84 64.125 ;
     RECT  2.16 64.395 51.84 64.665 ;
     RECT  2.16 64.935 51.84 65.205 ;
     RECT  2.16 65.475 51.84 65.745 ;
     RECT  2.16 66.015 51.84 66.285 ;
     RECT  2.16 66.555 51.84 66.825 ;
     RECT  2.16 67.095 51.84 67.365 ;
     RECT  2.16 67.635 51.84 67.905 ;
     RECT  2.16 68.175 51.84 68.445 ;
     RECT  2.16 68.715 51.84 68.985 ;
     RECT  2.16 69.255 51.84 69.525 ;
     RECT  2.16 69.795 51.84 70.065 ;
     RECT  2.16 70.335 51.84 70.605 ;
     RECT  2.16 70.875 51.84 71.145 ;
     RECT  2.16 71.415 51.84 71.685 ;
     RECT  2.16 71.955 51.84 72.225 ;
     RECT  2.16 72.495 51.84 72.765 ;
     RECT  2.16 73.035 51.84 73.305 ;
     RECT  2.16 73.575 51.84 73.845 ;
     RECT  2.16 74.115 51.84 74.385 ;
     RECT  2.16 74.655 51.84 74.925 ;
     RECT  2.16 75.195 51.84 75.465 ;
     RECT  2.16 75.735 51.84 76.005 ;
     RECT  2.16 76.275 51.84 76.545 ;
     RECT  2.16 76.815 51.84 77.085 ;
     RECT  2.16 77.355 51.84 77.625 ;
     RECT  2.16 77.895 51.84 78.165 ;
     RECT  2.16 78.435 51.84 78.705 ;
     RECT  2.16 78.975 51.84 79.245 ;
     RECT  2.16 79.515 51.84 79.785 ;
     RECT  2.16 80.055 51.84 80.325 ;
     RECT  2.16 80.595 51.84 80.865 ;
     RECT  2.16 81.135 51.84 81.405 ;
     RECT  2.16 81.675 51.84 81.945 ;
     RECT  2.16 82.215 51.84 82.485 ;
     RECT  2.16 82.755 51.84 83.025 ;
     RECT  2.16 83.295 51.84 83.565 ;
     RECT  2.16 83.835 51.84 84.105 ;
     RECT  2.16 84.375 51.84 84.645 ;
     RECT  2.16 84.915 51.84 85.185 ;
     RECT  2.16 85.455 51.84 85.725 ;
     RECT  2.16 85.995 51.84 86.265 ;
     RECT  2.16 86.535 51.84 86.805 ;
     RECT  2.16 87.075 51.84 87.345 ;
     RECT  2.16 87.615 51.84 87.885 ;
     RECT  2.16 88.155 51.84 88.425 ;
     RECT  2.16 88.695 51.84 88.965 ;
     RECT  2.16 89.235 51.84 89.505 ;
     RECT  2.16 89.775 51.84 90.045 ;
     RECT  2.16 90.315 51.84 90.585 ;
     RECT  2.16 90.855 51.84 91.125 ;
     RECT  2.16 91.395 51.84 91.665 ;
     RECT  2.16 91.935 51.84 92.205 ;
     RECT  2.16 92.475 51.84 92.745 ;
     RECT  2.16 93.015 51.84 93.285 ;
     RECT  2.16 93.555 51.84 93.825 ;
     RECT  2.16 94.095 51.84 94.365 ;
     RECT  2.16 94.635 51.84 94.905 ;
     RECT  2.16 95.175 51.84 95.445 ;
     RECT  2.16 95.715 51.84 95.985 ;
     RECT  2.16 96.255 51.84 96.525 ;
     RECT  2.16 96.795 51.84 97.065 ;
     RECT  2.16 97.335 51.84 97.605 ;
     RECT  2.16 97.875 51.84 98.145 ;
     RECT  2.16 98.415 51.84 98.685 ;
     RECT  2.16 98.955 51.84 99.225 ;
     RECT  2.16 99.495 51.84 99.765 ;
     RECT  2.16 100.035 51.84 100.305 ;
     RECT  2.16 100.575 51.84 100.845 ;
     RECT  2.16 101.115 51.84 101.385 ;
     RECT  2.16 101.655 51.84 101.925 ;
     RECT  2.16 102.195 51.84 102.465 ;
     RECT  2.16 102.735 51.84 103.005 ;
     RECT  2.16 103.275 51.84 103.545 ;
     RECT  2.16 103.815 51.84 104.085 ;
     RECT  2.16 104.355 51.84 104.625 ;
     RECT  2.16 104.895 51.84 105.165 ;
     RECT  2.16 105.435 51.84 105.705 ;
     RECT  2.16 105.975 51.84 106.245 ;
     RECT  2.16 106.515 51.84 106.785 ;
     RECT  2.16 107.055 51.84 107.325 ;
     RECT  2.16 107.595 51.84 107.865 ;
     RECT  2.16 108.135 51.84 108.405 ;
     RECT  2.16 108.675 51.84 108.945 ;
     RECT  2.16 109.215 51.84 109.485 ;
     RECT  2.16 109.755 51.84 110.025 ;
     RECT  2.16 110.295 51.84 110.565 ;
     RECT  2.16 110.835 51.84 111.105 ;
     RECT  2.16 111.375 51.84 111.645 ;
     RECT  2.16 111.915 51.84 112.185 ;
     RECT  2.16 112.455 51.84 112.725 ;
     RECT  2.16 112.995 51.84 113.265 ;
     RECT  2.16 113.535 51.84 113.805 ;
     RECT  2.16 114.075 51.84 114.345 ;
     RECT  2.16 114.615 51.84 114.885 ;
     RECT  2.16 115.155 51.84 115.425 ;
     RECT  2.16 115.695 51.84 115.965 ;
     RECT  2.16 116.235 51.84 116.505 ;
     RECT  2.16 116.775 51.84 117.045 ;
     RECT  2.16 117.315 51.84 117.585 ;
     RECT  2.16 117.855 51.84 118.125 ;
     RECT  2.16 118.395 51.84 118.665 ;
     RECT  2.16 118.935 51.84 119.205 ;
     RECT  2.16 119.475 51.84 119.745 ;
     RECT  2.16 120.015 51.84 120.285 ;
     RECT  2.16 120.555 51.84 120.825 ;
     RECT  2.16 121.095 51.84 121.365 ;
     RECT  2.16 121.635 51.84 121.905 ;
     RECT  2.16 122.175 51.84 122.445 ;
     RECT  2.16 122.715 51.84 122.985 ;
     RECT  2.16 123.255 51.84 123.525 ;
     RECT  2.16 123.795 51.84 124.065 ;
     RECT  2.16 124.335 51.84 124.605 ;
     RECT  2.16 124.875 51.84 125.145 ;
     RECT  2.16 125.415 51.84 125.685 ;
     RECT  2.16 125.955 51.84 126.225 ;
     RECT  2.16 126.495 51.84 126.765 ;
     RECT  2.16 127.035 51.84 127.305 ;
    LAYER M1 ;
     RECT  2.16 2.151 51.84 127.449 ;
    LAYER M2 ;
     RECT  0.103 54.684 0.203 54.702 ;
     RECT  0.103 50.436 0.347 50.58 ;
     RECT  0.139 56.376 0.347 56.394 ;
     RECT  0.103 58.194 0.347 58.212 ;
     RECT  0.175 65.52 0.347 65.538 ;
     RECT  0.103 82.296 0.347 82.314 ;
     RECT  0.347 50.562 0.383 50.58 ;
     RECT  0.103 48.978 0.535 48.996 ;
     RECT  0.499 59.004 0.535 59.022 ;
     RECT  0.535 48.816 2.16 48.996 ;
     RECT  0.535 52.866 2.16 52.884 ;
     RECT  0.535 59.004 2.16 59.094 ;
     RECT  2.16 2.151 14.827 127.449 ;
     RECT  14.827 2.106 18.275 127.449 ;
     RECT  18.275 2.151 34.519 127.449 ;
     RECT  34.519 2.106 35.203 127.449 ;
     RECT  35.203 2.034 36.455 127.449 ;
     RECT  36.455 2.106 36.887 127.449 ;
     RECT  36.887 2.151 51.84 127.449 ;
     RECT  51.84 45.738 51.899 66.348 ;
     RECT  51.899 45.738 51.971 56.124 ;
     RECT  51.899 56.88 52.403 66.348 ;
     RECT  51.84 67.266 52.403 83.592 ;
     RECT  52.403 57.384 52.439 66.348 ;
     RECT  51.971 45.738 52.475 49.266 ;
     RECT  52.439 57.546 52.475 66.348 ;
     RECT  52.403 77.364 52.475 83.592 ;
     RECT  52.475 45.738 52.727 48.726 ;
     RECT  51.84 84.456 52.727 86.994 ;
     RECT  52.727 46.386 52.763 48.726 ;
     RECT  52.727 86.436 52.763 86.994 ;
     RECT  52.763 46.386 52.835 46.404 ;
     RECT  52.727 84.456 52.835 85.644 ;
     RECT  51.971 50.058 52.979 56.124 ;
     RECT  52.403 67.266 52.979 76.572 ;
     RECT  52.475 77.562 52.979 83.592 ;
     RECT  52.979 50.058 53.015 55.404 ;
     RECT  52.475 57.546 53.015 64.224 ;
     RECT  52.475 65.016 53.015 66.348 ;
     RECT  52.979 77.562 53.015 81.162 ;
     RECT  53.015 50.058 53.051 52.236 ;
     RECT  53.015 57.888 53.051 59.562 ;
     RECT  52.979 67.266 53.051 70.398 ;
     RECT  52.979 71.154 53.051 76.032 ;
     RECT  53.015 81.108 53.051 81.126 ;
     RECT  52.763 47.286 53.087 48.726 ;
     RECT  53.051 52.218 53.087 52.236 ;
     RECT  53.051 58.122 53.087 59.562 ;
     RECT  53.051 67.266 53.087 70.02 ;
     RECT  53.051 50.868 53.123 51.264 ;
     RECT  53.087 47.286 53.159 48.654 ;
     RECT  53.087 67.266 53.635 68.202 ;
     RECT  52.979 82.116 53.699 83.592 ;
     RECT  53.699 82.116 53.707 83.484 ;
     RECT  53.015 66.024 53.743 66.042 ;
     RECT  53.051 71.154 53.779 73.638 ;
     RECT  53.779 71.118 53.807 73.638 ;
     RECT  52.835 84.888 53.807 85.644 ;
     RECT  53.015 60.318 53.815 61.614 ;
     RECT  53.015 62.55 53.815 63.072 ;
     RECT  53.635 67.068 53.815 68.202 ;
     RECT  53.159 47.286 53.843 48.456 ;
     RECT  53.015 53.766 53.843 54.972 ;
     RECT  53.807 71.118 53.843 73.602 ;
     RECT  53.015 77.562 53.843 80.316 ;
     RECT  53.707 81.954 53.843 83.484 ;
     RECT  53.743 66.024 53.851 66.312 ;
     RECT  53.815 67.068 53.851 68.364 ;
     RECT  53.843 48.438 53.879 48.456 ;
     RECT  53.843 54.216 53.879 54.972 ;
     RECT  53.087 58.968 53.879 59.562 ;
     RECT  53.815 60.318 53.879 63.072 ;
     RECT  53.851 66.024 53.879 68.364 ;
     RECT  53.843 71.118 53.879 73.404 ;
     RECT  53.051 74.394 53.879 76.032 ;
     RECT  53.843 77.562 53.879 77.58 ;
     RECT  53.843 78.336 53.879 79.884 ;
     RECT  53.843 81.954 53.879 82.404 ;
     RECT  53.807 85.536 53.879 85.644 ;
     RECT  53.843 47.286 53.915 47.304 ;
     RECT  53.123 51.246 53.915 51.264 ;
     RECT  53.879 54.216 53.915 54.234 ;
     RECT  53.815 56.151 53.915 56.394 ;
     RECT  53.087 58.122 53.915 58.14 ;
     RECT  53.879 58.968 53.915 59.526 ;
     RECT  53.879 61.326 53.915 61.956 ;
     RECT  53.879 63.054 53.915 63.072 ;
     RECT  53.015 63.828 53.915 64.224 ;
     RECT  53.879 66.762 53.915 67.284 ;
     RECT  53.879 68.184 53.915 68.364 ;
     RECT  53.087 69.336 53.915 70.02 ;
     RECT  53.879 71.154 53.915 73.404 ;
     RECT  53.879 74.898 53.915 76.032 ;
     RECT  53.879 78.336 53.915 78.354 ;
     RECT  53.879 79.488 53.915 79.884 ;
     RECT  53.879 81.954 53.915 82.134 ;
     RECT  53.843 83.268 53.915 83.286 ;
     RECT  53.879 85.626 53.915 85.644 ;
     RECT  53.915 63.828 53.987 63.846 ;
     RECT  53.915 66.762 53.987 66.78 ;
     RECT  53.915 81.954 53.987 81.972 ;
     RECT  52.763 86.436 53.987 86.454 ;
    LAYER M3 ;
     RECT  16.236 0.091 16.254 0.523 ;
     RECT  17.424 0.091 17.442 0.571 ;
     RECT  17.244 0.571 17.442 0.619 ;
     RECT  16.164 0.523 16.254 1.099 ;
     RECT  17.136 0.619 17.442 1.099 ;
     RECT  30.78 0.091 31.374 1.099 ;
     RECT  29.232 0.571 29.898 1.147 ;
     RECT  30.78 1.099 31.77 1.147 ;
     RECT  16.164 1.099 17.586 1.723 ;
     RECT  29.088 1.147 29.898 1.723 ;
     RECT  30.744 1.147 31.77 1.723 ;
     RECT  16.164 1.723 18.522 1.771 ;
     RECT  29.088 1.723 32.166 1.771 ;
     RECT  32.904 1.723 33.354 1.771 ;
     RECT  34.128 1.723 35.154 1.771 ;
     RECT  16.164 1.771 18.99 1.819 ;
     RECT  19.728 1.723 19.746 1.819 ;
     RECT  29.088 1.771 35.154 1.819 ;
     RECT  29.088 1.819 35.19 2.029 ;
     RECT  29.088 2.029 35.226 2.101 ;
     RECT  36.432 2.029 36.45 2.101 ;
     RECT  16.164 1.819 19.746 2.191 ;
     RECT  29.088 2.101 35.298 2.191 ;
     RECT  36.144 2.101 36.882 2.191 ;
     RECT  14.832 2.101 14.85 2.219 ;
     RECT  15.768 2.191 19.746 2.263 ;
     RECT  29.088 2.191 36.954 2.263 ;
     RECT  15.696 2.263 20.394 2.371 ;
     RECT  29.088 2.263 37.026 2.371 ;
     RECT  2.415 2.143 2.505 2.413 ;
     RECT  7.815 2.143 7.905 2.413 ;
     RECT  13.215 2.143 13.305 2.413 ;
     RECT  24.015 2.143 24.105 2.413 ;
     RECT  40.215 2.143 40.305 2.413 ;
     RECT  45.615 2.143 45.705 2.413 ;
     RECT  51.015 2.143 51.105 2.413 ;
     RECT  14.94 2.371 20.574 2.461 ;
     RECT  21.564 2.371 21.582 2.461 ;
     RECT  22.824 2.461 22.842 2.561 ;
     RECT  28.656 2.371 37.386 2.641 ;
     RECT  41.868 2.191 41.886 2.731 ;
     RECT  14.94 2.461 21.582 2.911 ;
     RECT  24.015 2.413 24.297 3.001 ;
     RECT  28.656 2.641 37.566 3.001 ;
     RECT  14.94 2.911 21.978 3.029 ;
     RECT  14.94 3.029 21.798 3.065 ;
     RECT  28.476 3.001 37.566 3.145 ;
     RECT  28.44 3.145 37.638 3.181 ;
     RECT  40.215 2.413 40.497 3.181 ;
     RECT  26.784 2.533 26.802 3.271 ;
     RECT  28.44 3.181 38.286 3.271 ;
     RECT  26.748 3.271 26.802 3.371 ;
     RECT  28.44 3.271 38.682 3.371 ;
     RECT  28.44 3.371 37.962 3.437 ;
     RECT  14.94 3.065 21.222 3.569 ;
     RECT  38.772 3.613 38.79 3.713 ;
     RECT  39.6 3.181 40.497 3.721 ;
     RECT  24.015 3.001 24.894 3.811 ;
     RECT  25.956 2.731 25.974 3.811 ;
     RECT  43.74 3.613 43.758 3.811 ;
     RECT  15.264 3.569 21.222 3.847 ;
     RECT  28.476 3.437 37.962 4.289 ;
     RECT  28.548 4.289 37.962 4.379 ;
     RECT  28.548 4.379 37.782 4.415 ;
     RECT  43.632 3.811 43.758 4.423 ;
     RECT  43.56 4.423 43.758 4.531 ;
     RECT  24.015 3.811 25.974 4.621 ;
     RECT  26.748 3.371 26.766 4.621 ;
     RECT  15.264 3.847 21.258 4.649 ;
     RECT  28.548 4.415 37.53 4.691 ;
     RECT  38.736 4.261 38.754 4.729 ;
     RECT  43.56 4.531 43.83 4.729 ;
     RECT  38.736 4.729 38.826 4.829 ;
     RECT  15.3 4.649 21.258 4.891 ;
     RECT  15.3 4.891 21.618 4.919 ;
     RECT  41.868 2.731 42.57 4.927 ;
     RECT  43.344 4.729 43.83 4.927 ;
     RECT  29.016 4.691 37.53 4.955 ;
     RECT  15.3 4.919 20.79 5.189 ;
     RECT  29.016 4.955 36.954 5.213 ;
     RECT  37.836 5.269 37.854 5.369 ;
     RECT  21.6 4.919 21.618 5.431 ;
     RECT  38.736 4.829 38.754 5.431 ;
     RECT  15.948 5.189 20.79 5.459 ;
     RECT  29.232 5.213 36.954 5.459 ;
     RECT  15.948 5.459 20.574 5.495 ;
     RECT  22.788 5.341 22.806 5.495 ;
     RECT  15.948 5.495 20.502 5.531 ;
     RECT  21.6 5.431 21.69 5.639 ;
     RECT  29.415 5.459 36.954 5.737 ;
     RECT  29.415 5.737 37.278 5.789 ;
     RECT  29.415 5.789 35.658 5.837 ;
     RECT  16.272 5.531 20.502 5.873 ;
     RECT  16.272 5.873 20.394 6.071 ;
     RECT  36.504 5.789 37.278 6.071 ;
     RECT  38.196 5.431 38.754 6.143 ;
     RECT  16.272 6.071 19.314 6.173 ;
     RECT  16.344 6.173 19.314 6.269 ;
     RECT  20.088 6.071 20.394 6.269 ;
     RECT  18.615 6.269 19.17 6.305 ;
     RECT  20.16 6.269 20.25 6.305 ;
     RECT  39.6 3.721 41.022 6.547 ;
     RECT  41.868 4.927 43.83 6.547 ;
     RECT  36.504 6.071 36.774 6.575 ;
     RECT  30.456 5.837 35.658 6.583 ;
     RECT  20.16 6.305 20.178 10.741 ;
     RECT  20.088 10.741 20.178 10.769 ;
     RECT  38.34 6.143 38.754 10.769 ;
     RECT  38.34 10.769 38.682 15.763 ;
     RECT  39.6 6.547 43.83 15.763 ;
     RECT  38.34 15.763 43.83 16.951 ;
     RECT  30.456 6.583 35.802 17.339 ;
     RECT  37.62 16.951 43.83 17.347 ;
     RECT  30.456 17.339 31.95 17.483 ;
     RECT  37.62 17.347 43.938 17.581 ;
     RECT  33.012 17.339 35.802 17.609 ;
     RECT  30.456 17.483 30.978 18.149 ;
     RECT  37.62 17.581 44.442 18.391 ;
     RECT  45.615 2.413 45.897 18.391 ;
     RECT  31.932 17.483 31.95 18.419 ;
     RECT  34.815 17.609 35.802 18.571 ;
     RECT  30.528 18.149 30.978 18.599 ;
     RECT  33.012 17.609 33.714 18.661 ;
     RECT  34.488 18.571 35.802 18.661 ;
     RECT  33.012 18.661 35.802 18.697 ;
     RECT  36.612 6.575 36.774 18.697 ;
     RECT  30.528 18.599 30.798 18.797 ;
     RECT  33.012 18.697 36.774 18.797 ;
     RECT  34.524 18.797 36.774 18.869 ;
     RECT  33.012 18.797 33.714 18.959 ;
     RECT  34.524 18.869 35.802 18.995 ;
     RECT  30.528 18.797 30.546 19.139 ;
     RECT  32.04 19.111 32.058 19.229 ;
     RECT  33.012 18.959 33.642 19.769 ;
     RECT  33.12 19.769 33.642 19.841 ;
     RECT  33.192 19.841 33.642 20.011 ;
     RECT  15.084 6.241 15.102 22.027 ;
     RECT  13.215 2.413 13.497 22.081 ;
     RECT  13.104 22.081 13.497 22.171 ;
     RECT  13.104 22.171 13.662 22.205 ;
     RECT  14.94 22.027 15.102 22.205 ;
     RECT  13.215 22.205 13.662 22.208 ;
     RECT  36.612 18.869 36.774 42.523 ;
     RECT  37.62 18.391 45.897 42.523 ;
     RECT  36.612 42.523 45.897 42.755 ;
     RECT  51.015 2.413 51.297 45.805 ;
     RECT  51.015 45.805 51.75 46.345 ;
     RECT  52.704 45.733 52.722 46.381 ;
     RECT  37.62 42.755 45.897 46.769 ;
     RECT  50.58 46.345 51.75 46.921 ;
     RECT  52.704 46.381 52.83 46.921 ;
     RECT  50.58 46.921 52.83 47.155 ;
     RECT  48.996 47.281 49.014 47.425 ;
     RECT  49.896 47.155 52.83 47.623 ;
     RECT  53.892 47.281 53.91 47.731 ;
     RECT  48.42 47.425 49.014 47.821 ;
     RECT  49.896 47.623 53.046 47.821 ;
     RECT  48.42 47.821 53.046 47.857 ;
     RECT  37.692 46.769 45.897 47.899 ;
     RECT  37.692 47.899 46.314 47.929 ;
     RECT  37.692 47.929 46.818 48.001 ;
     RECT  37.692 48.001 47.214 48.091 ;
     RECT  48.384 47.857 53.046 48.163 ;
     RECT  37.692 48.091 47.322 48.271 ;
     RECT  48.312 48.163 53.046 48.271 ;
     RECT  53.82 47.731 53.91 48.271 ;
     RECT  37.692 48.271 47.466 48.433 ;
     RECT  48.312 48.271 53.91 48.433 ;
     RECT  37.692 48.433 53.91 48.461 ;
     RECT  24.015 4.621 26.766 48.541 ;
     RECT  2.415 2.413 2.697 48.811 ;
     RECT  22.536 48.397 22.554 48.811 ;
     RECT  37.692 48.461 53.874 48.845 ;
     RECT  4.968 48.271 4.986 48.901 ;
     RECT  0.54 48.811 0.558 48.973 ;
     RECT  9.54 48.163 9.558 48.973 ;
     RECT  0.108 48.973 0.558 49.037 ;
     RECT  11.088 48.703 11.106 49.045 ;
     RECT  2.415 48.811 3.798 49.081 ;
     RECT  4.68 48.901 4.986 49.081 ;
     RECT  0.108 49.037 0.126 49.133 ;
     RECT  2.415 49.081 4.986 49.171 ;
     RECT  6.192 48.937 6.21 49.171 ;
     RECT  7.815 2.413 8.097 49.171 ;
     RECT  2.415 49.171 6.21 49.243 ;
     RECT  7.416 49.171 8.097 49.243 ;
     RECT  16.344 6.269 17.874 49.243 ;
     RECT  18.615 6.305 18.99 49.243 ;
     RECT  2.415 49.243 8.097 49.291 ;
     RECT  21.168 6.421 21.186 49.291 ;
     RECT  21.924 48.811 22.554 49.291 ;
     RECT  2.304 49.291 8.097 49.351 ;
     RECT  8.964 48.973 9.558 49.351 ;
     RECT  2.304 49.351 9.558 49.675 ;
     RECT  37.692 48.845 53.838 49.709 ;
     RECT  2.268 49.675 9.558 49.783 ;
     RECT  2.268 49.783 9.594 50.153 ;
     RECT  2.268 50.153 3.438 50.155 ;
     RECT  2.232 50.155 3.438 50.189 ;
     RECT  53.82 49.709 53.838 50.333 ;
     RECT  0.324 50.251 0.342 50.347 ;
     RECT  2.232 50.189 3.294 50.387 ;
     RECT  0.108 50.347 0.342 50.557 ;
     RECT  0.108 50.557 0.378 50.585 ;
     RECT  20.088 10.769 20.106 50.665 ;
     RECT  21.168 49.291 22.554 50.665 ;
     RECT  0.18 50.585 0.378 50.669 ;
     RECT  16.344 49.243 18.99 50.791 ;
     RECT  4.212 50.153 9.594 50.827 ;
     RECT  37.692 49.709 53.082 50.863 ;
     RECT  29.415 5.837 29.697 50.875 ;
     RECT  30.528 50.629 30.546 50.875 ;
     RECT  4.212 50.827 9.63 50.971 ;
     RECT  32.292 48.433 32.31 50.971 ;
     RECT  33.192 20.011 34.074 50.971 ;
     RECT  16.344 50.791 19.134 51.097 ;
     RECT  37.692 50.863 53.118 51.149 ;
     RECT  2.304 50.387 3.294 51.205 ;
     RECT  4.032 50.971 9.63 51.205 ;
     RECT  16.308 51.097 19.134 51.205 ;
     RECT  37.692 51.149 53.082 51.245 ;
     RECT  37.692 51.245 51.966 51.331 ;
     RECT  52.992 51.245 53.082 51.341 ;
     RECT  0.324 50.669 0.342 51.437 ;
     RECT  32.292 50.971 34.074 51.439 ;
     RECT  34.815 18.995 35.802 51.439 ;
     RECT  37.656 51.331 51.966 51.475 ;
     RECT  37.62 51.475 51.966 51.533 ;
     RECT  15.084 22.205 15.102 51.601 ;
     RECT  37.656 51.533 51.894 51.629 ;
     RECT  14.832 51.601 15.102 51.737 ;
     RECT  14.94 51.737 15.102 51.781 ;
     RECT  15.948 51.205 19.134 51.781 ;
     RECT  53.892 51.241 53.91 51.821 ;
     RECT  2.304 51.205 9.63 51.883 ;
     RECT  14.94 51.781 19.134 51.899 ;
     RECT  53.028 51.341 53.082 52.075 ;
     RECT  2.268 51.883 9.63 52.141 ;
     RECT  52.992 52.075 53.082 52.171 ;
     RECT  14.94 51.899 15.102 52.241 ;
     RECT  23.868 48.541 26.766 52.249 ;
     RECT  20.088 50.665 22.554 52.267 ;
     RECT  52.956 52.171 53.082 52.267 ;
     RECT  15.948 51.899 19.134 52.321 ;
     RECT  20.088 52.267 22.914 52.321 ;
     RECT  36.612 42.755 36.774 52.321 ;
     RECT  37.656 51.629 51.714 52.321 ;
     RECT  2.268 52.141 9.666 52.363 ;
     RECT  29.415 50.875 30.546 52.411 ;
     RECT  36.612 52.321 51.714 52.411 ;
     RECT  2.268 52.363 9.702 52.438 ;
     RECT  15.948 52.321 22.914 52.445 ;
     RECT  36.612 52.411 51.894 52.459 ;
     RECT  52.92 52.267 53.082 52.459 ;
     RECT  36.612 52.459 53.082 52.589 ;
     RECT  2.268 52.438 9.738 52.619 ;
     RECT  14.94 52.241 15.03 52.681 ;
     RECT  13.215 22.208 13.497 52.843 ;
     RECT  14.904 52.681 15.03 52.861 ;
     RECT  13.104 52.843 13.497 52.889 ;
     RECT  14.832 52.861 15.03 52.889 ;
     RECT  28.152 52.141 28.17 52.979 ;
     RECT  36.612 52.589 53.01 52.979 ;
     RECT  32.292 51.439 35.802 52.981 ;
     RECT  36.612 52.979 46.386 52.981 ;
     RECT  28.98 52.411 30.546 53.023 ;
     RECT  31.284 51.745 31.302 53.023 ;
     RECT  0.54 52.861 0.558 53.069 ;
     RECT  2.268 52.619 9.666 53.087 ;
     RECT  15.948 52.445 22.842 53.249 ;
     RECT  53.892 52.843 53.91 53.371 ;
     RECT  47.304 52.979 53.01 53.429 ;
     RECT  16.128 53.249 22.842 53.519 ;
     RECT  14.832 52.889 14.85 53.635 ;
     RECT  32.292 52.981 46.386 53.761 ;
     RECT  47.304 53.429 51.894 53.761 ;
     RECT  53.82 53.371 53.91 53.837 ;
     RECT  14.832 53.635 14.886 53.941 ;
     RECT  52.812 53.429 53.01 54.031 ;
     RECT  14.832 53.941 14.922 54.095 ;
     RECT  52.812 54.031 53.046 54.125 ;
     RECT  28.98 53.023 31.302 54.131 ;
     RECT  32.292 53.761 51.894 54.175 ;
     RECT  52.812 54.125 53.01 54.175 ;
     RECT  32.292 54.175 53.01 54.221 ;
     RECT  53.856 53.837 53.91 54.239 ;
     RECT  14.832 54.095 14.886 54.329 ;
     RECT  23.868 52.249 27.342 54.379 ;
     RECT  14.868 54.329 14.886 54.509 ;
     RECT  2.304 53.087 9.666 54.571 ;
     RECT  23.652 54.379 27.342 54.607 ;
     RECT  0.144 54.475 0.162 54.679 ;
     RECT  23.652 54.607 27.378 54.715 ;
     RECT  0.108 54.679 0.198 54.749 ;
     RECT  0.108 54.749 0.126 54.797 ;
     RECT  23.652 54.715 27.45 54.869 ;
     RECT  32.292 54.221 51.894 54.893 ;
     RECT  53.856 54.239 53.874 54.977 ;
     RECT  16.128 53.519 22.554 54.985 ;
     RECT  23.652 54.869 27.378 54.985 ;
     RECT  52.884 54.221 53.01 55.051 ;
     RECT  23.508 54.985 27.378 55.111 ;
     RECT  15.732 54.985 22.554 55.147 ;
     RECT  28.98 54.131 30.546 55.255 ;
     RECT  2.268 54.571 9.666 55.445 ;
     RECT  15.66 55.147 22.554 55.525 ;
     RECT  23.364 55.111 27.378 55.525 ;
     RECT  0.216 55.483 0.234 55.627 ;
     RECT  13.215 52.889 13.497 55.687 ;
     RECT  15.66 55.525 27.378 55.687 ;
     RECT  28.152 55.255 30.546 55.687 ;
     RECT  32.292 54.893 51.498 55.795 ;
     RECT  32.292 55.795 51.534 55.819 ;
     RECT  53.82 55.339 53.838 55.915 ;
     RECT  10.512 49.045 11.106 55.921 ;
     RECT  15.66 55.687 30.546 56.029 ;
     RECT  31.284 54.131 31.302 56.029 ;
     RECT  2.304 55.445 9.666 56.057 ;
     RECT  53.748 55.915 53.838 56.093 ;
     RECT  15.66 56.029 31.302 56.101 ;
     RECT  53.82 56.093 53.838 56.107 ;
     RECT  32.292 55.819 51.606 56.227 ;
     RECT  52.416 55.051 53.01 56.227 ;
     RECT  0.216 55.627 0.342 56.299 ;
     RECT  15.084 56.101 31.302 56.299 ;
     RECT  0.144 56.299 0.342 56.399 ;
     RECT  14.832 56.299 31.302 56.399 ;
     RECT  53.82 56.107 53.91 56.399 ;
     RECT  53.892 56.399 53.91 56.429 ;
     RECT  10.512 55.921 11.754 56.461 ;
     RECT  32.292 56.227 53.01 56.461 ;
     RECT  15.084 56.399 31.302 56.569 ;
     RECT  15.084 56.569 31.41 56.669 ;
     RECT  2.304 56.057 3.114 56.875 ;
     RECT  3.888 56.057 9.666 56.875 ;
     RECT  32.184 56.461 53.01 56.971 ;
     RECT  23.364 56.669 31.41 57.001 ;
     RECT  32.184 56.971 53.046 57.001 ;
     RECT  23.364 57.001 53.046 57.101 ;
     RECT  52.344 57.101 53.046 57.259 ;
     RECT  0.324 56.399 0.342 57.307 ;
     RECT  52.344 57.259 53.73 57.335 ;
     RECT  52.416 57.335 53.73 57.389 ;
     RECT  52.416 57.389 53.082 57.407 ;
     RECT  2.304 56.875 9.666 57.547 ;
     RECT  52.992 57.407 53.082 57.569 ;
     RECT  23.364 57.101 51.606 57.839 ;
     RECT  23.364 57.839 51.534 58.109 ;
     RECT  0.144 57.307 0.342 58.123 ;
     RECT  0.108 58.123 0.342 58.22 ;
     RECT  15.084 56.669 22.59 58.225 ;
     RECT  23.364 58.109 47.142 58.225 ;
     RECT  0.144 58.22 0.342 58.253 ;
     RECT  2.268 57.547 9.666 58.261 ;
     RECT  53.028 57.569 53.082 58.315 ;
     RECT  2.232 58.261 9.666 58.349 ;
     RECT  15.084 58.225 47.142 58.379 ;
     RECT  52.416 58.315 53.082 58.451 ;
     RECT  52.596 58.451 53.082 58.523 ;
     RECT  52.992 58.523 53.082 58.649 ;
     RECT  15.084 58.379 31.338 58.729 ;
     RECT  14.868 58.729 31.338 58.919 ;
     RECT  0.144 58.253 0.234 58.973 ;
     RECT  53.892 58.117 53.91 58.987 ;
     RECT  0.504 58.999 0.522 59.071 ;
     RECT  32.148 58.379 47.142 59.071 ;
     RECT  47.88 58.109 51.534 59.071 ;
     RECT  15.084 58.919 31.338 59.161 ;
     RECT  32.148 59.071 51.534 59.161 ;
     RECT  0.504 59.071 0.558 59.309 ;
     RECT  15.084 59.161 51.534 59.539 ;
     RECT  52.992 58.649 53.01 59.563 ;
     RECT  15.084 59.539 51.606 59.597 ;
     RECT  52.416 59.563 53.01 59.765 ;
     RECT  15.084 59.597 51.57 59.789 ;
     RECT  52.416 59.765 52.974 59.789 ;
     RECT  15.084 59.789 51.534 59.881 ;
     RECT  14.868 59.881 51.534 60.07 ;
     RECT  2.268 58.349 9.666 60.125 ;
     RECT  14.832 60.07 51.534 60.179 ;
     RECT  0.504 59.309 0.522 60.269 ;
     RECT  14.868 60.179 51.534 60.269 ;
     RECT  53.856 58.987 53.91 60.349 ;
     RECT  2.304 60.125 9.666 60.385 ;
     RECT  53.784 60.349 53.91 60.427 ;
     RECT  0.144 60.427 0.162 60.605 ;
     RECT  53.712 60.427 53.91 60.653 ;
     RECT  52.416 59.789 52.434 60.811 ;
     RECT  52.416 60.811 53.046 60.941 ;
     RECT  14.868 60.269 51.498 60.989 ;
     RECT  2.304 60.385 9.702 61.003 ;
     RECT  15.084 60.989 51.498 61.189 ;
     RECT  53.784 60.653 53.91 61.229 ;
     RECT  15.084 61.189 51.606 61.483 ;
     RECT  52.416 60.941 53.01 61.483 ;
     RECT  15.084 61.483 53.01 61.529 ;
     RECT  0.324 61.579 0.342 61.709 ;
     RECT  0.144 61.771 0.162 61.949 ;
     RECT  53.82 61.229 53.91 61.997 ;
     RECT  52.38 61.529 53.01 62.159 ;
     RECT  52.38 62.159 52.974 62.189 ;
     RECT  53.82 61.997 53.874 62.347 ;
     RECT  15.084 61.529 51.534 62.509 ;
     RECT  2.268 61.003 9.702 62.635 ;
     RECT  52.38 62.189 52.434 62.669 ;
     RECT  14.832 62.509 51.534 62.699 ;
     RECT  2.232 62.635 9.702 62.807 ;
     RECT  53.712 62.347 53.874 62.827 ;
     RECT  53.712 62.827 53.91 62.923 ;
     RECT  15.084 62.699 51.534 62.969 ;
     RECT  53.676 62.923 53.91 63.077 ;
     RECT  53.676 63.077 53.802 63.085 ;
     RECT  0.144 63.067 0.162 63.245 ;
     RECT  2.268 62.807 9.702 63.382 ;
     RECT  52.956 63.085 53.802 63.499 ;
     RECT  2.268 63.382 9.738 63.509 ;
     RECT  52.848 63.499 53.802 63.821 ;
     RECT  15.084 62.969 51.498 63.823 ;
     RECT  2.268 63.509 9.666 63.923 ;
     RECT  53.82 63.823 53.982 64.157 ;
     RECT  52.848 63.821 53.046 64.205 ;
     RECT  53.892 64.157 53.982 64.229 ;
     RECT  52.848 64.205 53.01 64.291 ;
     RECT  15.084 63.823 51.534 64.363 ;
     RECT  0.324 64.267 0.342 64.397 ;
     RECT  15.084 64.363 51.714 64.493 ;
     RECT  2.304 63.923 9.666 64.561 ;
     RECT  10.512 56.461 12.258 64.561 ;
     RECT  15.084 64.493 51.534 64.589 ;
     RECT  52.452 64.291 53.01 64.651 ;
     RECT  0.144 64.747 0.162 64.925 ;
     RECT  13.215 55.687 13.95 64.975 ;
     RECT  15.084 64.589 51.498 64.975 ;
     RECT  13.215 64.975 51.498 65.201 ;
     RECT  53.964 64.229 53.982 65.227 ;
     RECT  0.18 65.323 0.342 65.549 ;
     RECT  15.084 65.201 51.498 65.611 ;
     RECT  53.892 65.227 53.982 65.659 ;
     RECT  2.304 64.561 12.258 65.749 ;
     RECT  53.82 65.659 53.982 65.947 ;
     RECT  0.144 65.947 0.162 66.125 ;
     RECT  53.784 65.947 53.982 66.289 ;
     RECT  52.38 64.651 53.01 66.475 ;
     RECT  2.268 65.749 12.258 66.515 ;
     RECT  52.344 66.475 53.01 66.605 ;
     RECT  15.084 65.611 51.57 66.667 ;
     RECT  53.748 66.289 53.982 66.785 ;
     RECT  15.084 66.667 51.894 66.797 ;
     RECT  52.992 66.605 53.01 66.955 ;
     RECT  53.748 66.785 53.91 66.955 ;
     RECT  13.215 65.201 14.274 67.099 ;
     RECT  15.084 66.797 51.57 67.099 ;
     RECT  52.992 66.955 53.91 67.133 ;
     RECT  13.215 67.099 51.57 67.199 ;
     RECT  15.084 67.199 51.57 67.289 ;
     RECT  28.26 67.289 51.57 67.421 ;
     RECT  13.215 67.199 14.274 67.469 ;
     RECT  28.332 67.421 51.57 67.595 ;
     RECT  0.324 67.531 0.342 67.661 ;
     RECT  52.992 67.133 53.046 67.723 ;
     RECT  15.084 67.289 27.522 67.945 ;
     RECT  52.92 67.723 53.046 68.011 ;
     RECT  53.82 67.133 53.91 68.011 ;
     RECT  28.908 67.595 51.57 68.099 ;
     RECT  52.92 68.011 53.91 68.141 ;
     RECT  14.832 67.945 27.522 68.171 ;
     RECT  26.064 68.171 27.522 68.279 ;
     RECT  2.304 66.515 12.258 68.587 ;
     RECT  52.92 68.141 53.082 68.747 ;
     RECT  0.144 68.779 0.162 68.957 ;
     RECT  14.868 68.171 25.218 69.061 ;
     RECT  52.956 68.747 53.082 69.067 ;
     RECT  53.82 68.141 53.91 69.067 ;
     RECT  14.832 69.061 25.218 69.449 ;
     RECT  52.956 69.067 53.91 69.643 ;
     RECT  26.172 68.279 27.522 69.791 ;
     RECT  2.268 68.587 12.258 69.899 ;
     RECT  15.084 69.449 25.218 69.989 ;
     RECT  52.452 69.643 53.91 70.061 ;
     RECT  28.908 68.099 51.498 70.141 ;
     RECT  20.196 69.989 25.218 70.339 ;
     RECT  26.172 69.791 27.342 70.339 ;
     RECT  52.452 70.061 53.838 70.367 ;
     RECT  28.908 70.141 51.534 70.459 ;
     RECT  0.144 70.411 0.162 70.507 ;
     RECT  52.956 70.367 53.838 70.541 ;
     RECT  0.144 70.507 0.342 70.589 ;
     RECT  0.324 70.589 0.342 70.637 ;
     RECT  28.908 70.459 52.146 70.637 ;
     RECT  2.268 69.899 3.654 70.915 ;
     RECT  28.908 70.637 30.87 70.943 ;
     RECT  13.215 67.469 13.95 70.979 ;
     RECT  53.604 70.541 53.838 70.987 ;
     RECT  20.196 70.339 27.342 71.041 ;
     RECT  2.268 70.915 3.726 71.069 ;
     RECT  20.196 71.041 27.378 71.105 ;
     RECT  26.172 71.105 27.378 71.213 ;
     RECT  28.908 70.943 30.798 71.213 ;
     RECT  31.932 70.637 52.146 71.227 ;
     RECT  31.932 71.227 52.434 71.275 ;
     RECT  53.604 70.987 53.91 71.275 ;
     RECT  13.215 70.979 13.497 71.311 ;
     RECT  13.104 71.311 13.497 71.357 ;
     RECT  2.268 71.069 3.618 71.375 ;
     RECT  31.932 71.275 53.91 71.375 ;
     RECT  32.004 71.375 53.91 71.447 ;
     RECT  32.004 71.447 52.866 71.501 ;
     RECT  32.004 71.501 52.434 71.609 ;
     RECT  2.304 71.375 3.618 71.645 ;
     RECT  53.64 71.447 53.91 71.693 ;
     RECT  53.676 71.693 53.91 71.789 ;
     RECT  2.376 71.645 3.618 71.879 ;
     RECT  4.464 69.899 12.258 71.879 ;
     RECT  32.292 71.609 52.434 71.879 ;
     RECT  20.196 71.105 25.218 72.121 ;
     RECT  26.172 71.213 27.342 72.121 ;
     RECT  34.524 71.879 52.434 72.149 ;
     RECT  20.196 72.121 27.342 72.221 ;
     RECT  4.572 71.879 12.258 72.257 ;
     RECT  0.144 72.187 0.162 72.365 ;
     RECT  34.524 72.149 51.534 72.419 ;
     RECT  2.376 71.879 3.078 72.427 ;
     RECT  53.712 71.789 53.91 72.523 ;
     RECT  53.604 72.523 53.91 72.653 ;
     RECT  2.304 72.427 3.078 72.733 ;
     RECT  2.304 72.733 3.654 72.769 ;
     RECT  52.344 72.149 52.434 72.845 ;
     RECT  2.304 72.769 3.798 73.003 ;
     RECT  4.608 72.257 12.258 73.003 ;
     RECT  34.524 72.419 51.498 73.345 ;
     RECT  53.712 72.653 53.91 73.421 ;
     RECT  2.304 73.003 12.258 73.483 ;
     RECT  32.292 71.879 33.714 73.571 ;
     RECT  52.452 73.201 52.47 73.579 ;
     RECT  2.268 73.483 12.258 73.643 ;
     RECT  53.784 73.421 53.91 73.643 ;
     RECT  52.416 73.579 52.47 73.804 ;
     RECT  52.416 73.804 52.506 73.805 ;
     RECT  52.488 73.805 52.506 73.867 ;
     RECT  52.488 73.867 52.974 73.963 ;
     RECT  15.084 69.989 18.897 74.075 ;
     RECT  52.488 73.963 53.046 74.093 ;
     RECT  15.696 74.075 18.897 74.219 ;
     RECT  52.92 74.093 53.046 74.285 ;
     RECT  2.304 73.643 12.258 74.345 ;
     RECT  0.324 73.963 0.342 74.381 ;
     RECT  28.908 71.213 30.546 74.425 ;
     RECT  2.304 74.345 12.078 74.443 ;
     RECT  34.524 73.345 51.534 74.461 ;
     RECT  20.196 72.221 25.326 74.489 ;
     RECT  34.524 74.461 51.642 74.579 ;
     RECT  52.92 74.285 53.01 74.579 ;
     RECT  2.232 74.443 12.078 74.687 ;
     RECT  20.196 74.489 21.942 74.723 ;
     RECT  53.856 73.643 53.91 74.731 ;
     RECT  32.508 73.571 33.714 74.759 ;
     RECT  53.82 74.731 53.91 74.827 ;
     RECT  52.92 74.579 52.974 74.849 ;
     RECT  0.144 74.731 0.162 74.909 ;
     RECT  32.508 74.759 32.526 74.965 ;
     RECT  34.524 74.579 51.534 74.993 ;
     RECT  52.92 74.849 52.938 75.019 ;
     RECT  52.416 75.019 52.938 75.211 ;
     RECT  16.236 74.219 18.897 75.299 ;
     RECT  34.632 74.993 51.534 75.469 ;
     RECT  52.38 75.211 52.938 75.469 ;
     RECT  16.308 75.299 18.897 75.659 ;
     RECT  31.932 74.965 32.526 75.659 ;
     RECT  34.632 75.469 52.938 75.695 ;
     RECT  36.396 75.695 52.938 75.725 ;
     RECT  28.908 74.425 31.05 75.839 ;
     RECT  53.784 74.827 53.91 75.979 ;
     RECT  53.712 75.979 53.91 76.037 ;
     RECT  20.196 74.723 21.438 76.073 ;
     RECT  36.396 75.725 51.534 76.199 ;
     RECT  16.344 75.659 18.897 76.235 ;
     RECT  53.712 76.037 53.874 76.253 ;
     RECT  16.344 76.235 16.362 76.307 ;
     RECT  20.196 76.073 20.25 76.343 ;
     RECT  53.784 76.253 53.874 76.349 ;
     RECT  52.344 75.725 52.938 76.363 ;
     RECT  28.908 75.839 30.258 76.379 ;
     RECT  28.908 76.379 29.697 76.505 ;
     RECT  36.396 76.199 51.498 76.505 ;
     RECT  52.344 76.363 52.974 76.555 ;
     RECT  2.268 74.687 12.078 76.577 ;
     RECT  32.508 75.659 32.526 76.775 ;
     RECT  52.344 76.555 53.046 76.811 ;
     RECT  36.396 76.505 51.462 76.883 ;
     RECT  2.304 76.577 12.078 76.919 ;
     RECT  52.38 76.811 53.046 77.081 ;
     RECT  0.144 76.075 0.162 77.117 ;
     RECT  2.304 76.919 11.214 77.189 ;
     RECT  22.716 74.489 25.326 77.359 ;
     RECT  26.208 72.221 27.342 77.359 ;
     RECT  52.452 77.081 53.046 77.387 ;
     RECT  36.432 76.883 51.462 77.423 ;
     RECT  36.756 77.423 51.462 77.431 ;
     RECT  22.716 77.359 27.342 77.459 ;
     RECT  33.264 74.759 33.714 77.549 ;
     RECT  22.716 77.459 25.182 77.585 ;
     RECT  53.82 76.349 53.874 77.611 ;
     RECT  22.896 77.585 25.182 77.657 ;
     RECT  2.304 77.189 10.782 77.729 ;
     RECT  0.324 77.803 0.342 77.851 ;
     RECT  36.756 77.431 51.534 77.893 ;
     RECT  0.144 77.851 0.342 77.933 ;
     RECT  2.304 77.729 10.638 77.999 ;
     RECT  0.144 77.933 0.162 78.029 ;
     RECT  2.304 77.999 9.99 78.169 ;
     RECT  2.268 78.169 9.99 78.173 ;
     RECT  2.268 78.173 9.954 78.197 ;
     RECT  26.208 77.459 27.342 78.241 ;
     RECT  53.82 77.611 53.91 78.268 ;
     RECT  36.756 77.893 51.894 78.269 ;
     RECT  2.268 78.197 2.697 78.317 ;
     RECT  25.992 78.241 27.342 78.331 ;
     RECT  37.044 78.269 51.894 78.359 ;
     RECT  52.92 77.387 53.046 78.379 ;
     RECT  34.632 75.695 35.55 78.431 ;
     RECT  22.896 77.657 24.894 78.439 ;
     RECT  25.632 78.331 27.342 78.439 ;
     RECT  53.784 78.268 53.91 78.467 ;
     RECT  52.884 78.379 53.046 78.475 ;
     RECT  52.848 78.475 53.046 78.701 ;
     RECT  52.848 78.701 53.01 78.763 ;
     RECT  17.172 76.235 18.897 78.871 ;
     RECT  3.456 78.197 9.954 79.007 ;
     RECT  0.324 78.859 0.342 79.051 ;
     RECT  22.824 78.439 27.342 79.051 ;
     RECT  2.304 78.317 2.697 79.141 ;
     RECT  3.456 79.007 3.474 79.141 ;
     RECT  47.916 78.359 51.894 79.147 ;
     RECT  52.668 78.763 53.01 79.147 ;
     RECT  4.32 79.007 9.954 79.169 ;
     RECT  47.916 79.147 53.01 79.213 ;
     RECT  0.144 79.051 0.342 79.229 ;
     RECT  22.824 79.051 27.666 79.249 ;
     RECT  47.88 79.213 53.01 79.277 ;
     RECT  37.044 78.359 46.926 79.411 ;
     RECT  47.88 79.277 51.642 79.411 ;
     RECT  52.38 79.277 53.01 79.435 ;
     RECT  53.856 78.467 53.91 79.435 ;
     RECT  22.824 79.249 27.774 79.439 ;
     RECT  22.824 79.439 27.594 79.475 ;
     RECT  52.38 79.435 53.91 79.565 ;
     RECT  52.38 79.565 53.046 79.661 ;
     RECT  17.172 78.871 18.954 79.709 ;
     RECT  22.824 79.475 27.342 79.781 ;
     RECT  37.044 79.411 51.642 79.817 ;
     RECT  2.304 79.141 3.474 79.861 ;
     RECT  4.428 79.169 9.954 79.951 ;
     RECT  20.196 76.343 20.214 79.979 ;
     RECT  37.044 79.817 51.534 79.979 ;
     RECT  22.86 79.781 27.342 80.015 ;
     RECT  47.232 79.979 51.534 80.015 ;
     RECT  2.304 79.861 3.546 80.023 ;
     RECT  4.32 79.951 9.954 80.023 ;
     RECT  0.324 79.229 0.342 80.045 ;
     RECT  2.304 80.023 9.954 80.107 ;
     RECT  22.86 80.015 25.362 80.123 ;
     RECT  23.004 80.123 25.362 80.159 ;
     RECT  10.836 79.951 10.854 80.249 ;
     RECT  23.004 80.159 25.146 80.249 ;
     RECT  26.1 80.015 27.342 80.285 ;
     RECT  33.696 77.549 33.714 80.357 ;
     RECT  2.232 80.107 9.954 80.393 ;
     RECT  52.38 79.661 53.01 80.395 ;
     RECT  53.784 79.565 53.91 80.395 ;
     RECT  37.044 79.979 46.494 80.429 ;
     RECT  23.004 80.249 24.93 80.519 ;
     RECT  43.488 80.429 46.494 80.555 ;
     RECT  0.216 80.395 0.234 80.573 ;
     RECT  34.632 78.431 35.097 80.591 ;
     RECT  37.044 80.429 42.75 80.663 ;
     RECT  37.944 80.663 42.75 80.699 ;
     RECT  47.232 80.015 51.498 80.875 ;
     RECT  52.38 80.395 53.91 80.875 ;
     RECT  43.524 80.555 46.494 80.923 ;
     RECT  47.232 80.875 53.91 80.923 ;
     RECT  26.64 80.285 27.342 80.969 ;
     RECT  23.364 80.519 24.93 81.139 ;
     RECT  26.64 80.969 26.874 81.211 ;
     RECT  23.364 81.139 25.362 81.337 ;
     RECT  23.04 81.337 25.362 81.403 ;
     RECT  26.172 81.211 26.874 81.403 ;
     RECT  38.232 80.699 42.75 81.481 ;
     RECT  43.524 80.923 53.91 81.481 ;
     RECT  38.232 81.481 53.91 81.599 ;
     RECT  2.268 80.393 9.954 81.707 ;
     RECT  0.216 81.691 0.234 81.739 ;
     RECT  37.044 80.663 37.062 81.779 ;
     RECT  0.144 81.739 0.234 81.835 ;
     RECT  38.232 81.599 46.998 81.869 ;
     RECT  47.772 81.599 53.91 81.949 ;
     RECT  23.04 81.403 26.874 82.147 ;
     RECT  0.144 81.835 0.342 82.219 ;
     RECT  22.896 82.147 26.874 82.219 ;
     RECT  47.772 81.949 53.982 82.247 ;
     RECT  0.108 82.219 0.342 82.319 ;
     RECT  38.232 81.869 38.25 82.319 ;
     RECT  27.648 81.445 27.666 82.409 ;
     RECT  0.144 82.319 0.342 82.445 ;
     RECT  34.815 80.591 35.097 82.489 ;
     RECT  0.144 82.445 0.27 82.493 ;
     RECT  39.276 81.869 46.998 82.525 ;
     RECT  47.772 82.247 52.83 82.525 ;
     RECT  22.824 82.219 26.874 82.553 ;
     RECT  2.304 81.707 9.954 82.555 ;
     RECT  34.776 82.489 35.097 82.589 ;
     RECT  22.824 82.553 25.614 82.679 ;
     RECT  26.64 82.553 26.874 82.679 ;
     RECT  31.032 75.839 31.05 82.859 ;
     RECT  22.824 82.679 25.398 82.949 ;
     RECT  0.144 82.493 0.162 82.973 ;
     RECT  2.196 82.555 9.954 82.985 ;
     RECT  26.64 82.679 26.73 83.057 ;
     RECT  39.276 82.525 52.83 83.093 ;
     RECT  39.78 83.093 47.034 83.219 ;
     RECT  10.764 82.723 10.782 83.227 ;
     RECT  10.764 83.227 10.818 83.263 ;
     RECT  47.88 83.093 52.83 83.299 ;
     RECT  53.676 82.247 53.982 83.299 ;
     RECT  22.824 82.949 24.426 83.327 ;
     RECT  39.78 83.219 46.962 83.327 ;
     RECT  22.824 83.327 22.842 83.363 ;
     RECT  39.888 83.327 46.962 83.363 ;
     RECT  47.88 83.299 53.982 83.405 ;
     RECT  25.38 82.949 25.398 83.489 ;
     RECT  40.215 83.363 40.662 83.489 ;
     RECT  41.58 83.363 46.962 83.525 ;
     RECT  2.232 82.985 9.954 83.597 ;
     RECT  43.668 83.525 46.962 83.597 ;
     RECT  53.676 83.405 53.982 83.597 ;
     RECT  10.728 83.263 10.818 83.669 ;
     RECT  2.268 83.597 9.954 83.759 ;
     RECT  23.94 83.327 24.426 83.759 ;
     RECT  27.936 82.561 27.954 83.759 ;
     RECT  41.58 83.525 42.894 83.759 ;
     RECT  41.58 83.759 42.786 83.795 ;
     RECT  43.74 83.597 46.962 83.795 ;
     RECT  23.94 83.759 24.297 83.831 ;
     RECT  41.58 83.795 42.174 83.831 ;
     RECT  41.652 83.831 42.174 84.029 ;
     RECT  43.92 83.795 46.962 84.037 ;
     RECT  47.88 83.405 52.83 84.037 ;
     RECT  0.324 83.563 0.342 84.043 ;
     RECT  0.108 84.043 0.342 84.077 ;
     RECT  26.64 83.057 26.658 84.137 ;
     RECT  38.772 84.109 38.79 84.209 ;
     RECT  43.92 84.037 52.83 84.209 ;
     RECT  2.268 83.759 8.982 84.299 ;
     RECT  41.652 84.029 41.67 84.299 ;
     RECT  45.036 84.209 52.83 84.299 ;
     RECT  0.108 84.077 0.126 84.365 ;
     RECT  2.268 84.299 6.066 84.371 ;
     RECT  46.764 84.299 52.83 84.371 ;
     RECT  6.84 84.299 8.982 84.479 ;
     RECT  46.944 84.371 52.83 84.479 ;
     RECT  8.964 84.479 8.982 84.569 ;
     RECT  6.84 84.479 8.154 84.641 ;
     RECT  2.268 84.371 5.634 84.677 ;
     RECT  7.815 84.641 8.154 84.713 ;
     RECT  46.944 84.479 52.758 84.749 ;
     RECT  2.304 84.677 5.634 84.839 ;
     RECT  45.036 84.299 45.897 84.839 ;
     RECT  47.88 84.749 52.758 84.911 ;
     RECT  53.784 83.597 53.982 84.911 ;
     RECT  6.84 84.641 6.858 85.019 ;
     RECT  5.616 84.839 5.634 85.109 ;
     RECT  48.744 84.911 52.758 85.109 ;
     RECT  2.304 84.839 4.662 85.145 ;
     RECT  2.304 85.145 4.554 85.217 ;
     RECT  2.304 85.217 4.014 85.253 ;
     RECT  2.304 85.253 3.33 85.379 ;
     RECT  46.944 84.749 46.962 85.379 ;
     RECT  2.304 85.379 2.697 85.415 ;
     RECT  48.816 85.109 52.758 85.451 ;
     RECT  2.34 85.415 2.697 85.487 ;
     RECT  53.856 84.911 53.982 85.559 ;
     RECT  53.892 85.559 53.982 85.649 ;
     RECT  49.032 85.451 52.758 85.685 ;
     RECT  49.032 85.685 49.05 85.757 ;
     RECT  50.148 85.685 52.758 85.919 ;
     RECT  50.148 85.919 51.714 86.027 ;
     RECT  50.688 86.027 51.714 86.189 ;
     RECT  52.704 85.919 52.758 86.189 ;
     RECT  50.904 86.189 51.714 86.369 ;
     RECT  53.964 85.649 53.982 86.459 ;
     RECT  50.904 86.369 51.678 86.567 ;
     RECT  50.904 86.567 51.606 86.729 ;
     RECT  50.904 86.729 51.498 86.765 ;
     RECT  52.74 86.189 52.758 86.999 ;
     RECT  51.015 86.765 51.498 87.035 ;
     RECT  12.06 76.919 12.078 100.843 ;
     RECT  12.06 100.843 12.366 101.011 ;
     RECT  11.808 101.011 12.366 101.069 ;
     RECT  12.06 101.069 12.366 101.731 ;
     RECT  13.215 71.357 13.497 101.731 ;
     RECT  9.936 83.759 9.954 101.849 ;
     RECT  12.06 101.731 13.497 101.885 ;
     RECT  17.172 79.709 18.897 125.609 ;
     RECT  16.344 101.857 16.362 125.653 ;
     RECT  16.164 125.653 16.362 125.761 ;
     RECT  17.172 125.609 17.262 125.761 ;
     RECT  16.164 125.761 17.262 126.149 ;
     RECT  16.164 126.149 17.01 126.419 ;
     RECT  16.164 126.419 16.902 126.959 ;
     RECT  16.164 126.959 16.29 127.111 ;
     RECT  2.415 85.487 2.697 127.187 ;
     RECT  7.815 84.713 8.097 127.187 ;
     RECT  13.215 101.885 13.497 127.187 ;
     RECT  18.615 125.609 18.897 127.187 ;
     RECT  24.015 83.831 24.297 127.187 ;
     RECT  29.415 76.505 29.697 127.187 ;
     RECT  34.815 82.589 35.097 127.187 ;
     RECT  40.215 83.489 40.497 127.187 ;
     RECT  45.615 84.839 45.897 127.187 ;
     RECT  51.015 87.035 51.297 127.187 ;
     RECT  15.948 127.111 16.29 127.345 ;
     RECT  15.732 127.345 16.29 127.421 ;
     RECT  2.415 127.187 2.505 127.457 ;
     RECT  7.815 127.187 7.905 127.457 ;
     RECT  13.215 127.187 13.305 127.457 ;
     RECT  18.615 127.187 18.705 127.457 ;
     RECT  24.015 127.187 24.105 127.457 ;
     RECT  29.415 127.187 29.505 127.457 ;
     RECT  34.815 127.187 34.905 127.457 ;
     RECT  40.215 127.187 40.305 127.457 ;
     RECT  45.615 127.187 45.705 127.457 ;
     RECT  51.015 127.187 51.105 127.457 ;
     RECT  15.732 127.421 16.182 127.613 ;
     RECT  15.732 127.613 16.038 127.661 ;
     RECT  15.732 127.661 15.75 128.861 ;
    LAYER M4 ;
     RECT  0.06 49.008 0.097 84.264 ;
     RECT  0.097 49.008 0.569 84.36 ;
     RECT  0.569 49.2 2.408 84.36 ;
     RECT  2.408 2.148 2.512 127.452 ;
     RECT  2.512 2.418 2.704 127.182 ;
     RECT  2.704 49.488 2.837 77.928 ;
     RECT  2.704 79.44 2.837 84.072 ;
     RECT  2.837 49.872 2.839 77.928 ;
     RECT  2.839 49.872 2.867 71.208 ;
     RECT  2.867 49.872 2.873 54.792 ;
     RECT  2.867 55.872 2.873 71.208 ;
     RECT  2.837 79.44 2.873 83.016 ;
     RECT  2.839 72.192 2.909 77.928 ;
     RECT  2.873 66.864 2.945 68.52 ;
     RECT  2.873 69.744 2.945 71.208 ;
     RECT  2.873 51.648 3.017 54.792 ;
     RECT  2.909 73.296 3.017 77.928 ;
     RECT  2.873 80.304 3.017 83.016 ;
     RECT  2.909 72.192 3.089 72.216 ;
     RECT  3.017 73.296 3.089 77.88 ;
     RECT  2.873 55.872 3.125 65.448 ;
     RECT  2.945 67.536 3.125 68.52 ;
     RECT  3.125 55.872 3.197 63.096 ;
     RECT  3.017 80.304 3.197 80.856 ;
     RECT  2.837 84 3.197 84.072 ;
     RECT  2.945 69.744 3.233 70.632 ;
     RECT  3.197 80.304 3.233 80.568 ;
     RECT  2.873 49.872 3.305 50.664 ;
     RECT  3.125 64.08 3.305 65.448 ;
     RECT  3.233 70.368 3.305 70.632 ;
     RECT  3.089 73.824 3.305 77.88 ;
     RECT  3.233 80.544 3.305 80.568 ;
     RECT  3.125 67.536 3.377 68.232 ;
     RECT  3.305 70.608 3.377 70.632 ;
     RECT  3.305 73.824 3.377 77.64 ;
     RECT  3.305 64.08 3.521 64.92 ;
     RECT  3.017 81.936 3.985 82.872 ;
     RECT  3.305 49.872 4.021 49.896 ;
     RECT  3.197 62.544 4.093 63.096 ;
     RECT  3.017 51.792 4.129 54.792 ;
     RECT  3.197 55.872 4.129 61.464 ;
     RECT  4.129 51.792 4.165 61.464 ;
     RECT  4.093 62.544 4.165 63.144 ;
     RECT  3.197 84 4.237 84.024 ;
     RECT  3.377 76.272 4.273 77.64 ;
     RECT  4.021 49.344 4.307 49.896 ;
     RECT  4.237 66.288 4.309 66.312 ;
     RECT  4.273 76.272 4.345 78.072 ;
     RECT  4.307 49.488 4.381 49.896 ;
     RECT  3.985 81.792 4.381 82.872 ;
     RECT  4.237 84 4.381 84.216 ;
     RECT  4.381 81.36 4.453 82.872 ;
     RECT  4.381 84 4.453 84.312 ;
     RECT  3.377 73.968 4.489 74.856 ;
     RECT  4.345 76.272 4.489 78.12 ;
     RECT  4.381 49.488 4.525 50.76 ;
     RECT  4.165 51.792 4.525 63.144 ;
     RECT  4.453 80.4 4.525 82.872 ;
     RECT  4.453 84 4.525 84.408 ;
     RECT  3.521 64.896 4.597 64.92 ;
     RECT  4.309 66.24 4.597 66.312 ;
     RECT  3.377 67.536 4.597 67.848 ;
     RECT  4.453 69.072 4.813 69.096 ;
     RECT  4.489 73.968 4.849 78.12 ;
     RECT  4.525 71.28 4.921 71.304 ;
     RECT  4.525 80.4 4.921 84.408 ;
     RECT  4.525 49.488 5.029 63.144 ;
     RECT  4.813 68.976 5.029 69.096 ;
     RECT  4.921 70.32 5.029 71.304 ;
     RECT  4.849 73.248 5.069 78.12 ;
     RECT  5.029 49.488 5.141 63.24 ;
     RECT  5.029 68.88 5.173 71.304 ;
     RECT  5.069 73.248 5.173 74.088 ;
     RECT  4.597 64.656 5.317 64.92 ;
     RECT  4.597 66.24 5.317 67.848 ;
     RECT  5.069 75.168 5.461 78.12 ;
     RECT  5.317 64.656 5.569 67.848 ;
     RECT  5.173 68.88 5.569 71.4 ;
     RECT  4.921 79.44 5.609 84.408 ;
     RECT  5.569 64.656 5.677 71.4 ;
     RECT  5.141 50.736 5.825 63.24 ;
     RECT  5.173 72.864 6.037 74.088 ;
     RECT  5.461 75.168 6.037 78.36 ;
     RECT  5.825 51.216 6.301 63.24 ;
     RECT  5.141 49.488 6.323 49.752 ;
     RECT  5.677 64.32 6.325 71.4 ;
     RECT  5.609 79.44 6.329 82.872 ;
     RECT  6.301 54.096 6.505 63.24 ;
     RECT  6.325 64.32 6.505 71.496 ;
     RECT  6.329 81.024 6.604 82.872 ;
     RECT  6.604 81.024 6.625 81.528 ;
     RECT  6.625 81.024 6.653 81.48 ;
     RECT  6.037 72.864 6.725 78.36 ;
     RECT  6.505 54.096 6.744 71.496 ;
     RECT  6.744 54.096 6.761 72.408 ;
     RECT  6.323 49.488 6.829 49.512 ;
     RECT  6.604 82.656 6.829 82.872 ;
     RECT  6.301 51.216 6.901 53.112 ;
     RECT  6.725 73.776 7.189 78.36 ;
     RECT  6.329 79.44 7.189 80.04 ;
     RECT  6.829 49.248 7.549 49.512 ;
     RECT  6.901 50.544 7.549 53.112 ;
     RECT  7.549 49.248 7.808 53.112 ;
     RECT  6.761 54.096 7.808 68.52 ;
     RECT  6.761 70.128 7.808 72.408 ;
     RECT  7.189 73.776 7.808 80.04 ;
     RECT  6.653 81.456 7.808 81.48 ;
     RECT  6.829 82.656 7.808 82.92 ;
     RECT  5.609 84.384 7.808 84.408 ;
     RECT  6.517 101.04 7.808 101.064 ;
     RECT  7.808 2.148 7.912 127.452 ;
     RECT  7.912 2.418 8.104 127.182 ;
     RECT  8.104 58.416 8.165 63.912 ;
     RECT  8.104 79.2 8.201 79.224 ;
     RECT  8.104 70.56 8.243 71.352 ;
     RECT  8.104 83.52 8.243 84.408 ;
     RECT  8.243 70.704 8.245 71.352 ;
     RECT  8.104 49.68 8.291 53.496 ;
     RECT  8.104 64.896 8.345 66.6 ;
     RECT  8.104 54.96 8.381 57.384 ;
     RECT  8.165 58.416 8.417 63.624 ;
     RECT  8.104 67.68 8.417 69.24 ;
     RECT  8.104 76.224 8.417 77.064 ;
     RECT  8.243 83.52 8.453 83.544 ;
     RECT  8.291 49.728 8.483 53.496 ;
     RECT  8.417 67.68 8.561 68.232 ;
     RECT  8.345 65.52 8.597 66.6 ;
     RECT  8.597 65.52 9.173 65.544 ;
     RECT  8.417 76.224 9.281 76.584 ;
     RECT  8.483 49.728 9.353 53.352 ;
     RECT  8.417 58.512 9.385 63.624 ;
     RECT  9.281 76.224 9.425 76.536 ;
     RECT  9.353 50.544 9.713 53.352 ;
     RECT  8.104 101.04 12.332 101.064 ;
     RECT  8.104 22.176 13.208 22.2 ;
     RECT  9.713 50.544 13.208 51.48 ;
     RECT  9.713 52.848 13.208 53.352 ;
     RECT  8.381 54.96 13.208 55.512 ;
     RECT  8.381 56.544 13.208 57.384 ;
     RECT  9.385 58.512 13.208 64.152 ;
     RECT  8.597 66.576 13.208 66.6 ;
     RECT  8.561 68.16 13.208 68.232 ;
     RECT  8.417 69.216 13.208 69.24 ;
     RECT  8.245 71.328 13.208 71.352 ;
     RECT  8.104 74.4 13.208 74.424 ;
     RECT  9.425 76.224 13.208 76.248 ;
     RECT  9.961 78.144 13.208 78.168 ;
     RECT  8.104 82.176 13.208 82.2 ;
     RECT  12.332 100.848 13.208 101.064 ;
     RECT  13.208 2.148 13.312 127.452 ;
     RECT  13.312 2.418 13.504 127.182 ;
     RECT  13.504 22.032 14.821 22.2 ;
     RECT  14.821 21.936 14.969 22.2 ;
     RECT  13.504 50.544 15.877 51.48 ;
     RECT  13.504 52.848 15.877 53.352 ;
     RECT  15.721 128.832 16.019 128.856 ;
     RECT  16.009 127.632 16.114 127.656 ;
     RECT  16.114 127.584 16.115 127.656 ;
     RECT  16.069 0.096 16.124 0.12 ;
     RECT  14.969 21.936 16.211 22.056 ;
     RECT  16.115 127.584 16.22 127.608 ;
     RECT  16.22 127.392 16.237 127.608 ;
     RECT  16.189 1.68 16.253 1.704 ;
     RECT  16.124 0.096 16.261 0.552 ;
     RECT  16.253 1.68 16.261 1.752 ;
     RECT  16.261 0.096 16.265 1.752 ;
     RECT  16.165 6.144 16.301 6.168 ;
     RECT  16.237 127.392 16.307 127.416 ;
     RECT  13.504 101.04 16.355 101.064 ;
     RECT  16.268 125.808 16.355 125.832 ;
     RECT  15.877 50.544 16.441 53.352 ;
     RECT  16.265 0.576 16.657 1.752 ;
     RECT  13.504 54.96 16.657 55.512 ;
     RECT  16.657 0.576 16.729 2.28 ;
     RECT  16.441 50.544 16.729 53.4 ;
     RECT  16.729 0.576 16.813 2.904 ;
     RECT  16.765 4.8 17.053 4.824 ;
     RECT  16.729 50.544 17.089 53.496 ;
     RECT  16.657 54.576 17.089 55.512 ;
     RECT  13.504 58.512 17.089 64.152 ;
     RECT  17.053 4.8 17.165 4.92 ;
     RECT  17.165 4.896 17.273 4.92 ;
     RECT  17.089 58.512 17.273 64.488 ;
     RECT  16.813 0.576 17.413 2.28 ;
     RECT  13.504 71.328 17.449 71.352 ;
     RECT  17.449 71.328 17.561 71.496 ;
     RECT  17.089 50.544 17.605 55.512 ;
     RECT  13.504 56.544 17.605 57.384 ;
     RECT  17.413 0.096 17.651 2.28 ;
     RECT  17.651 0.096 17.939 0.12 ;
     RECT  17.651 1.104 18.131 2.28 ;
     RECT  13.504 69.216 18.169 69.24 ;
     RECT  18.131 1.728 18.181 2.28 ;
     RECT  17.665 5.232 18.529 5.256 ;
     RECT  18.181 1.728 18.601 2.904 ;
     RECT  18.529 5.04 18.601 5.256 ;
     RECT  18.601 1.728 18.608 3.384 ;
     RECT  18.601 5.04 18.608 5.88 ;
     RECT  16.211 22.032 18.608 22.056 ;
     RECT  17.605 50.544 18.608 57.384 ;
     RECT  17.273 58.512 18.608 64.152 ;
     RECT  13.504 66.576 18.608 66.6 ;
     RECT  13.504 68.16 18.608 68.232 ;
     RECT  18.169 69.216 18.608 69.288 ;
     RECT  17.561 71.376 18.608 71.496 ;
     RECT  13.504 74.4 18.608 74.424 ;
     RECT  13.504 76.224 18.608 76.248 ;
     RECT  13.504 78.144 18.608 78.168 ;
     RECT  18.608 1.728 18.712 127.452 ;
     RECT  18.712 1.728 18.904 127.182 ;
     RECT  18.904 68.16 19.037 69.24 ;
     RECT  18.904 2.88 19.181 3.96 ;
     RECT  18.904 5.04 19.181 5.88 ;
     RECT  18.904 1.728 19.289 1.896 ;
     RECT  19.181 2.88 19.289 2.904 ;
     RECT  18.904 22.032 19.667 22.056 ;
     RECT  19.289 1.728 19.757 1.752 ;
     RECT  19.181 5.04 20.261 5.208 ;
     RECT  19.181 3.936 21.049 3.96 ;
     RECT  21.049 3.024 21.269 3.96 ;
     RECT  20.261 5.184 21.589 5.208 ;
     RECT  21.269 3.024 21.809 3.048 ;
     RECT  19.037 68.16 22.741 68.232 ;
     RECT  18.904 71.376 22.885 71.4 ;
     RECT  22.849 82.464 23.033 82.632 ;
     RECT  18.904 66.576 23.569 66.6 ;
     RECT  22.741 67.776 23.569 68.232 ;
     RECT  18.904 54.96 23.641 55.512 ;
     RECT  23.569 66.576 23.893 68.232 ;
     RECT  21.589 4.944 24.008 5.208 ;
     RECT  21.337 49.296 24.008 49.32 ;
     RECT  18.904 51.456 24.008 53.352 ;
     RECT  23.641 54.384 24.008 55.512 ;
     RECT  18.904 56.544 24.008 57.384 ;
     RECT  18.904 58.512 24.008 64.92 ;
     RECT  23.893 66.528 24.008 68.232 ;
     RECT  19.037 69.216 24.008 69.24 ;
     RECT  22.885 71.136 24.008 71.4 ;
     RECT  18.904 74.4 24.008 74.424 ;
     RECT  18.904 76.224 24.008 76.248 ;
     RECT  18.904 78.144 24.008 78.168 ;
     RECT  23.033 82.608 24.008 82.632 ;
     RECT  24.008 2.148 24.112 127.452 ;
     RECT  24.112 2.418 24.304 127.182 ;
     RECT  24.304 71.136 24.509 71.448 ;
     RECT  24.509 71.232 25.369 71.448 ;
     RECT  24.304 54.384 25.429 68.232 ;
     RECT  24.304 69.216 25.429 69.24 ;
     RECT  24.304 51.456 25.445 53.352 ;
     RECT  25.369 71.232 25.801 72.216 ;
     RECT  24.304 78.144 25.909 78.168 ;
     RECT  25.429 54.384 26.773 69.24 ;
     RECT  25.909 78.144 26.777 78.984 ;
     RECT  26.773 54.384 26.885 69.72 ;
     RECT  25.445 51.456 26.924 51.48 ;
     RECT  25.445 52.848 26.924 53.352 ;
     RECT  26.924 51.456 27.011 53.352 ;
     RECT  25.801 70.848 27.011 72.216 ;
     RECT  26.885 54.384 27.029 69.288 ;
     RECT  27.029 54.384 28.073 68.232 ;
     RECT  28.073 56.496 28.289 68.232 ;
     RECT  24.304 4.944 28.537 5.208 ;
     RECT  29.077 1.152 29.171 1.176 ;
     RECT  29.185 1.728 29.257 1.752 ;
     RECT  29.257 1.728 29.365 1.8 ;
     RECT  28.073 54.384 29.401 55.512 ;
     RECT  28.289 56.544 29.401 68.232 ;
     RECT  29.365 1.728 29.408 2.04 ;
     RECT  28.429 3.408 29.408 3.432 ;
     RECT  28.537 4.656 29.408 5.208 ;
     RECT  26.965 44.688 29.408 44.712 ;
     RECT  24.304 49.296 29.408 49.32 ;
     RECT  27.011 51.456 29.408 51.48 ;
     RECT  27.011 52.848 29.408 53.352 ;
     RECT  29.401 54.384 29.408 68.232 ;
     RECT  27.029 69.216 29.408 69.288 ;
     RECT  27.011 70.848 29.408 70.872 ;
     RECT  27.011 71.904 29.408 72.216 ;
     RECT  24.304 74.4 29.408 74.424 ;
     RECT  24.304 76.224 29.408 76.248 ;
     RECT  26.777 78.144 29.408 78.168 ;
     RECT  25.585 81.408 29.408 81.432 ;
     RECT  29.408 1.728 29.512 127.452 ;
     RECT  29.512 1.728 29.704 127.182 ;
     RECT  29.221 0.576 29.953 0.6 ;
     RECT  29.704 54.384 29.981 69.288 ;
     RECT  29.704 1.728 30.131 2.904 ;
     RECT  30.131 2.88 30.341 2.904 ;
     RECT  30.131 1.728 30.733 1.896 ;
     RECT  29.981 56.544 30.733 69.288 ;
     RECT  29.704 70.848 30.733 70.872 ;
     RECT  30.733 1.152 31.229 1.896 ;
     RECT  30.725 0.096 31.385 0.12 ;
     RECT  31.229 1.152 31.388 1.944 ;
     RECT  31.388 1.152 31.475 2.28 ;
     RECT  31.475 1.152 31.741 1.848 ;
     RECT  31.717 2.88 31.993 2.952 ;
     RECT  31.993 2.88 32.293 3.144 ;
     RECT  29.704 4.56 32.293 5.208 ;
     RECT  29.704 52.848 32.425 53.352 ;
     RECT  29.981 54.384 32.425 55.512 ;
     RECT  32.425 52.848 32.437 55.512 ;
     RECT  30.733 56.544 32.437 70.872 ;
     RECT  32.293 2.88 32.537 5.208 ;
     RECT  31.957 6.24 32.537 6.264 ;
     RECT  31.741 1.104 32.54 1.848 ;
     RECT  32.537 2.88 32.54 3.432 ;
     RECT  32.54 1.104 32.723 3.432 ;
     RECT  32.437 52.848 32.749 70.872 ;
     RECT  29.704 71.904 32.749 72.216 ;
     RECT  32.723 1.728 32.897 3.432 ;
     RECT  32.897 2.976 33.041 3.432 ;
     RECT  32.537 4.56 33.257 5.208 ;
     RECT  33.257 4.944 33.937 5.208 ;
     RECT  32.897 1.728 34.009 1.944 ;
     RECT  29.704 74.4 34.453 74.424 ;
     RECT  33.937 4.944 34.729 5.64 ;
     RECT  34.009 1.728 34.808 2.28 ;
     RECT  33.041 3.408 34.808 3.432 ;
     RECT  34.729 4.464 34.808 5.64 ;
     RECT  33.577 6.816 34.808 6.84 ;
     RECT  34.513 18.96 34.808 18.984 ;
     RECT  29.704 44.688 34.808 44.712 ;
     RECT  29.704 49.296 34.808 49.32 ;
     RECT  29.704 50.88 34.808 51.48 ;
     RECT  32.749 52.848 34.808 72.216 ;
     RECT  34.453 73.632 34.808 74.424 ;
     RECT  29.704 76.224 34.808 76.248 ;
     RECT  29.704 78.144 34.808 78.168 ;
     RECT  29.704 81.408 34.808 81.432 ;
     RECT  34.808 1.728 34.912 127.452 ;
     RECT  34.912 1.728 35.104 127.182 ;
     RECT  35.104 52.848 35.129 72.216 ;
     RECT  35.104 1.728 35.165 1.848 ;
     RECT  35.104 2.88 35.165 5.976 ;
     RECT  35.165 1.824 35.201 1.848 ;
     RECT  35.165 3.024 35.237 5.976 ;
     RECT  35.237 3.312 35.381 5.976 ;
     RECT  35.381 3.312 36.137 5.784 ;
     RECT  36.137 4.368 36.605 5.784 ;
     RECT  36.605 4.944 36.713 5.784 ;
     RECT  36.137 3.312 37.073 3.336 ;
     RECT  37.1 42.72 37.187 42.744 ;
     RECT  36.713 4.944 37.331 5.208 ;
     RECT  37.244 42.528 37.331 42.552 ;
     RECT  35.104 50.88 37.58 51.48 ;
     RECT  37.58 50.88 37.667 51.528 ;
     RECT  35.129 52.848 37.829 70.872 ;
     RECT  35.104 49.296 38.761 49.32 ;
     RECT  37.829 52.848 38.761 55.512 ;
     RECT  35.104 73.632 38.761 74.424 ;
     RECT  35.104 81.408 38.761 81.432 ;
     RECT  35.104 78.144 38.833 78.168 ;
     RECT  38.833 78.144 39.121 78.744 ;
     RECT  38.761 52.752 39.409 55.512 ;
     RECT  38.761 81.168 39.445 81.432 ;
     RECT  37.667 50.88 39.481 51.48 ;
     RECT  38.761 49.296 39.589 49.608 ;
     RECT  37.829 56.544 39.589 70.872 ;
     RECT  35.129 71.904 39.589 72.216 ;
     RECT  38.761 73.344 39.661 74.424 ;
     RECT  39.445 81.168 39.697 82.008 ;
     RECT  39.481 50.832 39.769 51.48 ;
     RECT  39.661 73.344 39.805 74.664 ;
     RECT  39.697 81.12 39.805 82.008 ;
     RECT  39.805 73.296 39.841 74.664 ;
     RECT  39.589 56.544 39.877 72.216 ;
     RECT  39.841 73.296 39.985 74.904 ;
     RECT  39.985 73.248 40.057 74.904 ;
     RECT  39.877 56.544 40.129 72.264 ;
     RECT  40.057 73.248 40.129 74.952 ;
     RECT  39.409 52.752 40.165 55.56 ;
     RECT  40.129 56.544 40.165 74.952 ;
     RECT  39.121 78.144 40.165 79.848 ;
     RECT  39.805 81.072 40.165 82.008 ;
     RECT  37.331 4.944 40.208 4.968 ;
     RECT  35.104 18.96 40.208 18.984 ;
     RECT  35.104 44.688 40.208 44.712 ;
     RECT  37.189 47.856 40.208 47.88 ;
     RECT  39.589 48.96 40.208 49.608 ;
     RECT  39.769 50.832 40.208 51.768 ;
     RECT  40.165 52.752 40.208 74.952 ;
     RECT  35.104 76.224 40.208 76.248 ;
     RECT  40.165 78.144 40.208 82.008 ;
     RECT  40.208 2.148 40.312 127.452 ;
     RECT  40.312 2.418 40.504 127.182 ;
     RECT  40.504 45.312 41.641 45.336 ;
     RECT  41.641 44.976 41.891 45.336 ;
     RECT  40.504 47.856 41.965 75.192 ;
     RECT  40.504 76.224 42.109 76.536 ;
     RECT  40.504 78.144 42.181 82.584 ;
     RECT  42.181 78.144 42.325 82.728 ;
     RECT  42.325 78.144 42.545 82.776 ;
     RECT  41.965 47.856 42.721 75.24 ;
     RECT  42.109 76.224 42.721 77.16 ;
     RECT  42.721 47.856 43.009 77.16 ;
     RECT  42.545 78.144 43.009 82.728 ;
     RECT  43.009 47.856 43.121 82.728 ;
     RECT  40.504 4.944 43.619 4.968 ;
     RECT  40.504 18.96 43.667 18.984 ;
     RECT  43.121 47.856 43.949 82.68 ;
     RECT  43.949 47.904 44.149 82.68 ;
     RECT  44.149 47.904 44.413 83.256 ;
     RECT  44.413 47.904 44.633 83.592 ;
     RECT  44.633 47.904 45.608 77.16 ;
     RECT  44.633 78.144 45.608 83.592 ;
     RECT  45.608 2.148 45.712 127.452 ;
     RECT  45.712 2.418 45.904 127.182 ;
     RECT  45.904 76.128 46.289 77.064 ;
     RECT  45.904 47.904 46.325 47.928 ;
     RECT  45.904 78.288 46.433 83.256 ;
     RECT  45.904 50.544 46.469 67.704 ;
     RECT  45.904 68.928 46.505 71.112 ;
     RECT  46.469 50.544 46.541 56.232 ;
     RECT  46.469 57.408 46.613 67.704 ;
     RECT  46.433 78.288 46.613 79.896 ;
     RECT  45.904 48.96 46.649 49.272 ;
     RECT  46.613 79.488 46.685 79.896 ;
     RECT  46.541 51.6 46.721 56.232 ;
     RECT  46.505 69.744 46.721 71.112 ;
     RECT  46.433 80.928 46.721 83.256 ;
     RECT  46.721 80.928 46.757 83.064 ;
     RECT  46.685 79.488 46.793 79.56 ;
     RECT  46.613 78.288 46.901 78.312 ;
     RECT  46.721 69.744 46.937 69.768 ;
     RECT  46.757 80.928 47.009 82.152 ;
     RECT  46.613 58.896 47.185 67.704 ;
     RECT  46.541 50.544 47.441 50.568 ;
     RECT  46.649 48.96 47.621 48.984 ;
     RECT  46.721 51.936 47.761 56.232 ;
     RECT  46.613 57.408 47.761 57.816 ;
     RECT  47.009 82.128 47.833 82.152 ;
     RECT  47.185 58.896 47.869 68.328 ;
     RECT  47.725 69.408 47.869 69.48 ;
     RECT  46.721 70.8 47.905 71.112 ;
     RECT  45.904 72.096 47.905 74.952 ;
     RECT  47.797 77.424 47.905 77.448 ;
     RECT  47.761 51.936 47.941 57.816 ;
     RECT  47.869 58.896 47.941 69.48 ;
     RECT  47.941 51.936 47.977 69.48 ;
     RECT  47.905 70.8 47.977 74.952 ;
     RECT  46.793 79.488 48.013 79.512 ;
     RECT  47.833 82.128 48.089 82.344 ;
     RECT  47.977 51.936 48.157 74.952 ;
     RECT  46.289 76.128 48.157 76.44 ;
     RECT  47.905 77.424 48.157 78.072 ;
     RECT  48.157 51.408 48.229 74.952 ;
     RECT  48.157 76.128 48.229 78.072 ;
     RECT  48.157 80.928 48.373 80.952 ;
     RECT  48.229 51.408 48.377 78.072 ;
     RECT  48.013 79.488 48.625 79.704 ;
     RECT  48.373 80.928 48.625 81 ;
     RECT  48.661 49.2 48.805 49.224 ;
     RECT  48.625 79.488 49.057 81 ;
     RECT  48.089 82.128 49.057 82.152 ;
     RECT  48.377 51.936 49.129 78.072 ;
     RECT  49.057 79.488 49.129 82.152 ;
     RECT  48.805 49.2 49.237 50.088 ;
     RECT  49.237 49.2 49.525 50.904 ;
     RECT  49.129 51.936 49.525 82.152 ;
     RECT  49.525 49.2 49.561 82.152 ;
     RECT  49.561 49.2 49.705 83.016 ;
     RECT  49.705 49.2 49.889 83.592 ;
     RECT  49.889 49.968 49.997 83.592 ;
     RECT  49.997 58.464 50.605 83.592 ;
     RECT  50.929 48.24 51.008 48.264 ;
     RECT  49.997 49.968 51.008 57.432 ;
     RECT  50.605 58.464 51.008 83.64 ;
     RECT  51.008 2.148 51.112 127.452 ;
     RECT  51.112 2.418 51.304 127.182 ;
     RECT  51.304 48.24 51.401 52.008 ;
     RECT  51.304 74.928 51.473 83.304 ;
     RECT  51.401 48.336 52.405 52.008 ;
     RECT  51.304 53.04 52.405 57.384 ;
     RECT  51.304 58.704 52.405 73.512 ;
     RECT  51.473 77.904 52.405 83.304 ;
     RECT  52.405 48.336 52.441 73.608 ;
     RECT  52.441 48.336 52.477 73.8 ;
     RECT  51.473 74.928 52.477 76.776 ;
     RECT  52.405 77.904 52.945 83.496 ;
     RECT  52.477 48.336 52.981 76.776 ;
     RECT  52.945 77.808 52.981 83.496 ;
     RECT  52.981 48.336 53.881 83.496 ;
     RECT  53.881 48.336 53.964 83.592 ;
    LAYER M5 ;
     RECT  16.08 0.016 19.08 0.131 ;
     RECT  16.176 0.131 19.08 0.563 ;
     RECT  29.136 0.016 35.016 1.187 ;
     RECT  16.272 0.563 19.08 1.763 ;
     RECT  29.328 1.187 35.016 1.763 ;
     RECT  16.752 1.763 19.08 1.907 ;
     RECT  2.4 2.137 2.52 2.151 ;
     RECT  7.8 2.137 7.92 2.151 ;
     RECT  13.2 2.137 13.32 2.151 ;
     RECT  24 2.137 24.12 2.151 ;
     RECT  29.4 1.763 35.016 2.151 ;
     RECT  40.2 2.137 40.32 2.151 ;
     RECT  45.6 2.137 45.72 2.151 ;
     RECT  51 2.137 51.12 2.151 ;
     RECT  16.752 1.907 18.912 2.291 ;
     RECT  29.4 2.151 35.112 2.291 ;
     RECT  16.752 2.291 16.776 2.915 ;
     RECT  18.192 2.291 18.912 2.915 ;
     RECT  29.4 2.291 33.48 3.443 ;
     RECT  34.8 2.291 35.112 3.733 ;
     RECT  18.6 2.915 18.912 3.925 ;
     RECT  34.8 3.733 35.208 3.925 ;
     RECT  29.4 3.443 32.52 4.595 ;
     RECT  34.8 3.925 36.12 5.171 ;
     RECT  36.096 5.171 36.12 5.219 ;
     RECT  34.8 5.171 35.112 5.605 ;
     RECT  34.032 5.605 35.112 6.851 ;
     RECT  43.584 4.933 43.608 18.949 ;
     RECT  16.176 6.133 16.2 21.971 ;
     RECT  14.832 21.925 14.856 22.067 ;
     RECT  18.6 3.925 19.656 22.067 ;
     RECT  7.8 2.151 8.112 22.165 ;
     RECT  37.296 5.173 37.32 42.709 ;
     RECT  37.152 42.709 37.32 44.723 ;
     RECT  37.296 44.723 37.32 47.845 ;
     RECT  37.2 47.845 37.32 47.891 ;
     RECT  43.584 18.949 43.656 47.989 ;
     RECT  7.8 22.165 8.28 49.715 ;
     RECT  6.288 49.477 6.312 49.763 ;
     RECT  2.4 2.151 2.712 50.389 ;
     RECT  18.6 22.067 18.912 50.533 ;
     RECT  2.4 50.389 2.856 50.675 ;
     RECT  7.8 49.715 8.112 51.253 ;
     RECT  52.992 51.157 53.016 51.395 ;
     RECT  37.2 47.891 37.224 51.493 ;
     RECT  40.2 2.151 40.512 51.493 ;
     RECT  43.44 47.989 43.656 51.541 ;
     RECT  41.856 44.965 41.88 51.587 ;
     RECT  0.144 51.397 0.168 51.683 ;
     RECT  17.616 50.533 18.912 51.829 ;
     RECT  17.28 51.829 18.912 52.259 ;
     RECT  17.52 52.259 18.912 52.403 ;
     RECT  4.272 49.333 4.296 52.981 ;
     RECT  5.568 52.885 5.592 52.981 ;
     RECT  37.2 51.493 37.656 53.027 ;
     RECT  3.888 52.981 4.296 53.123 ;
     RECT  40.08 51.493 40.512 53.173 ;
     RECT  37.2 53.027 37.224 53.219 ;
     RECT  43.44 51.541 44.424 53.459 ;
     RECT  7.8 51.253 8.472 53.507 ;
     RECT  39.648 53.173 40.512 53.555 ;
     RECT  3.888 53.123 3.912 53.603 ;
     RECT  5.568 52.981 6.264 53.603 ;
     RECT  5.568 53.603 5.592 54.179 ;
     RECT  38.256 53.797 38.28 54.659 ;
     RECT  2.4 50.675 2.712 54.661 ;
     RECT  34.8 6.851 35.112 55.285 ;
     RECT  36.096 53.941 36.12 55.285 ;
     RECT  34.8 55.285 36.12 55.331 ;
     RECT  40.2 53.555 40.512 55.333 ;
     RECT  6.24 55.141 6.264 55.525 ;
     RECT  26.976 44.677 27 55.525 ;
     RECT  17.616 52.403 18.912 55.715 ;
     RECT  2.4 54.661 3.528 55.813 ;
     RECT  4.512 54.133 4.536 55.813 ;
     RECT  6.24 55.525 6.312 55.813 ;
     RECT  7.8 53.507 8.112 55.813 ;
     RECT  34.8 55.331 35.352 55.813 ;
     RECT  2.4 55.813 4.536 55.907 ;
     RECT  17.856 55.715 18.912 55.955 ;
     RECT  34.656 55.813 35.352 55.955 ;
     RECT  6.24 55.813 8.112 56.099 ;
     RECT  2.4 55.907 2.856 56.291 ;
     RECT  40.2 55.333 41.448 56.389 ;
     RECT  42.48 55.573 42.504 56.389 ;
     RECT  4.224 55.907 4.536 56.483 ;
     RECT  6.816 56.099 8.112 56.483 ;
     RECT  26.976 55.525 27.192 56.483 ;
     RECT  40.2 56.389 42.504 57.011 ;
     RECT  42.336 57.011 42.504 57.107 ;
     RECT  32.448 53.557 32.472 57.299 ;
     RECT  43.584 53.459 44.424 57.349 ;
     RECT  45.6 2.151 45.912 57.349 ;
     RECT  53.808 57.109 53.832 57.395 ;
     RECT  0.144 56.053 0.168 57.539 ;
     RECT  4.32 56.483 4.536 57.541 ;
     RECT  5.664 56.821 5.688 57.541 ;
     RECT  42.48 57.107 42.504 57.541 ;
     RECT  43.584 57.349 45.912 57.541 ;
     RECT  40.2 57.011 41.352 58.117 ;
     RECT  5.664 57.541 6.072 58.163 ;
     RECT  34.656 55.955 35.112 58.163 ;
     RECT  3.936 57.541 4.536 58.403 ;
     RECT  42.48 57.541 45.912 58.499 ;
     RECT  29.4 4.595 29.712 58.645 ;
     RECT  39.36 58.117 41.352 58.645 ;
     RECT  37.728 55.813 37.752 58.691 ;
     RECT  42.864 58.499 45.912 58.691 ;
     RECT  39.36 58.645 41.4 58.741 ;
     RECT  24 2.151 24.312 58.885 ;
     RECT  25.344 58.645 25.368 58.885 ;
     RECT  38.832 58.741 41.4 59.123 ;
     RECT  29.4 58.645 30.696 59.219 ;
     RECT  39.36 59.123 41.4 59.315 ;
     RECT  4.464 58.403 4.536 59.749 ;
     RECT  34.8 58.163 35.112 59.749 ;
     RECT  43.584 58.691 45.912 59.843 ;
     RECT  39.36 59.315 41.352 60.035 ;
     RECT  28.32 57.541 28.344 60.083 ;
     RECT  38.16 59.173 38.184 60.227 ;
     RECT  34.8 59.749 35.592 60.515 ;
     RECT  40.08 60.035 41.352 60.515 ;
     RECT  29.4 59.219 29.712 60.517 ;
     RECT  37.008 59.605 37.032 60.901 ;
     RECT  36.144 60.901 37.032 60.947 ;
     RECT  24 58.885 25.368 60.949 ;
     RECT  4.416 59.749 4.536 61.043 ;
     RECT  32.448 59.749 32.472 61.043 ;
     RECT  18.288 55.955 18.912 61.187 ;
     RECT  29.28 60.517 29.712 61.235 ;
     RECT  38.976 60.325 39 61.477 ;
     RECT  38.976 61.477 39.048 61.619 ;
     RECT  34.8 60.515 35.112 61.621 ;
     RECT  36.144 60.947 36.84 61.621 ;
     RECT  0.144 61.669 0.168 61.859 ;
     RECT  23.328 60.949 25.368 61.907 ;
     RECT  4.512 61.043 4.536 62.003 ;
     RECT  26.976 56.483 27 62.053 ;
     RECT  33.312 62.053 33.336 62.101 ;
     RECT  33.12 62.101 33.336 62.149 ;
     RECT  34.8 61.621 36.84 62.149 ;
     RECT  33.12 62.149 36.84 62.243 ;
     RECT  51 2.151 51.312 62.341 ;
     RECT  33.312 62.243 36.84 62.387 ;
     RECT  33.312 62.387 36.552 62.531 ;
     RECT  26.976 62.053 27.144 62.533 ;
     RECT  39.024 61.619 39.048 62.533 ;
     RECT  40.2 60.515 41.352 62.533 ;
     RECT  50.64 62.341 51.312 62.579 ;
     RECT  43.632 59.843 45.912 62.581 ;
     RECT  30.816 60.229 30.84 62.627 ;
     RECT  26.976 62.533 27.96 62.629 ;
     RECT  39.024 62.533 41.352 62.723 ;
     RECT  26.976 62.629 28.104 62.771 ;
     RECT  50.688 62.579 51.312 62.867 ;
     RECT  24 61.907 25.368 63.205 ;
     RECT  26.976 62.771 27.96 63.251 ;
     RECT  33.312 62.531 33.336 63.251 ;
     RECT  42.864 62.581 45.912 63.299 ;
     RECT  34.8 62.531 36.552 63.347 ;
     RECT  31.92 61.765 31.944 63.443 ;
     RECT  36.528 63.347 36.552 63.491 ;
     RECT  50.736 62.867 51.312 63.587 ;
     RECT  53.808 63.013 53.832 63.827 ;
     RECT  23.616 63.205 25.368 63.875 ;
     RECT  33.072 63.781 33.096 63.971 ;
     RECT  38.928 63.205 38.952 64.019 ;
     RECT  23.616 63.875 24.312 64.115 ;
     RECT  50.88 63.587 51.312 64.307 ;
     RECT  0.144 64.117 0.168 64.403 ;
     RECT  26.976 63.251 27.144 64.403 ;
     RECT  24 64.115 24.312 64.885 ;
     RECT  25.344 63.875 25.368 64.885 ;
     RECT  43.632 63.299 45.912 64.885 ;
     RECT  37.008 63.685 37.032 64.931 ;
     RECT  24 64.885 25.368 64.933 ;
     RECT  0.192 65.365 0.216 65.555 ;
     RECT  43.632 64.885 46.152 65.555 ;
     RECT  24 64.933 25.512 65.699 ;
     RECT  34.8 63.347 35.352 65.699 ;
     RECT  51 64.307 51.312 66.229 ;
     RECT  26.976 64.403 27 66.469 ;
     RECT  24 65.699 25.464 66.517 ;
     RECT  23.904 66.517 25.464 66.563 ;
     RECT  49.824 66.229 51.312 66.563 ;
     RECT  50.592 66.563 51.312 66.613 ;
     RECT  50.592 66.613 51.912 66.659 ;
     RECT  34.8 65.699 35.208 66.661 ;
     RECT  43.632 65.555 45.912 66.755 ;
     RECT  33.984 66.661 35.208 66.757 ;
     RECT  51 66.659 51.912 66.803 ;
     RECT  23.904 66.563 24.312 67.283 ;
     RECT  40.2 62.723 41.352 67.285 ;
     RECT  33.984 66.757 35.88 67.331 ;
     RECT  40.08 67.285 41.352 67.381 ;
     RECT  26.976 66.469 27.96 67.427 ;
     RECT  34.704 67.331 35.208 67.523 ;
     RECT  0.144 67.381 0.168 67.667 ;
     RECT  37.344 67.717 37.368 67.813 ;
     RECT  37.2 67.813 37.368 67.859 ;
     RECT  37.2 67.859 37.224 68.099 ;
     RECT  32.832 67.669 32.856 68.291 ;
     RECT  40.032 67.381 41.352 68.675 ;
     RECT  34.704 67.523 35.112 68.821 ;
     RECT  34.464 68.821 35.112 68.917 ;
     RECT  44.976 66.755 45.912 68.917 ;
     RECT  34.464 68.917 35.208 68.965 ;
     RECT  40.08 68.675 41.352 69.155 ;
     RECT  34.032 68.965 35.208 69.539 ;
     RECT  53.808 69.253 53.832 69.539 ;
     RECT  32.352 68.917 32.376 69.587 ;
     RECT  44.976 68.917 46.008 70.019 ;
     RECT  34.464 69.539 35.208 70.115 ;
     RECT  7.152 56.483 8.112 70.549 ;
     RECT  0.192 70.357 0.216 70.643 ;
     RECT  7.152 70.549 8.232 70.739 ;
     RECT  32.208 70.261 32.232 70.739 ;
     RECT  51 66.803 51.312 70.741 ;
     RECT  50.688 70.741 51.312 71.027 ;
     RECT  25.44 66.563 25.464 71.267 ;
     RECT  26.976 67.427 27 71.459 ;
     RECT  6.048 58.163 6.072 71.461 ;
     RECT  7.152 70.739 8.112 71.461 ;
     RECT  43.632 66.755 43.656 71.509 ;
     RECT  40.2 69.155 41.352 71.797 ;
     RECT  42.864 71.509 43.656 72.227 ;
     RECT  6.048 71.461 8.112 72.419 ;
     RECT  40.2 71.797 41.496 72.659 ;
     RECT  40.2 72.659 41.352 72.995 ;
     RECT  42.864 72.227 43.32 72.995 ;
     RECT  44.976 70.019 45.912 73.573 ;
     RECT  42.864 72.995 42.888 73.619 ;
     RECT  34.464 70.115 35.112 73.667 ;
     RECT  6.048 72.419 6.072 73.957 ;
     RECT  7.152 72.419 8.112 73.957 ;
     RECT  0.144 73.813 0.168 74.387 ;
     RECT  6.048 73.957 8.112 74.435 ;
     RECT  44.112 73.573 45.912 74.629 ;
     RECT  44.016 74.629 45.912 75.299 ;
     RECT  44.016 75.299 44.136 75.395 ;
     RECT  6.288 74.435 8.112 76.211 ;
     RECT  6.576 76.211 8.112 76.259 ;
     RECT  44.112 75.395 44.136 76.357 ;
     RECT  42.912 75.397 42.936 76.451 ;
     RECT  4.464 74.821 4.488 76.499 ;
     RECT  44.112 76.357 44.472 78.035 ;
     RECT  44.112 78.035 44.184 78.131 ;
     RECT  45.6 75.299 45.912 78.277 ;
     RECT  41.904 76.405 41.928 78.323 ;
     RECT  6.576 76.259 6.6 78.613 ;
     RECT  7.8 76.259 8.112 78.613 ;
     RECT  45.6 78.277 46.296 78.613 ;
     RECT  45.504 78.613 46.296 79.043 ;
     RECT  40.2 72.995 40.512 79.045 ;
     RECT  6.576 78.613 8.112 79.235 ;
     RECT  45.504 79.043 45.912 79.283 ;
     RECT  42.672 79.381 42.696 79.523 ;
     RECT  40.08 79.045 40.512 79.763 ;
     RECT  0.144 77.893 0.168 80.195 ;
     RECT  41.616 80.005 41.64 80.917 ;
     RECT  41.616 80.917 41.784 80.963 ;
     RECT  41.76 80.963 41.784 81.059 ;
     RECT  6.576 79.235 6.6 81.539 ;
     RECT  13.2 2.151 13.512 82.165 ;
     RECT  51 71.027 51.312 82.981 ;
     RECT  50.88 82.981 51.312 83.171 ;
     RECT  44.16 78.131 44.184 83.267 ;
     RECT  7.8 79.235 8.112 83.509 ;
     RECT  0.144 83.605 0.168 83.795 ;
     RECT  7.8 83.509 8.232 84.419 ;
     RECT  12.384 82.165 13.512 100.883 ;
     RECT  15.888 52.357 15.912 101.029 ;
     RECT  6.528 81.925 6.552 101.075 ;
     RECT  15.888 101.029 16.344 125.843 ;
     RECT  15.888 125.843 15.912 127.381 ;
     RECT  2.4 56.291 2.712 127.449 ;
     RECT  7.8 84.419 8.112 127.449 ;
     RECT  13.2 100.883 13.512 127.449 ;
     RECT  18.6 61.187 18.912 127.449 ;
     RECT  24 67.283 24.312 127.449 ;
     RECT  29.4 61.235 29.712 127.449 ;
     RECT  34.8 73.667 35.112 127.449 ;
     RECT  40.2 79.763 40.512 127.449 ;
     RECT  45.6 79.283 45.912 127.449 ;
     RECT  51 83.171 51.312 127.449 ;
     RECT  2.4 127.449 2.52 127.463 ;
     RECT  7.8 127.449 7.92 127.463 ;
     RECT  13.2 127.449 13.32 127.463 ;
     RECT  18.6 127.449 18.72 127.463 ;
     RECT  24 127.449 24.12 127.463 ;
     RECT  29.4 127.449 29.52 127.463 ;
     RECT  34.8 127.449 34.92 127.463 ;
     RECT  40.2 127.449 40.32 127.463 ;
     RECT  45.6 127.449 45.72 127.463 ;
     RECT  51 127.449 51.12 127.463 ;
     RECT  15.888 127.381 16.296 129.552 ;
  END
END qkd_astk_er_owner_st
END LIBRARY
